VERSION 5.8 ;
BUSBITCHARS "[]" ;
DIVIDERCHAR "/" ;
UNITS
    DATABASE MICRONS 1000 ;
END UNITS

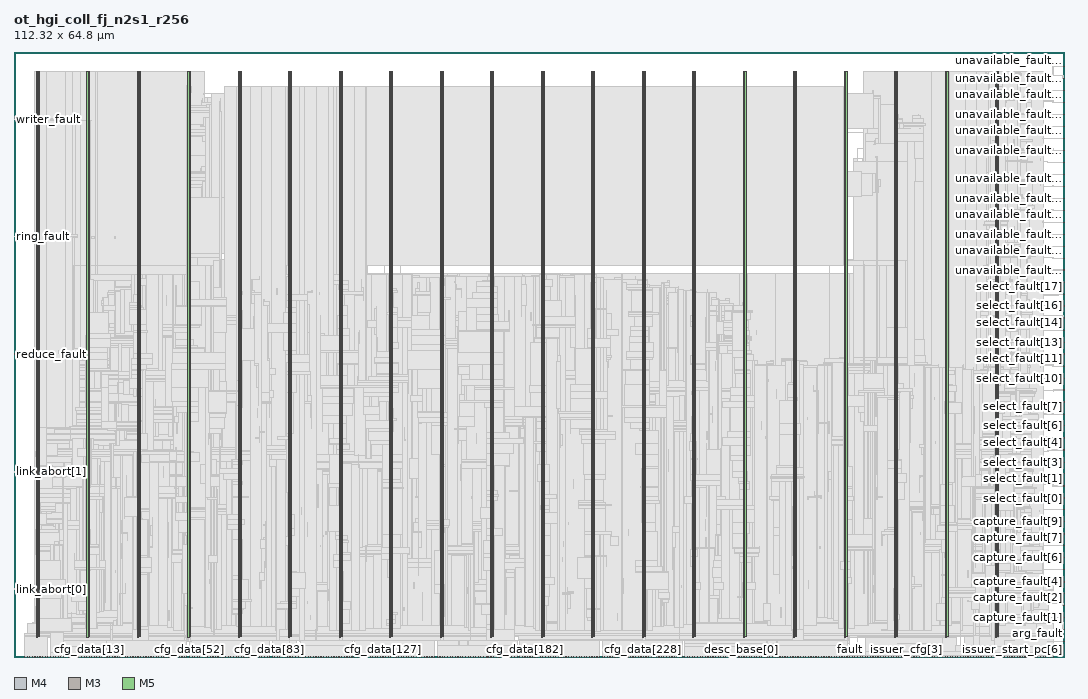
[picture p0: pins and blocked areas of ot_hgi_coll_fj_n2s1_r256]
MACRO ot_hgi_coll_fj_n2s1_r256
  FOREIGN ot_hgi_coll_fj_n2s1_r256 0 0 ;
  CLASS BLOCK ;
  SIZE 112.32 BY 64.8 ;
  PIN arg_fault
    DIRECTION INPUT ;
    USE SIGNAL ;
    PORT
      LAYER M4 ;
        RECT  112.236 1.632 112.32 1.656 ;
    END
  END arg_fault
  PIN capture_fault[0]
    DIRECTION INPUT ;
    USE SIGNAL ;
    PORT
      LAYER M4 ;
        RECT  112.236 2.928 112.32 2.952 ;
    END
  END capture_fault[0]
  PIN capture_fault[1]
    DIRECTION INPUT ;
    USE SIGNAL ;
    PORT
      LAYER M4 ;
        RECT  112.236 4.176 112.32 4.2 ;
    END
  END capture_fault[1]
  PIN capture_fault[2]
    DIRECTION INPUT ;
    USE SIGNAL ;
    PORT
      LAYER M4 ;
        RECT  112.236 5.472 112.32 5.496 ;
    END
  END capture_fault[2]
  PIN capture_fault[3]
    DIRECTION INPUT ;
    USE SIGNAL ;
    PORT
      LAYER M4 ;
        RECT  112.236 6.768 112.32 6.792 ;
    END
  END capture_fault[3]
  PIN capture_fault[4]
    DIRECTION INPUT ;
    USE SIGNAL ;
    PORT
      LAYER M4 ;
        RECT  112.236 8.016 112.32 8.04 ;
    END
  END capture_fault[4]
  PIN capture_fault[5]
    DIRECTION INPUT ;
    USE SIGNAL ;
    PORT
      LAYER M4 ;
        RECT  112.236 9.312 112.32 9.336 ;
    END
  END capture_fault[5]
  PIN capture_fault[6]
    DIRECTION INPUT ;
    USE SIGNAL ;
    PORT
      LAYER M4 ;
        RECT  112.236 10.608 112.32 10.632 ;
    END
  END capture_fault[6]
  PIN capture_fault[7]
    DIRECTION INPUT ;
    USE SIGNAL ;
    PORT
      LAYER M4 ;
        RECT  112.236 11.904 112.32 11.928 ;
    END
  END capture_fault[7]
  PIN capture_fault[8]
    DIRECTION INPUT ;
    USE SIGNAL ;
    PORT
      LAYER M4 ;
        RECT  112.236 13.152 112.32 13.176 ;
    END
  END capture_fault[8]
  PIN capture_fault[9]
    DIRECTION INPUT ;
    USE SIGNAL ;
    PORT
      LAYER M4 ;
        RECT  112.236 14.448 112.32 14.472 ;
    END
  END capture_fault[9]
  PIN cfg_addr[0]
    DIRECTION INPUT ;
    USE SIGNAL ;
    PORT
      LAYER M3 ;
        RECT  1.116 0 1.134 0.038 ;
    END
  END cfg_addr[0]
  PIN cfg_addr[10]
    DIRECTION INPUT ;
    USE SIGNAL ;
    PORT
      LAYER M3 ;
        RECT  3.888 0 3.906 0.038 ;
    END
  END cfg_addr[10]
  PIN cfg_addr[11]
    DIRECTION INPUT ;
    USE SIGNAL ;
    PORT
      LAYER M3 ;
        RECT  4.176 0 4.194 0.038 ;
    END
  END cfg_addr[11]
  PIN cfg_addr[1]
    DIRECTION INPUT ;
    USE SIGNAL ;
    PORT
      LAYER M3 ;
        RECT  1.404 0 1.422 0.038 ;
    END
  END cfg_addr[1]
  PIN cfg_addr[2]
    DIRECTION INPUT ;
    USE SIGNAL ;
    PORT
      LAYER M3 ;
        RECT  1.692 0 1.71 0.038 ;
    END
  END cfg_addr[2]
  PIN cfg_addr[3]
    DIRECTION INPUT ;
    USE SIGNAL ;
    PORT
      LAYER M3 ;
        RECT  1.944 0 1.962 0.038 ;
    END
  END cfg_addr[3]
  PIN cfg_addr[4]
    DIRECTION INPUT ;
    USE SIGNAL ;
    PORT
      LAYER M3 ;
        RECT  2.232 0 2.25 0.038 ;
    END
  END cfg_addr[4]
  PIN cfg_addr[5]
    DIRECTION INPUT ;
    USE SIGNAL ;
    PORT
      LAYER M3 ;
        RECT  2.52 0 2.538 0.038 ;
    END
  END cfg_addr[5]
  PIN cfg_addr[6]
    DIRECTION INPUT ;
    USE SIGNAL ;
    PORT
      LAYER M3 ;
        RECT  2.772 0 2.79 0.038 ;
    END
  END cfg_addr[6]
  PIN cfg_addr[7]
    DIRECTION INPUT ;
    USE SIGNAL ;
    PORT
      LAYER M3 ;
        RECT  3.06 0 3.078 0.038 ;
    END
  END cfg_addr[7]
  PIN cfg_addr[8]
    DIRECTION INPUT ;
    USE SIGNAL ;
    PORT
      LAYER M3 ;
        RECT  3.348 0 3.366 0.038 ;
    END
  END cfg_addr[8]
  PIN cfg_addr[9]
    DIRECTION INPUT ;
    USE SIGNAL ;
    PORT
      LAYER M3 ;
        RECT  3.6 0 3.618 0.038 ;
    END
  END cfg_addr[9]
  PIN cfg_data[0]
    DIRECTION INPUT ;
    USE SIGNAL ;
    PORT
      LAYER M3 ;
        RECT  4.428 0 4.446 0.038 ;
    END
  END cfg_data[0]
  PIN cfg_data[100]
    DIRECTION INPUT ;
    USE SIGNAL ;
    PORT
      LAYER M5 ;
        RECT  32.016 0 32.04 0.084 ;
    END
  END cfg_data[100]
  PIN cfg_data[101]
    DIRECTION INPUT ;
    USE SIGNAL ;
    PORT
      LAYER M5 ;
        RECT  32.304 0 32.328 0.084 ;
    END
  END cfg_data[101]
  PIN cfg_data[102]
    DIRECTION INPUT ;
    USE SIGNAL ;
    PORT
      LAYER M5 ;
        RECT  32.544 0 32.568 0.084 ;
    END
  END cfg_data[102]
  PIN cfg_data[103]
    DIRECTION INPUT ;
    USE SIGNAL ;
    PORT
      LAYER M5 ;
        RECT  32.832 0 32.856 0.084 ;
    END
  END cfg_data[103]
  PIN cfg_data[104]
    DIRECTION INPUT ;
    USE SIGNAL ;
    PORT
      LAYER M5 ;
        RECT  33.12 0 33.144 0.084 ;
    END
  END cfg_data[104]
  PIN cfg_data[105]
    DIRECTION INPUT ;
    USE SIGNAL ;
    PORT
      LAYER M5 ;
        RECT  33.408 0 33.432 0.084 ;
    END
  END cfg_data[105]
  PIN cfg_data[106]
    DIRECTION INPUT ;
    USE SIGNAL ;
    PORT
      LAYER M5 ;
        RECT  33.648 0 33.672 0.084 ;
    END
  END cfg_data[106]
  PIN cfg_data[107]
    DIRECTION INPUT ;
    USE SIGNAL ;
    PORT
      LAYER M5 ;
        RECT  33.936 0 33.96 0.084 ;
    END
  END cfg_data[107]
  PIN cfg_data[108]
    DIRECTION INPUT ;
    USE SIGNAL ;
    PORT
      LAYER M5 ;
        RECT  34.224 0 34.248 0.084 ;
    END
  END cfg_data[108]
  PIN cfg_data[109]
    DIRECTION INPUT ;
    USE SIGNAL ;
    PORT
      LAYER M5 ;
        RECT  34.512 0 34.536 0.084 ;
    END
  END cfg_data[109]
  PIN cfg_data[10]
    DIRECTION INPUT ;
    USE SIGNAL ;
    PORT
      LAYER M3 ;
        RECT  7.2 0 7.218 0.038 ;
    END
  END cfg_data[10]
  PIN cfg_data[110]
    DIRECTION INPUT ;
    USE SIGNAL ;
    PORT
      LAYER M5 ;
        RECT  34.752 0 34.776 0.084 ;
    END
  END cfg_data[110]
  PIN cfg_data[111]
    DIRECTION INPUT ;
    USE SIGNAL ;
    PORT
      LAYER M5 ;
        RECT  35.04 0 35.064 0.084 ;
    END
  END cfg_data[111]
  PIN cfg_data[112]
    DIRECTION INPUT ;
    USE SIGNAL ;
    PORT
      LAYER M5 ;
        RECT  35.328 0 35.352 0.084 ;
    END
  END cfg_data[112]
  PIN cfg_data[113]
    DIRECTION INPUT ;
    USE SIGNAL ;
    PORT
      LAYER M5 ;
        RECT  35.616 0 35.64 0.084 ;
    END
  END cfg_data[113]
  PIN cfg_data[114]
    DIRECTION INPUT ;
    USE SIGNAL ;
    PORT
      LAYER M5 ;
        RECT  35.856 0 35.88 0.084 ;
    END
  END cfg_data[114]
  PIN cfg_data[115]
    DIRECTION INPUT ;
    USE SIGNAL ;
    PORT
      LAYER M5 ;
        RECT  36.144 0 36.168 0.084 ;
    END
  END cfg_data[115]
  PIN cfg_data[116]
    DIRECTION INPUT ;
    USE SIGNAL ;
    PORT
      LAYER M3 ;
        RECT  36.432 0 36.45 0.038 ;
    END
  END cfg_data[116]
  PIN cfg_data[117]
    DIRECTION INPUT ;
    USE SIGNAL ;
    PORT
      LAYER M3 ;
        RECT  36.72 0 36.738 0.038 ;
    END
  END cfg_data[117]
  PIN cfg_data[118]
    DIRECTION INPUT ;
    USE SIGNAL ;
    PORT
      LAYER M3 ;
        RECT  36.972 0 36.99 0.038 ;
    END
  END cfg_data[118]
  PIN cfg_data[119]
    DIRECTION INPUT ;
    USE SIGNAL ;
    PORT
      LAYER M3 ;
        RECT  37.26 0 37.278 0.038 ;
    END
  END cfg_data[119]
  PIN cfg_data[11]
    DIRECTION INPUT ;
    USE SIGNAL ;
    PORT
      LAYER M3 ;
        RECT  7.488 0 7.506 0.038 ;
    END
  END cfg_data[11]
  PIN cfg_data[120]
    DIRECTION INPUT ;
    USE SIGNAL ;
    PORT
      LAYER M3 ;
        RECT  37.548 0 37.566 0.038 ;
    END
  END cfg_data[120]
  PIN cfg_data[121]
    DIRECTION INPUT ;
    USE SIGNAL ;
    PORT
      LAYER M3 ;
        RECT  37.8 0 37.818 0.038 ;
    END
  END cfg_data[121]
  PIN cfg_data[122]
    DIRECTION INPUT ;
    USE SIGNAL ;
    PORT
      LAYER M3 ;
        RECT  38.088 0 38.106 0.038 ;
    END
  END cfg_data[122]
  PIN cfg_data[123]
    DIRECTION INPUT ;
    USE SIGNAL ;
    PORT
      LAYER M3 ;
        RECT  38.376 0 38.394 0.038 ;
    END
  END cfg_data[123]
  PIN cfg_data[124]
    DIRECTION INPUT ;
    USE SIGNAL ;
    PORT
      LAYER M3 ;
        RECT  38.628 0 38.646 0.038 ;
    END
  END cfg_data[124]
  PIN cfg_data[125]
    DIRECTION INPUT ;
    USE SIGNAL ;
    PORT
      LAYER M3 ;
        RECT  38.916 0 38.934 0.038 ;
    END
  END cfg_data[125]
  PIN cfg_data[126]
    DIRECTION INPUT ;
    USE SIGNAL ;
    PORT
      LAYER M3 ;
        RECT  39.204 0 39.222 0.038 ;
    END
  END cfg_data[126]
  PIN cfg_data[127]
    DIRECTION INPUT ;
    USE SIGNAL ;
    PORT
      LAYER M3 ;
        RECT  39.456 0 39.474 0.038 ;
    END
  END cfg_data[127]
  PIN cfg_data[128]
    DIRECTION INPUT ;
    USE SIGNAL ;
    PORT
      LAYER M3 ;
        RECT  39.744 0 39.762 0.038 ;
    END
  END cfg_data[128]
  PIN cfg_data[129]
    DIRECTION INPUT ;
    USE SIGNAL ;
    PORT
      LAYER M3 ;
        RECT  40.032 0 40.05 0.038 ;
    END
  END cfg_data[129]
  PIN cfg_data[12]
    DIRECTION INPUT ;
    USE SIGNAL ;
    PORT
      LAYER M3 ;
        RECT  7.74 0 7.758 0.038 ;
    END
  END cfg_data[12]
  PIN cfg_data[130]
    DIRECTION INPUT ;
    USE SIGNAL ;
    PORT
      LAYER M3 ;
        RECT  40.284 0 40.302 0.038 ;
    END
  END cfg_data[130]
  PIN cfg_data[131]
    DIRECTION INPUT ;
    USE SIGNAL ;
    PORT
      LAYER M3 ;
        RECT  40.572 0 40.59 0.038 ;
    END
  END cfg_data[131]
  PIN cfg_data[132]
    DIRECTION INPUT ;
    USE SIGNAL ;
    PORT
      LAYER M3 ;
        RECT  40.86 0 40.878 0.038 ;
    END
  END cfg_data[132]
  PIN cfg_data[133]
    DIRECTION INPUT ;
    USE SIGNAL ;
    PORT
      LAYER M3 ;
        RECT  41.112 0 41.13 0.038 ;
    END
  END cfg_data[133]
  PIN cfg_data[134]
    DIRECTION INPUT ;
    USE SIGNAL ;
    PORT
      LAYER M3 ;
        RECT  41.4 0 41.418 0.038 ;
    END
  END cfg_data[134]
  PIN cfg_data[135]
    DIRECTION INPUT ;
    USE SIGNAL ;
    PORT
      LAYER M3 ;
        RECT  41.688 0 41.706 0.038 ;
    END
  END cfg_data[135]
  PIN cfg_data[136]
    DIRECTION INPUT ;
    USE SIGNAL ;
    PORT
      LAYER M3 ;
        RECT  41.94 0 41.958 0.038 ;
    END
  END cfg_data[136]
  PIN cfg_data[137]
    DIRECTION INPUT ;
    USE SIGNAL ;
    PORT
      LAYER M3 ;
        RECT  42.228 0 42.246 0.038 ;
    END
  END cfg_data[137]
  PIN cfg_data[138]
    DIRECTION INPUT ;
    USE SIGNAL ;
    PORT
      LAYER M3 ;
        RECT  42.516 0 42.534 0.038 ;
    END
  END cfg_data[138]
  PIN cfg_data[139]
    DIRECTION INPUT ;
    USE SIGNAL ;
    PORT
      LAYER M3 ;
        RECT  42.768 0 42.786 0.038 ;
    END
  END cfg_data[139]
  PIN cfg_data[13]
    DIRECTION INPUT ;
    USE SIGNAL ;
    PORT
      LAYER M3 ;
        RECT  8.028 0 8.046 0.038 ;
    END
  END cfg_data[13]
  PIN cfg_data[140]
    DIRECTION INPUT ;
    USE SIGNAL ;
    PORT
      LAYER M3 ;
        RECT  43.056 0 43.074 0.038 ;
    END
  END cfg_data[140]
  PIN cfg_data[141]
    DIRECTION INPUT ;
    USE SIGNAL ;
    PORT
      LAYER M3 ;
        RECT  43.344 0 43.362 0.038 ;
    END
  END cfg_data[141]
  PIN cfg_data[142]
    DIRECTION INPUT ;
    USE SIGNAL ;
    PORT
      LAYER M3 ;
        RECT  43.596 0 43.614 0.038 ;
    END
  END cfg_data[142]
  PIN cfg_data[143]
    DIRECTION INPUT ;
    USE SIGNAL ;
    PORT
      LAYER M3 ;
        RECT  43.884 0 43.902 0.038 ;
    END
  END cfg_data[143]
  PIN cfg_data[144]
    DIRECTION INPUT ;
    USE SIGNAL ;
    PORT
      LAYER M3 ;
        RECT  44.172 0 44.19 0.038 ;
    END
  END cfg_data[144]
  PIN cfg_data[145]
    DIRECTION INPUT ;
    USE SIGNAL ;
    PORT
      LAYER M3 ;
        RECT  44.424 0 44.442 0.038 ;
    END
  END cfg_data[145]
  PIN cfg_data[146]
    DIRECTION INPUT ;
    USE SIGNAL ;
    PORT
      LAYER M3 ;
        RECT  44.712 0 44.73 0.038 ;
    END
  END cfg_data[146]
  PIN cfg_data[147]
    DIRECTION INPUT ;
    USE SIGNAL ;
    PORT
      LAYER M3 ;
        RECT  44.964 0 44.982 0.038 ;
    END
  END cfg_data[147]
  PIN cfg_data[148]
    DIRECTION INPUT ;
    USE SIGNAL ;
    PORT
      LAYER M5 ;
        RECT  45.264 0 45.288 0.084 ;
    END
  END cfg_data[148]
  PIN cfg_data[149]
    DIRECTION INPUT ;
    USE SIGNAL ;
    PORT
      LAYER M5 ;
        RECT  45.552 0 45.576 0.084 ;
    END
  END cfg_data[149]
  PIN cfg_data[14]
    DIRECTION INPUT ;
    USE SIGNAL ;
    PORT
      LAYER M3 ;
        RECT  8.316 0 8.334 0.038 ;
    END
  END cfg_data[14]
  PIN cfg_data[150]
    DIRECTION INPUT ;
    USE SIGNAL ;
    PORT
      LAYER M5 ;
        RECT  45.792 0 45.816 0.084 ;
    END
  END cfg_data[150]
  PIN cfg_data[151]
    DIRECTION INPUT ;
    USE SIGNAL ;
    PORT
      LAYER M5 ;
        RECT  46.08 0 46.104 0.084 ;
    END
  END cfg_data[151]
  PIN cfg_data[152]
    DIRECTION INPUT ;
    USE SIGNAL ;
    PORT
      LAYER M5 ;
        RECT  46.368 0 46.392 0.084 ;
    END
  END cfg_data[152]
  PIN cfg_data[153]
    DIRECTION INPUT ;
    USE SIGNAL ;
    PORT
      LAYER M5 ;
        RECT  46.656 0 46.68 0.084 ;
    END
  END cfg_data[153]
  PIN cfg_data[154]
    DIRECTION INPUT ;
    USE SIGNAL ;
    PORT
      LAYER M5 ;
        RECT  46.896 0 46.92 0.084 ;
    END
  END cfg_data[154]
  PIN cfg_data[155]
    DIRECTION INPUT ;
    USE SIGNAL ;
    PORT
      LAYER M5 ;
        RECT  47.184 0 47.208 0.084 ;
    END
  END cfg_data[155]
  PIN cfg_data[156]
    DIRECTION INPUT ;
    USE SIGNAL ;
    PORT
      LAYER M5 ;
        RECT  47.472 0 47.496 0.084 ;
    END
  END cfg_data[156]
  PIN cfg_data[157]
    DIRECTION INPUT ;
    USE SIGNAL ;
    PORT
      LAYER M5 ;
        RECT  47.76 0 47.784 0.084 ;
    END
  END cfg_data[157]
  PIN cfg_data[158]
    DIRECTION INPUT ;
    USE SIGNAL ;
    PORT
      LAYER M5 ;
        RECT  48 0 48.024 0.084 ;
    END
  END cfg_data[158]
  PIN cfg_data[159]
    DIRECTION INPUT ;
    USE SIGNAL ;
    PORT
      LAYER M5 ;
        RECT  48.288 0 48.312 0.084 ;
    END
  END cfg_data[159]
  PIN cfg_data[15]
    DIRECTION INPUT ;
    USE SIGNAL ;
    PORT
      LAYER M3 ;
        RECT  8.568 0 8.586 0.038 ;
    END
  END cfg_data[15]
  PIN cfg_data[160]
    DIRECTION INPUT ;
    USE SIGNAL ;
    PORT
      LAYER M5 ;
        RECT  48.576 0 48.6 0.084 ;
    END
  END cfg_data[160]
  PIN cfg_data[161]
    DIRECTION INPUT ;
    USE SIGNAL ;
    PORT
      LAYER M5 ;
        RECT  48.816 0 48.84 0.084 ;
    END
  END cfg_data[161]
  PIN cfg_data[162]
    DIRECTION INPUT ;
    USE SIGNAL ;
    PORT
      LAYER M5 ;
        RECT  49.104 0 49.128 0.084 ;
    END
  END cfg_data[162]
  PIN cfg_data[163]
    DIRECTION INPUT ;
    USE SIGNAL ;
    PORT
      LAYER M5 ;
        RECT  49.392 0 49.416 0.084 ;
    END
  END cfg_data[163]
  PIN cfg_data[164]
    DIRECTION INPUT ;
    USE SIGNAL ;
    PORT
      LAYER M5 ;
        RECT  49.68 0 49.704 0.084 ;
    END
  END cfg_data[164]
  PIN cfg_data[165]
    DIRECTION INPUT ;
    USE SIGNAL ;
    PORT
      LAYER M5 ;
        RECT  49.92 0 49.944 0.084 ;
    END
  END cfg_data[165]
  PIN cfg_data[166]
    DIRECTION INPUT ;
    USE SIGNAL ;
    PORT
      LAYER M5 ;
        RECT  50.208 0 50.232 0.084 ;
    END
  END cfg_data[166]
  PIN cfg_data[167]
    DIRECTION INPUT ;
    USE SIGNAL ;
    PORT
      LAYER M5 ;
        RECT  50.496 0 50.52 0.084 ;
    END
  END cfg_data[167]
  PIN cfg_data[168]
    DIRECTION INPUT ;
    USE SIGNAL ;
    PORT
      LAYER M5 ;
        RECT  50.784 0 50.808 0.084 ;
    END
  END cfg_data[168]
  PIN cfg_data[169]
    DIRECTION INPUT ;
    USE SIGNAL ;
    PORT
      LAYER M5 ;
        RECT  51.024 0 51.048 0.084 ;
    END
  END cfg_data[169]
  PIN cfg_data[16]
    DIRECTION INPUT ;
    USE SIGNAL ;
    PORT
      LAYER M3 ;
        RECT  8.856 0 8.874 0.038 ;
    END
  END cfg_data[16]
  PIN cfg_data[170]
    DIRECTION INPUT ;
    USE SIGNAL ;
    PORT
      LAYER M5 ;
        RECT  51.312 0 51.336 0.084 ;
    END
  END cfg_data[170]
  PIN cfg_data[171]
    DIRECTION INPUT ;
    USE SIGNAL ;
    PORT
      LAYER M5 ;
        RECT  51.6 0 51.624 0.084 ;
    END
  END cfg_data[171]
  PIN cfg_data[172]
    DIRECTION INPUT ;
    USE SIGNAL ;
    PORT
      LAYER M5 ;
        RECT  51.888 0 51.912 0.084 ;
    END
  END cfg_data[172]
  PIN cfg_data[173]
    DIRECTION INPUT ;
    USE SIGNAL ;
    PORT
      LAYER M5 ;
        RECT  52.128 0 52.152 0.084 ;
    END
  END cfg_data[173]
  PIN cfg_data[174]
    DIRECTION INPUT ;
    USE SIGNAL ;
    PORT
      LAYER M5 ;
        RECT  52.416 0 52.44 0.084 ;
    END
  END cfg_data[174]
  PIN cfg_data[175]
    DIRECTION INPUT ;
    USE SIGNAL ;
    PORT
      LAYER M5 ;
        RECT  52.704 0 52.728 0.084 ;
    END
  END cfg_data[175]
  PIN cfg_data[176]
    DIRECTION INPUT ;
    USE SIGNAL ;
    PORT
      LAYER M5 ;
        RECT  52.992 0 53.016 0.084 ;
    END
  END cfg_data[176]
  PIN cfg_data[177]
    DIRECTION INPUT ;
    USE SIGNAL ;
    PORT
      LAYER M5 ;
        RECT  53.232 0 53.256 0.084 ;
    END
  END cfg_data[177]
  PIN cfg_data[178]
    DIRECTION INPUT ;
    USE SIGNAL ;
    PORT
      LAYER M5 ;
        RECT  53.52 0 53.544 0.084 ;
    END
  END cfg_data[178]
  PIN cfg_data[179]
    DIRECTION INPUT ;
    USE SIGNAL ;
    PORT
      LAYER M5 ;
        RECT  53.808 0 53.832 0.084 ;
    END
  END cfg_data[179]
  PIN cfg_data[17]
    DIRECTION INPUT ;
    USE SIGNAL ;
    PORT
      LAYER M3 ;
        RECT  9.144 0 9.162 0.038 ;
    END
  END cfg_data[17]
  PIN cfg_data[180]
    DIRECTION INPUT ;
    USE SIGNAL ;
    PORT
      LAYER M3 ;
        RECT  54.072 0 54.09 0.038 ;
    END
  END cfg_data[180]
  PIN cfg_data[181]
    DIRECTION INPUT ;
    USE SIGNAL ;
    PORT
      LAYER M3 ;
        RECT  54.36 0 54.378 0.038 ;
    END
  END cfg_data[181]
  PIN cfg_data[182]
    DIRECTION INPUT ;
    USE SIGNAL ;
    PORT
      LAYER M3 ;
        RECT  54.648 0 54.666 0.038 ;
    END
  END cfg_data[182]
  PIN cfg_data[183]
    DIRECTION INPUT ;
    USE SIGNAL ;
    PORT
      LAYER M3 ;
        RECT  54.9 0 54.918 0.038 ;
    END
  END cfg_data[183]
  PIN cfg_data[184]
    DIRECTION INPUT ;
    USE SIGNAL ;
    PORT
      LAYER M3 ;
        RECT  55.188 0 55.206 0.038 ;
    END
  END cfg_data[184]
  PIN cfg_data[185]
    DIRECTION INPUT ;
    USE SIGNAL ;
    PORT
      LAYER M3 ;
        RECT  55.476 0 55.494 0.038 ;
    END
  END cfg_data[185]
  PIN cfg_data[186]
    DIRECTION INPUT ;
    USE SIGNAL ;
    PORT
      LAYER M3 ;
        RECT  55.728 0 55.746 0.038 ;
    END
  END cfg_data[186]
  PIN cfg_data[187]
    DIRECTION INPUT ;
    USE SIGNAL ;
    PORT
      LAYER M3 ;
        RECT  56.016 0 56.034 0.038 ;
    END
  END cfg_data[187]
  PIN cfg_data[188]
    DIRECTION INPUT ;
    USE SIGNAL ;
    PORT
      LAYER M3 ;
        RECT  56.304 0 56.322 0.038 ;
    END
  END cfg_data[188]
  PIN cfg_data[189]
    DIRECTION INPUT ;
    USE SIGNAL ;
    PORT
      LAYER M3 ;
        RECT  56.556 0 56.574 0.038 ;
    END
  END cfg_data[189]
  PIN cfg_data[18]
    DIRECTION INPUT ;
    USE SIGNAL ;
    PORT
      LAYER M3 ;
        RECT  9.396 0 9.414 0.038 ;
    END
  END cfg_data[18]
  PIN cfg_data[190]
    DIRECTION INPUT ;
    USE SIGNAL ;
    PORT
      LAYER M3 ;
        RECT  56.844 0 56.862 0.038 ;
    END
  END cfg_data[190]
  PIN cfg_data[191]
    DIRECTION INPUT ;
    USE SIGNAL ;
    PORT
      LAYER M3 ;
        RECT  57.132 0 57.15 0.038 ;
    END
  END cfg_data[191]
  PIN cfg_data[192]
    DIRECTION INPUT ;
    USE SIGNAL ;
    PORT
      LAYER M3 ;
        RECT  57.384 0 57.402 0.038 ;
    END
  END cfg_data[192]
  PIN cfg_data[193]
    DIRECTION INPUT ;
    USE SIGNAL ;
    PORT
      LAYER M3 ;
        RECT  57.672 0 57.69 0.038 ;
    END
  END cfg_data[193]
  PIN cfg_data[194]
    DIRECTION INPUT ;
    USE SIGNAL ;
    PORT
      LAYER M3 ;
        RECT  57.96 0 57.978 0.038 ;
    END
  END cfg_data[194]
  PIN cfg_data[195]
    DIRECTION INPUT ;
    USE SIGNAL ;
    PORT
      LAYER M3 ;
        RECT  58.212 0 58.23 0.038 ;
    END
  END cfg_data[195]
  PIN cfg_data[196]
    DIRECTION INPUT ;
    USE SIGNAL ;
    PORT
      LAYER M3 ;
        RECT  58.5 0 58.518 0.038 ;
    END
  END cfg_data[196]
  PIN cfg_data[197]
    DIRECTION INPUT ;
    USE SIGNAL ;
    PORT
      LAYER M3 ;
        RECT  58.788 0 58.806 0.038 ;
    END
  END cfg_data[197]
  PIN cfg_data[198]
    DIRECTION INPUT ;
    USE SIGNAL ;
    PORT
      LAYER M3 ;
        RECT  59.04 0 59.058 0.038 ;
    END
  END cfg_data[198]
  PIN cfg_data[199]
    DIRECTION INPUT ;
    USE SIGNAL ;
    PORT
      LAYER M3 ;
        RECT  59.328 0 59.346 0.038 ;
    END
  END cfg_data[199]
  PIN cfg_data[19]
    DIRECTION INPUT ;
    USE SIGNAL ;
    PORT
      LAYER M3 ;
        RECT  9.684 0 9.702 0.038 ;
    END
  END cfg_data[19]
  PIN cfg_data[1]
    DIRECTION INPUT ;
    USE SIGNAL ;
    PORT
      LAYER M3 ;
        RECT  4.716 0 4.734 0.038 ;
    END
  END cfg_data[1]
  PIN cfg_data[200]
    DIRECTION INPUT ;
    USE SIGNAL ;
    PORT
      LAYER M3 ;
        RECT  59.616 0 59.634 0.038 ;
    END
  END cfg_data[200]
  PIN cfg_data[201]
    DIRECTION INPUT ;
    USE SIGNAL ;
    PORT
      LAYER M3 ;
        RECT  59.868 0 59.886 0.038 ;
    END
  END cfg_data[201]
  PIN cfg_data[202]
    DIRECTION INPUT ;
    USE SIGNAL ;
    PORT
      LAYER M3 ;
        RECT  60.156 0 60.174 0.038 ;
    END
  END cfg_data[202]
  PIN cfg_data[203]
    DIRECTION INPUT ;
    USE SIGNAL ;
    PORT
      LAYER M3 ;
        RECT  60.444 0 60.462 0.038 ;
    END
  END cfg_data[203]
  PIN cfg_data[204]
    DIRECTION INPUT ;
    USE SIGNAL ;
    PORT
      LAYER M3 ;
        RECT  60.696 0 60.714 0.038 ;
    END
  END cfg_data[204]
  PIN cfg_data[205]
    DIRECTION INPUT ;
    USE SIGNAL ;
    PORT
      LAYER M3 ;
        RECT  60.984 0 61.002 0.038 ;
    END
  END cfg_data[205]
  PIN cfg_data[206]
    DIRECTION INPUT ;
    USE SIGNAL ;
    PORT
      LAYER M3 ;
        RECT  61.236 0 61.254 0.038 ;
    END
  END cfg_data[206]
  PIN cfg_data[207]
    DIRECTION INPUT ;
    USE SIGNAL ;
    PORT
      LAYER M3 ;
        RECT  61.524 0 61.542 0.038 ;
    END
  END cfg_data[207]
  PIN cfg_data[208]
    DIRECTION INPUT ;
    USE SIGNAL ;
    PORT
      LAYER M3 ;
        RECT  61.812 0 61.83 0.038 ;
    END
  END cfg_data[208]
  PIN cfg_data[209]
    DIRECTION INPUT ;
    USE SIGNAL ;
    PORT
      LAYER M3 ;
        RECT  62.064 0 62.082 0.038 ;
    END
  END cfg_data[209]
  PIN cfg_data[20]
    DIRECTION INPUT ;
    USE SIGNAL ;
    PORT
      LAYER M5 ;
        RECT  9.936 0 9.96 0.084 ;
    END
  END cfg_data[20]
  PIN cfg_data[210]
    DIRECTION INPUT ;
    USE SIGNAL ;
    PORT
      LAYER M3 ;
        RECT  62.352 0 62.37 0.038 ;
    END
  END cfg_data[210]
  PIN cfg_data[211]
    DIRECTION INPUT ;
    USE SIGNAL ;
    PORT
      LAYER M3 ;
        RECT  62.64 0 62.658 0.038 ;
    END
  END cfg_data[211]
  PIN cfg_data[212]
    DIRECTION INPUT ;
    USE SIGNAL ;
    PORT
      LAYER M5 ;
        RECT  62.928 0 62.952 0.084 ;
    END
  END cfg_data[212]
  PIN cfg_data[213]
    DIRECTION INPUT ;
    USE SIGNAL ;
    PORT
      LAYER M5 ;
        RECT  63.168 0 63.192 0.084 ;
    END
  END cfg_data[213]
  PIN cfg_data[214]
    DIRECTION INPUT ;
    USE SIGNAL ;
    PORT
      LAYER M5 ;
        RECT  63.456 0 63.48 0.084 ;
    END
  END cfg_data[214]
  PIN cfg_data[215]
    DIRECTION INPUT ;
    USE SIGNAL ;
    PORT
      LAYER M5 ;
        RECT  63.744 0 63.768 0.084 ;
    END
  END cfg_data[215]
  PIN cfg_data[216]
    DIRECTION INPUT ;
    USE SIGNAL ;
    PORT
      LAYER M5 ;
        RECT  64.032 0 64.056 0.084 ;
    END
  END cfg_data[216]
  PIN cfg_data[217]
    DIRECTION INPUT ;
    USE SIGNAL ;
    PORT
      LAYER M5 ;
        RECT  64.272 0 64.296 0.084 ;
    END
  END cfg_data[217]
  PIN cfg_data[218]
    DIRECTION INPUT ;
    USE SIGNAL ;
    PORT
      LAYER M5 ;
        RECT  64.56 0 64.584 0.084 ;
    END
  END cfg_data[218]
  PIN cfg_data[219]
    DIRECTION INPUT ;
    USE SIGNAL ;
    PORT
      LAYER M5 ;
        RECT  64.848 0 64.872 0.084 ;
    END
  END cfg_data[219]
  PIN cfg_data[21]
    DIRECTION INPUT ;
    USE SIGNAL ;
    PORT
      LAYER M5 ;
        RECT  10.224 0 10.248 0.084 ;
    END
  END cfg_data[21]
  PIN cfg_data[220]
    DIRECTION INPUT ;
    USE SIGNAL ;
    PORT
      LAYER M5 ;
        RECT  65.088 0 65.112 0.084 ;
    END
  END cfg_data[220]
  PIN cfg_data[221]
    DIRECTION INPUT ;
    USE SIGNAL ;
    PORT
      LAYER M5 ;
        RECT  65.376 0 65.4 0.084 ;
    END
  END cfg_data[221]
  PIN cfg_data[222]
    DIRECTION INPUT ;
    USE SIGNAL ;
    PORT
      LAYER M5 ;
        RECT  65.664 0 65.688 0.084 ;
    END
  END cfg_data[222]
  PIN cfg_data[223]
    DIRECTION INPUT ;
    USE SIGNAL ;
    PORT
      LAYER M5 ;
        RECT  65.952 0 65.976 0.084 ;
    END
  END cfg_data[223]
  PIN cfg_data[224]
    DIRECTION INPUT ;
    USE SIGNAL ;
    PORT
      LAYER M5 ;
        RECT  66.192 0 66.216 0.084 ;
    END
  END cfg_data[224]
  PIN cfg_data[225]
    DIRECTION INPUT ;
    USE SIGNAL ;
    PORT
      LAYER M5 ;
        RECT  66.48 0 66.504 0.084 ;
    END
  END cfg_data[225]
  PIN cfg_data[226]
    DIRECTION INPUT ;
    USE SIGNAL ;
    PORT
      LAYER M5 ;
        RECT  66.768 0 66.792 0.084 ;
    END
  END cfg_data[226]
  PIN cfg_data[227]
    DIRECTION INPUT ;
    USE SIGNAL ;
    PORT
      LAYER M5 ;
        RECT  67.056 0 67.08 0.084 ;
    END
  END cfg_data[227]
  PIN cfg_data[228]
    DIRECTION INPUT ;
    USE SIGNAL ;
    PORT
      LAYER M5 ;
        RECT  67.296 0 67.32 0.084 ;
    END
  END cfg_data[228]
  PIN cfg_data[229]
    DIRECTION INPUT ;
    USE SIGNAL ;
    PORT
      LAYER M5 ;
        RECT  67.584 0 67.608 0.084 ;
    END
  END cfg_data[229]
  PIN cfg_data[22]
    DIRECTION INPUT ;
    USE SIGNAL ;
    PORT
      LAYER M5 ;
        RECT  10.512 0 10.536 0.084 ;
    END
  END cfg_data[22]
  PIN cfg_data[230]
    DIRECTION INPUT ;
    USE SIGNAL ;
    PORT
      LAYER M5 ;
        RECT  67.872 0 67.896 0.084 ;
    END
  END cfg_data[230]
  PIN cfg_data[231]
    DIRECTION INPUT ;
    USE SIGNAL ;
    PORT
      LAYER M5 ;
        RECT  68.16 0 68.184 0.084 ;
    END
  END cfg_data[231]
  PIN cfg_data[232]
    DIRECTION INPUT ;
    USE SIGNAL ;
    PORT
      LAYER M5 ;
        RECT  68.4 0 68.424 0.084 ;
    END
  END cfg_data[232]
  PIN cfg_data[233]
    DIRECTION INPUT ;
    USE SIGNAL ;
    PORT
      LAYER M5 ;
        RECT  68.688 0 68.712 0.084 ;
    END
  END cfg_data[233]
  PIN cfg_data[234]
    DIRECTION INPUT ;
    USE SIGNAL ;
    PORT
      LAYER M5 ;
        RECT  68.976 0 69 0.084 ;
    END
  END cfg_data[234]
  PIN cfg_data[235]
    DIRECTION INPUT ;
    USE SIGNAL ;
    PORT
      LAYER M5 ;
        RECT  69.264 0 69.288 0.084 ;
    END
  END cfg_data[235]
  PIN cfg_data[236]
    DIRECTION INPUT ;
    USE SIGNAL ;
    PORT
      LAYER M5 ;
        RECT  69.504 0 69.528 0.084 ;
    END
  END cfg_data[236]
  PIN cfg_data[237]
    DIRECTION INPUT ;
    USE SIGNAL ;
    PORT
      LAYER M5 ;
        RECT  69.792 0 69.816 0.084 ;
    END
  END cfg_data[237]
  PIN cfg_data[238]
    DIRECTION INPUT ;
    USE SIGNAL ;
    PORT
      LAYER M5 ;
        RECT  70.08 0 70.104 0.084 ;
    END
  END cfg_data[238]
  PIN cfg_data[239]
    DIRECTION INPUT ;
    USE SIGNAL ;
    PORT
      LAYER M5 ;
        RECT  70.368 0 70.392 0.084 ;
    END
  END cfg_data[239]
  PIN cfg_data[23]
    DIRECTION INPUT ;
    USE SIGNAL ;
    PORT
      LAYER M5 ;
        RECT  10.8 0 10.824 0.084 ;
    END
  END cfg_data[23]
  PIN cfg_data[240]
    DIRECTION INPUT ;
    USE SIGNAL ;
    PORT
      LAYER M5 ;
        RECT  70.608 0 70.632 0.084 ;
    END
  END cfg_data[240]
  PIN cfg_data[241]
    DIRECTION INPUT ;
    USE SIGNAL ;
    PORT
      LAYER M5 ;
        RECT  70.896 0 70.92 0.084 ;
    END
  END cfg_data[241]
  PIN cfg_data[242]
    DIRECTION INPUT ;
    USE SIGNAL ;
    PORT
      LAYER M5 ;
        RECT  71.184 0 71.208 0.084 ;
    END
  END cfg_data[242]
  PIN cfg_data[243]
    DIRECTION INPUT ;
    USE SIGNAL ;
    PORT
      LAYER M5 ;
        RECT  71.472 0 71.496 0.084 ;
    END
  END cfg_data[243]
  PIN cfg_data[244]
    DIRECTION INPUT ;
    USE SIGNAL ;
    PORT
      LAYER M3 ;
        RECT  71.748 0 71.766 0.038 ;
    END
  END cfg_data[244]
  PIN cfg_data[245]
    DIRECTION INPUT ;
    USE SIGNAL ;
    PORT
      LAYER M3 ;
        RECT  72 0 72.018 0.038 ;
    END
  END cfg_data[245]
  PIN cfg_data[246]
    DIRECTION INPUT ;
    USE SIGNAL ;
    PORT
      LAYER M3 ;
        RECT  72.288 0 72.306 0.038 ;
    END
  END cfg_data[246]
  PIN cfg_data[247]
    DIRECTION INPUT ;
    USE SIGNAL ;
    PORT
      LAYER M3 ;
        RECT  72.576 0 72.594 0.038 ;
    END
  END cfg_data[247]
  PIN cfg_data[248]
    DIRECTION INPUT ;
    USE SIGNAL ;
    PORT
      LAYER M3 ;
        RECT  72.828 0 72.846 0.038 ;
    END
  END cfg_data[248]
  PIN cfg_data[249]
    DIRECTION INPUT ;
    USE SIGNAL ;
    PORT
      LAYER M3 ;
        RECT  73.116 0 73.134 0.038 ;
    END
  END cfg_data[249]
  PIN cfg_data[24]
    DIRECTION INPUT ;
    USE SIGNAL ;
    PORT
      LAYER M5 ;
        RECT  11.04 0 11.064 0.084 ;
    END
  END cfg_data[24]
  PIN cfg_data[250]
    DIRECTION INPUT ;
    USE SIGNAL ;
    PORT
      LAYER M3 ;
        RECT  73.404 0 73.422 0.038 ;
    END
  END cfg_data[250]
  PIN cfg_data[251]
    DIRECTION INPUT ;
    USE SIGNAL ;
    PORT
      LAYER M3 ;
        RECT  73.656 0 73.674 0.038 ;
    END
  END cfg_data[251]
  PIN cfg_data[252]
    DIRECTION INPUT ;
    USE SIGNAL ;
    PORT
      LAYER M3 ;
        RECT  73.944 0 73.962 0.038 ;
    END
  END cfg_data[252]
  PIN cfg_data[253]
    DIRECTION INPUT ;
    USE SIGNAL ;
    PORT
      LAYER M3 ;
        RECT  74.232 0 74.25 0.038 ;
    END
  END cfg_data[253]
  PIN cfg_data[254]
    DIRECTION INPUT ;
    USE SIGNAL ;
    PORT
      LAYER M3 ;
        RECT  74.484 0 74.502 0.038 ;
    END
  END cfg_data[254]
  PIN cfg_data[255]
    DIRECTION INPUT ;
    USE SIGNAL ;
    PORT
      LAYER M3 ;
        RECT  74.772 0 74.79 0.038 ;
    END
  END cfg_data[255]
  PIN cfg_data[25]
    DIRECTION INPUT ;
    USE SIGNAL ;
    PORT
      LAYER M5 ;
        RECT  11.328 0 11.352 0.084 ;
    END
  END cfg_data[25]
  PIN cfg_data[26]
    DIRECTION INPUT ;
    USE SIGNAL ;
    PORT
      LAYER M5 ;
        RECT  11.616 0 11.64 0.084 ;
    END
  END cfg_data[26]
  PIN cfg_data[27]
    DIRECTION INPUT ;
    USE SIGNAL ;
    PORT
      LAYER M5 ;
        RECT  11.904 0 11.928 0.084 ;
    END
  END cfg_data[27]
  PIN cfg_data[28]
    DIRECTION INPUT ;
    USE SIGNAL ;
    PORT
      LAYER M5 ;
        RECT  12.144 0 12.168 0.084 ;
    END
  END cfg_data[28]
  PIN cfg_data[29]
    DIRECTION INPUT ;
    USE SIGNAL ;
    PORT
      LAYER M5 ;
        RECT  12.432 0 12.456 0.084 ;
    END
  END cfg_data[29]
  PIN cfg_data[2]
    DIRECTION INPUT ;
    USE SIGNAL ;
    PORT
      LAYER M3 ;
        RECT  5.004 0 5.022 0.038 ;
    END
  END cfg_data[2]
  PIN cfg_data[30]
    DIRECTION INPUT ;
    USE SIGNAL ;
    PORT
      LAYER M5 ;
        RECT  12.72 0 12.744 0.084 ;
    END
  END cfg_data[30]
  PIN cfg_data[31]
    DIRECTION INPUT ;
    USE SIGNAL ;
    PORT
      LAYER M5 ;
        RECT  13.008 0 13.032 0.084 ;
    END
  END cfg_data[31]
  PIN cfg_data[32]
    DIRECTION INPUT ;
    USE SIGNAL ;
    PORT
      LAYER M5 ;
        RECT  13.248 0 13.272 0.084 ;
    END
  END cfg_data[32]
  PIN cfg_data[33]
    DIRECTION INPUT ;
    USE SIGNAL ;
    PORT
      LAYER M5 ;
        RECT  13.536 0 13.56 0.084 ;
    END
  END cfg_data[33]
  PIN cfg_data[34]
    DIRECTION INPUT ;
    USE SIGNAL ;
    PORT
      LAYER M5 ;
        RECT  13.824 0 13.848 0.084 ;
    END
  END cfg_data[34]
  PIN cfg_data[35]
    DIRECTION INPUT ;
    USE SIGNAL ;
    PORT
      LAYER M5 ;
        RECT  14.112 0 14.136 0.084 ;
    END
  END cfg_data[35]
  PIN cfg_data[36]
    DIRECTION INPUT ;
    USE SIGNAL ;
    PORT
      LAYER M5 ;
        RECT  14.352 0 14.376 0.084 ;
    END
  END cfg_data[36]
  PIN cfg_data[37]
    DIRECTION INPUT ;
    USE SIGNAL ;
    PORT
      LAYER M5 ;
        RECT  14.64 0 14.664 0.084 ;
    END
  END cfg_data[37]
  PIN cfg_data[38]
    DIRECTION INPUT ;
    USE SIGNAL ;
    PORT
      LAYER M5 ;
        RECT  14.928 0 14.952 0.084 ;
    END
  END cfg_data[38]
  PIN cfg_data[39]
    DIRECTION INPUT ;
    USE SIGNAL ;
    PORT
      LAYER M5 ;
        RECT  15.216 0 15.24 0.084 ;
    END
  END cfg_data[39]
  PIN cfg_data[3]
    DIRECTION INPUT ;
    USE SIGNAL ;
    PORT
      LAYER M3 ;
        RECT  5.256 0 5.274 0.038 ;
    END
  END cfg_data[3]
  PIN cfg_data[40]
    DIRECTION INPUT ;
    USE SIGNAL ;
    PORT
      LAYER M5 ;
        RECT  15.456 0 15.48 0.084 ;
    END
  END cfg_data[40]
  PIN cfg_data[41]
    DIRECTION INPUT ;
    USE SIGNAL ;
    PORT
      LAYER M5 ;
        RECT  15.744 0 15.768 0.084 ;
    END
  END cfg_data[41]
  PIN cfg_data[42]
    DIRECTION INPUT ;
    USE SIGNAL ;
    PORT
      LAYER M5 ;
        RECT  16.032 0 16.056 0.084 ;
    END
  END cfg_data[42]
  PIN cfg_data[43]
    DIRECTION INPUT ;
    USE SIGNAL ;
    PORT
      LAYER M5 ;
        RECT  16.272 0 16.296 0.084 ;
    END
  END cfg_data[43]
  PIN cfg_data[44]
    DIRECTION INPUT ;
    USE SIGNAL ;
    PORT
      LAYER M5 ;
        RECT  16.56 0 16.584 0.084 ;
    END
  END cfg_data[44]
  PIN cfg_data[45]
    DIRECTION INPUT ;
    USE SIGNAL ;
    PORT
      LAYER M5 ;
        RECT  16.848 0 16.872 0.084 ;
    END
  END cfg_data[45]
  PIN cfg_data[46]
    DIRECTION INPUT ;
    USE SIGNAL ;
    PORT
      LAYER M5 ;
        RECT  17.136 0 17.16 0.084 ;
    END
  END cfg_data[46]
  PIN cfg_data[47]
    DIRECTION INPUT ;
    USE SIGNAL ;
    PORT
      LAYER M5 ;
        RECT  17.376 0 17.4 0.084 ;
    END
  END cfg_data[47]
  PIN cfg_data[48]
    DIRECTION INPUT ;
    USE SIGNAL ;
    PORT
      LAYER M5 ;
        RECT  17.664 0 17.688 0.084 ;
    END
  END cfg_data[48]
  PIN cfg_data[49]
    DIRECTION INPUT ;
    USE SIGNAL ;
    PORT
      LAYER M5 ;
        RECT  17.952 0 17.976 0.084 ;
    END
  END cfg_data[49]
  PIN cfg_data[4]
    DIRECTION INPUT ;
    USE SIGNAL ;
    PORT
      LAYER M3 ;
        RECT  5.544 0 5.562 0.038 ;
    END
  END cfg_data[4]
  PIN cfg_data[50]
    DIRECTION INPUT ;
    USE SIGNAL ;
    PORT
      LAYER M5 ;
        RECT  18.24 0 18.264 0.084 ;
    END
  END cfg_data[50]
  PIN cfg_data[51]
    DIRECTION INPUT ;
    USE SIGNAL ;
    PORT
      LAYER M5 ;
        RECT  18.48 0 18.504 0.084 ;
    END
  END cfg_data[51]
  PIN cfg_data[52]
    DIRECTION INPUT ;
    USE SIGNAL ;
    PORT
      LAYER M3 ;
        RECT  18.792 0 18.81 0.038 ;
    END
  END cfg_data[52]
  PIN cfg_data[53]
    DIRECTION INPUT ;
    USE SIGNAL ;
    PORT
      LAYER M3 ;
        RECT  19.044 0 19.062 0.038 ;
    END
  END cfg_data[53]
  PIN cfg_data[54]
    DIRECTION INPUT ;
    USE SIGNAL ;
    PORT
      LAYER M3 ;
        RECT  19.332 0 19.35 0.038 ;
    END
  END cfg_data[54]
  PIN cfg_data[55]
    DIRECTION INPUT ;
    USE SIGNAL ;
    PORT
      LAYER M3 ;
        RECT  19.62 0 19.638 0.038 ;
    END
  END cfg_data[55]
  PIN cfg_data[56]
    DIRECTION INPUT ;
    USE SIGNAL ;
    PORT
      LAYER M3 ;
        RECT  19.872 0 19.89 0.038 ;
    END
  END cfg_data[56]
  PIN cfg_data[57]
    DIRECTION INPUT ;
    USE SIGNAL ;
    PORT
      LAYER M3 ;
        RECT  20.16 0 20.178 0.038 ;
    END
  END cfg_data[57]
  PIN cfg_data[58]
    DIRECTION INPUT ;
    USE SIGNAL ;
    PORT
      LAYER M3 ;
        RECT  20.448 0 20.466 0.038 ;
    END
  END cfg_data[58]
  PIN cfg_data[59]
    DIRECTION INPUT ;
    USE SIGNAL ;
    PORT
      LAYER M3 ;
        RECT  20.7 0 20.718 0.038 ;
    END
  END cfg_data[59]
  PIN cfg_data[5]
    DIRECTION INPUT ;
    USE SIGNAL ;
    PORT
      LAYER M3 ;
        RECT  5.832 0 5.85 0.038 ;
    END
  END cfg_data[5]
  PIN cfg_data[60]
    DIRECTION INPUT ;
    USE SIGNAL ;
    PORT
      LAYER M3 ;
        RECT  20.988 0 21.006 0.038 ;
    END
  END cfg_data[60]
  PIN cfg_data[61]
    DIRECTION INPUT ;
    USE SIGNAL ;
    PORT
      LAYER M3 ;
        RECT  21.276 0 21.294 0.038 ;
    END
  END cfg_data[61]
  PIN cfg_data[62]
    DIRECTION INPUT ;
    USE SIGNAL ;
    PORT
      LAYER M3 ;
        RECT  21.528 0 21.546 0.038 ;
    END
  END cfg_data[62]
  PIN cfg_data[63]
    DIRECTION INPUT ;
    USE SIGNAL ;
    PORT
      LAYER M3 ;
        RECT  21.816 0 21.834 0.038 ;
    END
  END cfg_data[63]
  PIN cfg_data[64]
    DIRECTION INPUT ;
    USE SIGNAL ;
    PORT
      LAYER M3 ;
        RECT  22.104 0 22.122 0.038 ;
    END
  END cfg_data[64]
  PIN cfg_data[65]
    DIRECTION INPUT ;
    USE SIGNAL ;
    PORT
      LAYER M3 ;
        RECT  22.356 0 22.374 0.038 ;
    END
  END cfg_data[65]
  PIN cfg_data[66]
    DIRECTION INPUT ;
    USE SIGNAL ;
    PORT
      LAYER M3 ;
        RECT  22.644 0 22.662 0.038 ;
    END
  END cfg_data[66]
  PIN cfg_data[67]
    DIRECTION INPUT ;
    USE SIGNAL ;
    PORT
      LAYER M3 ;
        RECT  22.932 0 22.95 0.038 ;
    END
  END cfg_data[67]
  PIN cfg_data[68]
    DIRECTION INPUT ;
    USE SIGNAL ;
    PORT
      LAYER M3 ;
        RECT  23.184 0 23.202 0.038 ;
    END
  END cfg_data[68]
  PIN cfg_data[69]
    DIRECTION INPUT ;
    USE SIGNAL ;
    PORT
      LAYER M3 ;
        RECT  23.472 0 23.49 0.038 ;
    END
  END cfg_data[69]
  PIN cfg_data[6]
    DIRECTION INPUT ;
    USE SIGNAL ;
    PORT
      LAYER M3 ;
        RECT  6.084 0 6.102 0.038 ;
    END
  END cfg_data[6]
  PIN cfg_data[70]
    DIRECTION INPUT ;
    USE SIGNAL ;
    PORT
      LAYER M3 ;
        RECT  23.76 0 23.778 0.038 ;
    END
  END cfg_data[70]
  PIN cfg_data[71]
    DIRECTION INPUT ;
    USE SIGNAL ;
    PORT
      LAYER M3 ;
        RECT  24.012 0 24.03 0.038 ;
    END
  END cfg_data[71]
  PIN cfg_data[72]
    DIRECTION INPUT ;
    USE SIGNAL ;
    PORT
      LAYER M3 ;
        RECT  24.3 0 24.318 0.038 ;
    END
  END cfg_data[72]
  PIN cfg_data[73]
    DIRECTION INPUT ;
    USE SIGNAL ;
    PORT
      LAYER M3 ;
        RECT  24.588 0 24.606 0.038 ;
    END
  END cfg_data[73]
  PIN cfg_data[74]
    DIRECTION INPUT ;
    USE SIGNAL ;
    PORT
      LAYER M3 ;
        RECT  24.84 0 24.858 0.038 ;
    END
  END cfg_data[74]
  PIN cfg_data[75]
    DIRECTION INPUT ;
    USE SIGNAL ;
    PORT
      LAYER M3 ;
        RECT  25.128 0 25.146 0.038 ;
    END
  END cfg_data[75]
  PIN cfg_data[76]
    DIRECTION INPUT ;
    USE SIGNAL ;
    PORT
      LAYER M3 ;
        RECT  25.416 0 25.434 0.038 ;
    END
  END cfg_data[76]
  PIN cfg_data[77]
    DIRECTION INPUT ;
    USE SIGNAL ;
    PORT
      LAYER M3 ;
        RECT  25.668 0 25.686 0.038 ;
    END
  END cfg_data[77]
  PIN cfg_data[78]
    DIRECTION INPUT ;
    USE SIGNAL ;
    PORT
      LAYER M3 ;
        RECT  25.956 0 25.974 0.038 ;
    END
  END cfg_data[78]
  PIN cfg_data[79]
    DIRECTION INPUT ;
    USE SIGNAL ;
    PORT
      LAYER M3 ;
        RECT  26.244 0 26.262 0.038 ;
    END
  END cfg_data[79]
  PIN cfg_data[7]
    DIRECTION INPUT ;
    USE SIGNAL ;
    PORT
      LAYER M3 ;
        RECT  6.372 0 6.39 0.038 ;
    END
  END cfg_data[7]
  PIN cfg_data[80]
    DIRECTION INPUT ;
    USE SIGNAL ;
    PORT
      LAYER M3 ;
        RECT  26.496 0 26.514 0.038 ;
    END
  END cfg_data[80]
  PIN cfg_data[81]
    DIRECTION INPUT ;
    USE SIGNAL ;
    PORT
      LAYER M3 ;
        RECT  26.784 0 26.802 0.038 ;
    END
  END cfg_data[81]
  PIN cfg_data[82]
    DIRECTION INPUT ;
    USE SIGNAL ;
    PORT
      LAYER M3 ;
        RECT  27.072 0 27.09 0.038 ;
    END
  END cfg_data[82]
  PIN cfg_data[83]
    DIRECTION INPUT ;
    USE SIGNAL ;
    PORT
      LAYER M3 ;
        RECT  27.324 0 27.342 0.038 ;
    END
  END cfg_data[83]
  PIN cfg_data[84]
    DIRECTION INPUT ;
    USE SIGNAL ;
    PORT
      LAYER M5 ;
        RECT  27.6 0 27.624 0.084 ;
    END
  END cfg_data[84]
  PIN cfg_data[85]
    DIRECTION INPUT ;
    USE SIGNAL ;
    PORT
      LAYER M5 ;
        RECT  27.888 0 27.912 0.084 ;
    END
  END cfg_data[85]
  PIN cfg_data[86]
    DIRECTION INPUT ;
    USE SIGNAL ;
    PORT
      LAYER M5 ;
        RECT  28.176 0 28.2 0.084 ;
    END
  END cfg_data[86]
  PIN cfg_data[87]
    DIRECTION INPUT ;
    USE SIGNAL ;
    PORT
      LAYER M5 ;
        RECT  28.416 0 28.44 0.084 ;
    END
  END cfg_data[87]
  PIN cfg_data[88]
    DIRECTION INPUT ;
    USE SIGNAL ;
    PORT
      LAYER M5 ;
        RECT  28.704 0 28.728 0.084 ;
    END
  END cfg_data[88]
  PIN cfg_data[89]
    DIRECTION INPUT ;
    USE SIGNAL ;
    PORT
      LAYER M5 ;
        RECT  28.992 0 29.016 0.084 ;
    END
  END cfg_data[89]
  PIN cfg_data[8]
    DIRECTION INPUT ;
    USE SIGNAL ;
    PORT
      LAYER M3 ;
        RECT  6.66 0 6.678 0.038 ;
    END
  END cfg_data[8]
  PIN cfg_data[90]
    DIRECTION INPUT ;
    USE SIGNAL ;
    PORT
      LAYER M5 ;
        RECT  29.28 0 29.304 0.084 ;
    END
  END cfg_data[90]
  PIN cfg_data[91]
    DIRECTION INPUT ;
    USE SIGNAL ;
    PORT
      LAYER M5 ;
        RECT  29.52 0 29.544 0.084 ;
    END
  END cfg_data[91]
  PIN cfg_data[92]
    DIRECTION INPUT ;
    USE SIGNAL ;
    PORT
      LAYER M5 ;
        RECT  29.808 0 29.832 0.084 ;
    END
  END cfg_data[92]
  PIN cfg_data[93]
    DIRECTION INPUT ;
    USE SIGNAL ;
    PORT
      LAYER M5 ;
        RECT  30.096 0 30.12 0.084 ;
    END
  END cfg_data[93]
  PIN cfg_data[94]
    DIRECTION INPUT ;
    USE SIGNAL ;
    PORT
      LAYER M5 ;
        RECT  30.384 0 30.408 0.084 ;
    END
  END cfg_data[94]
  PIN cfg_data[95]
    DIRECTION INPUT ;
    USE SIGNAL ;
    PORT
      LAYER M5 ;
        RECT  30.624 0 30.648 0.084 ;
    END
  END cfg_data[95]
  PIN cfg_data[96]
    DIRECTION INPUT ;
    USE SIGNAL ;
    PORT
      LAYER M5 ;
        RECT  30.912 0 30.936 0.084 ;
    END
  END cfg_data[96]
  PIN cfg_data[97]
    DIRECTION INPUT ;
    USE SIGNAL ;
    PORT
      LAYER M5 ;
        RECT  31.2 0 31.224 0.084 ;
    END
  END cfg_data[97]
  PIN cfg_data[98]
    DIRECTION INPUT ;
    USE SIGNAL ;
    PORT
      LAYER M5 ;
        RECT  31.488 0 31.512 0.084 ;
    END
  END cfg_data[98]
  PIN cfg_data[99]
    DIRECTION INPUT ;
    USE SIGNAL ;
    PORT
      LAYER M5 ;
        RECT  31.728 0 31.752 0.084 ;
    END
  END cfg_data[99]
  PIN cfg_data[9]
    DIRECTION INPUT ;
    USE SIGNAL ;
    PORT
      LAYER M3 ;
        RECT  6.912 0 6.93 0.038 ;
    END
  END cfg_data[9]
  PIN cfg_target[0]
    DIRECTION INPUT ;
    USE SIGNAL ;
    PORT
      LAYER M3 ;
        RECT  75.06 0 75.078 0.038 ;
    END
  END cfg_target[0]
  PIN cfg_target[1]
    DIRECTION INPUT ;
    USE SIGNAL ;
    PORT
      LAYER M3 ;
        RECT  75.312 0 75.33 0.038 ;
    END
  END cfg_target[1]
  PIN cfg_target[2]
    DIRECTION INPUT ;
    USE SIGNAL ;
    PORT
      LAYER M3 ;
        RECT  75.6 0 75.618 0.038 ;
    END
  END cfg_target[2]
  PIN cfg_target[3]
    DIRECTION INPUT ;
    USE SIGNAL ;
    PORT
      LAYER M3 ;
        RECT  75.888 0 75.906 0.038 ;
    END
  END cfg_target[3]
  PIN cfg_target[4]
    DIRECTION INPUT ;
    USE SIGNAL ;
    PORT
      LAYER M3 ;
        RECT  76.14 0 76.158 0.038 ;
    END
  END cfg_target[4]
  PIN cfg_target[5]
    DIRECTION INPUT ;
    USE SIGNAL ;
    PORT
      LAYER M3 ;
        RECT  76.428 0 76.446 0.038 ;
    END
  END cfg_target[5]
  PIN cfg_target[6]
    DIRECTION INPUT ;
    USE SIGNAL ;
    PORT
      LAYER M3 ;
        RECT  76.716 0 76.734 0.038 ;
    END
  END cfg_target[6]
  PIN cfg_target[7]
    DIRECTION INPUT ;
    USE SIGNAL ;
    PORT
      LAYER M3 ;
        RECT  76.968 0 76.986 0.038 ;
    END
  END cfg_target[7]
  PIN cfg_v
    DIRECTION INPUT ;
    USE SIGNAL ;
    PORT
      LAYER M3 ;
        RECT  77.256 0 77.274 0.038 ;
    END
  END cfg_v
  PIN clk
    DIRECTION INPUT ;
    USE SIGNAL ;
    PORT
      LAYER M3 ;
        RECT  50.58 0 50.598 0.038 ;
    END
  END clk
  PIN configured
    DIRECTION OUTPUT ;
    USE SIGNAL ;
    PORT
      LAYER M3 ;
        RECT  77.544 0 77.562 0.038 ;
    END
  END configured
  PIN desc_base[0]
    DIRECTION INPUT ;
    USE SIGNAL ;
    PORT
      LAYER M3 ;
        RECT  77.796 0 77.814 0.038 ;
    END
  END desc_base[0]
  PIN desc_base[10]
    DIRECTION INPUT ;
    USE SIGNAL ;
    PORT
      LAYER M5 ;
        RECT  80.544 0 80.568 0.084 ;
    END
  END desc_base[10]
  PIN desc_base[11]
    DIRECTION INPUT ;
    USE SIGNAL ;
    PORT
      LAYER M5 ;
        RECT  80.832 0 80.856 0.084 ;
    END
  END desc_base[11]
  PIN desc_base[1]
    DIRECTION INPUT ;
    USE SIGNAL ;
    PORT
      LAYER M3 ;
        RECT  78.084 0 78.102 0.038 ;
    END
  END desc_base[1]
  PIN desc_base[2]
    DIRECTION INPUT ;
    USE SIGNAL ;
    PORT
      LAYER M3 ;
        RECT  78.336 0 78.354 0.038 ;
    END
  END desc_base[2]
  PIN desc_base[3]
    DIRECTION INPUT ;
    USE SIGNAL ;
    PORT
      LAYER M3 ;
        RECT  78.624 0 78.642 0.038 ;
    END
  END desc_base[3]
  PIN desc_base[4]
    DIRECTION INPUT ;
    USE SIGNAL ;
    PORT
      LAYER M3 ;
        RECT  78.912 0 78.93 0.038 ;
    END
  END desc_base[4]
  PIN desc_base[5]
    DIRECTION INPUT ;
    USE SIGNAL ;
    PORT
      LAYER M3 ;
        RECT  79.164 0 79.182 0.038 ;
    END
  END desc_base[5]
  PIN desc_base[6]
    DIRECTION INPUT ;
    USE SIGNAL ;
    PORT
      LAYER M3 ;
        RECT  79.452 0 79.47 0.038 ;
    END
  END desc_base[6]
  PIN desc_base[7]
    DIRECTION INPUT ;
    USE SIGNAL ;
    PORT
      LAYER M3 ;
        RECT  79.74 0 79.758 0.038 ;
    END
  END desc_base[7]
  PIN desc_base[8]
    DIRECTION INPUT ;
    USE SIGNAL ;
    PORT
      LAYER M3 ;
        RECT  79.992 0 80.01 0.038 ;
    END
  END desc_base[8]
  PIN desc_base[9]
    DIRECTION INPUT ;
    USE SIGNAL ;
    PORT
      LAYER M3 ;
        RECT  80.28 0 80.298 0.038 ;
    END
  END desc_base[9]
  PIN desc_limit[0]
    DIRECTION INPUT ;
    USE SIGNAL ;
    PORT
      LAYER M5 ;
        RECT  81.12 0 81.144 0.084 ;
    END
  END desc_limit[0]
  PIN desc_limit[10]
    DIRECTION INPUT ;
    USE SIGNAL ;
    PORT
      LAYER M5 ;
        RECT  83.856 0 83.88 0.084 ;
    END
  END desc_limit[10]
  PIN desc_limit[11]
    DIRECTION INPUT ;
    USE SIGNAL ;
    PORT
      LAYER M5 ;
        RECT  84.144 0 84.168 0.084 ;
    END
  END desc_limit[11]
  PIN desc_limit[12]
    DIRECTION INPUT ;
    USE SIGNAL ;
    PORT
      LAYER M5 ;
        RECT  84.432 0 84.456 0.084 ;
    END
  END desc_limit[12]
  PIN desc_limit[1]
    DIRECTION INPUT ;
    USE SIGNAL ;
    PORT
      LAYER M5 ;
        RECT  81.408 0 81.432 0.084 ;
    END
  END desc_limit[1]
  PIN desc_limit[2]
    DIRECTION INPUT ;
    USE SIGNAL ;
    PORT
      LAYER M5 ;
        RECT  81.648 0 81.672 0.084 ;
    END
  END desc_limit[2]
  PIN desc_limit[3]
    DIRECTION INPUT ;
    USE SIGNAL ;
    PORT
      LAYER M5 ;
        RECT  81.936 0 81.96 0.084 ;
    END
  END desc_limit[3]
  PIN desc_limit[4]
    DIRECTION INPUT ;
    USE SIGNAL ;
    PORT
      LAYER M5 ;
        RECT  82.224 0 82.248 0.084 ;
    END
  END desc_limit[4]
  PIN desc_limit[5]
    DIRECTION INPUT ;
    USE SIGNAL ;
    PORT
      LAYER M5 ;
        RECT  82.464 0 82.488 0.084 ;
    END
  END desc_limit[5]
  PIN desc_limit[6]
    DIRECTION INPUT ;
    USE SIGNAL ;
    PORT
      LAYER M5 ;
        RECT  82.752 0 82.776 0.084 ;
    END
  END desc_limit[6]
  PIN desc_limit[7]
    DIRECTION INPUT ;
    USE SIGNAL ;
    PORT
      LAYER M5 ;
        RECT  83.04 0 83.064 0.084 ;
    END
  END desc_limit[7]
  PIN desc_limit[8]
    DIRECTION INPUT ;
    USE SIGNAL ;
    PORT
      LAYER M5 ;
        RECT  83.328 0 83.352 0.084 ;
    END
  END desc_limit[8]
  PIN desc_limit[9]
    DIRECTION INPUT ;
    USE SIGNAL ;
    PORT
      LAYER M5 ;
        RECT  83.568 0 83.592 0.084 ;
    END
  END desc_limit[9]
  PIN desc_loops[0]
    DIRECTION INPUT ;
    USE SIGNAL ;
    PORT
      LAYER M5 ;
        RECT  84.672 0 84.696 0.084 ;
    END
  END desc_loops[0]
  PIN desc_loops[10]
    DIRECTION INPUT ;
    USE SIGNAL ;
    PORT
      LAYER M5 ;
        RECT  87.456 0 87.48 0.084 ;
    END
  END desc_loops[10]
  PIN desc_loops[11]
    DIRECTION INPUT ;
    USE SIGNAL ;
    PORT
      LAYER M5 ;
        RECT  87.744 0 87.768 0.084 ;
    END
  END desc_loops[11]
  PIN desc_loops[12]
    DIRECTION INPUT ;
    USE SIGNAL ;
    PORT
      LAYER M5 ;
        RECT  87.984 0 88.008 0.084 ;
    END
  END desc_loops[12]
  PIN desc_loops[13]
    DIRECTION INPUT ;
    USE SIGNAL ;
    PORT
      LAYER M5 ;
        RECT  88.272 0 88.296 0.084 ;
    END
  END desc_loops[13]
  PIN desc_loops[14]
    DIRECTION INPUT ;
    USE SIGNAL ;
    PORT
      LAYER M5 ;
        RECT  88.56 0 88.584 0.084 ;
    END
  END desc_loops[14]
  PIN desc_loops[15]
    DIRECTION INPUT ;
    USE SIGNAL ;
    PORT
      LAYER M5 ;
        RECT  88.848 0 88.872 0.084 ;
    END
  END desc_loops[15]
  PIN desc_loops[1]
    DIRECTION INPUT ;
    USE SIGNAL ;
    PORT
      LAYER M5 ;
        RECT  84.96 0 84.984 0.084 ;
    END
  END desc_loops[1]
  PIN desc_loops[2]
    DIRECTION INPUT ;
    USE SIGNAL ;
    PORT
      LAYER M5 ;
        RECT  85.248 0 85.272 0.084 ;
    END
  END desc_loops[2]
  PIN desc_loops[3]
    DIRECTION INPUT ;
    USE SIGNAL ;
    PORT
      LAYER M5 ;
        RECT  85.536 0 85.56 0.084 ;
    END
  END desc_loops[3]
  PIN desc_loops[4]
    DIRECTION INPUT ;
    USE SIGNAL ;
    PORT
      LAYER M5 ;
        RECT  85.776 0 85.8 0.084 ;
    END
  END desc_loops[4]
  PIN desc_loops[5]
    DIRECTION INPUT ;
    USE SIGNAL ;
    PORT
      LAYER M5 ;
        RECT  86.064 0 86.088 0.084 ;
    END
  END desc_loops[5]
  PIN desc_loops[6]
    DIRECTION INPUT ;
    USE SIGNAL ;
    PORT
      LAYER M5 ;
        RECT  86.352 0 86.376 0.084 ;
    END
  END desc_loops[6]
  PIN desc_loops[7]
    DIRECTION INPUT ;
    USE SIGNAL ;
    PORT
      LAYER M5 ;
        RECT  86.64 0 86.664 0.084 ;
    END
  END desc_loops[7]
  PIN desc_loops[8]
    DIRECTION INPUT ;
    USE SIGNAL ;
    PORT
      LAYER M5 ;
        RECT  86.88 0 86.904 0.084 ;
    END
  END desc_loops[8]
  PIN desc_loops[9]
    DIRECTION INPUT ;
    USE SIGNAL ;
    PORT
      LAYER M5 ;
        RECT  87.168 0 87.192 0.084 ;
    END
  END desc_loops[9]
  PIN desc_v
    DIRECTION INPUT ;
    USE SIGNAL ;
    PORT
      LAYER M5 ;
        RECT  89.088 0 89.112 0.084 ;
    END
  END desc_v
  PIN fault
    DIRECTION OUTPUT ;
    USE SIGNAL ;
    PORT
      LAYER M3 ;
        RECT  89.388 0 89.406 0.038 ;
    END
  END fault
  PIN fault_cause[0]
    DIRECTION OUTPUT ;
    USE SIGNAL ;
    PORT
      LAYER M3 ;
        RECT  89.676 0 89.694 0.038 ;
    END
  END fault_cause[0]
  PIN fault_cause[10]
    DIRECTION OUTPUT ;
    USE SIGNAL ;
    PORT
      LAYER M3 ;
        RECT  92.412 0 92.43 0.038 ;
    END
  END fault_cause[10]
  PIN fault_cause[11]
    DIRECTION OUTPUT ;
    USE SIGNAL ;
    PORT
      LAYER M3 ;
        RECT  92.7 0 92.718 0.038 ;
    END
  END fault_cause[11]
  PIN fault_cause[12]
    DIRECTION OUTPUT ;
    USE SIGNAL ;
    PORT
      LAYER M3 ;
        RECT  92.988 0 93.006 0.038 ;
    END
  END fault_cause[12]
  PIN fault_cause[13]
    DIRECTION OUTPUT ;
    USE SIGNAL ;
    PORT
      LAYER M3 ;
        RECT  93.24 0 93.258 0.038 ;
    END
  END fault_cause[13]
  PIN fault_cause[14]
    DIRECTION OUTPUT ;
    USE SIGNAL ;
    PORT
      LAYER M3 ;
        RECT  93.528 0 93.546 0.038 ;
    END
  END fault_cause[14]
  PIN fault_cause[15]
    DIRECTION OUTPUT ;
    USE SIGNAL ;
    PORT
      LAYER M3 ;
        RECT  93.816 0 93.834 0.038 ;
    END
  END fault_cause[15]
  PIN fault_cause[1]
    DIRECTION OUTPUT ;
    USE SIGNAL ;
    PORT
      LAYER M3 ;
        RECT  89.928 0 89.946 0.038 ;
    END
  END fault_cause[1]
  PIN fault_cause[2]
    DIRECTION OUTPUT ;
    USE SIGNAL ;
    PORT
      LAYER M3 ;
        RECT  90.216 0 90.234 0.038 ;
    END
  END fault_cause[2]
  PIN fault_cause[3]
    DIRECTION OUTPUT ;
    USE SIGNAL ;
    PORT
      LAYER M3 ;
        RECT  90.504 0 90.522 0.038 ;
    END
  END fault_cause[3]
  PIN fault_cause[4]
    DIRECTION OUTPUT ;
    USE SIGNAL ;
    PORT
      LAYER M3 ;
        RECT  90.756 0 90.774 0.038 ;
    END
  END fault_cause[4]
  PIN fault_cause[5]
    DIRECTION OUTPUT ;
    USE SIGNAL ;
    PORT
      LAYER M3 ;
        RECT  91.044 0 91.062 0.038 ;
    END
  END fault_cause[5]
  PIN fault_cause[6]
    DIRECTION OUTPUT ;
    USE SIGNAL ;
    PORT
      LAYER M3 ;
        RECT  91.332 0 91.35 0.038 ;
    END
  END fault_cause[6]
  PIN fault_cause[7]
    DIRECTION OUTPUT ;
    USE SIGNAL ;
    PORT
      LAYER M3 ;
        RECT  91.584 0 91.602 0.038 ;
    END
  END fault_cause[7]
  PIN fault_cause[8]
    DIRECTION OUTPUT ;
    USE SIGNAL ;
    PORT
      LAYER M3 ;
        RECT  91.872 0 91.89 0.038 ;
    END
  END fault_cause[8]
  PIN fault_cause[9]
    DIRECTION OUTPUT ;
    USE SIGNAL ;
    PORT
      LAYER M3 ;
        RECT  92.16 0 92.178 0.038 ;
    END
  END fault_cause[9]
  PIN init_busy
    DIRECTION OUTPUT ;
    USE SIGNAL ;
    PORT
      LAYER M3 ;
        RECT  94.068 0 94.086 0.038 ;
    END
  END init_busy
  PIN issuer_busy
    DIRECTION INPUT ;
    USE SIGNAL ;
    PORT
      LAYER M3 ;
        RECT  94.356 0 94.374 0.038 ;
    END
  END issuer_busy
  PIN issuer_cfg[0]
    DIRECTION OUTPUT ;
    USE SIGNAL ;
    PORT
      LAYER M3 ;
        RECT  94.608 0 94.626 0.038 ;
    END
  END issuer_cfg[0]
  PIN issuer_cfg[10]
    DIRECTION OUTPUT ;
    USE SIGNAL ;
    PORT
      LAYER M3 ;
        RECT  97.38 0 97.398 0.038 ;
    END
  END issuer_cfg[10]
  PIN issuer_cfg[11]
    DIRECTION OUTPUT ;
    USE SIGNAL ;
    PORT
      LAYER M3 ;
        RECT  97.668 0 97.686 0.038 ;
    END
  END issuer_cfg[11]
  PIN issuer_cfg[12]
    DIRECTION OUTPUT ;
    USE SIGNAL ;
    PORT
      LAYER M3 ;
        RECT  97.92 0 97.938 0.038 ;
    END
  END issuer_cfg[12]
  PIN issuer_cfg[13]
    DIRECTION OUTPUT ;
    USE SIGNAL ;
    PORT
      LAYER M5 ;
        RECT  98.208 0 98.232 0.084 ;
    END
  END issuer_cfg[13]
  PIN issuer_cfg[14]
    DIRECTION OUTPUT ;
    USE SIGNAL ;
    PORT
      LAYER M5 ;
        RECT  98.496 0 98.52 0.084 ;
    END
  END issuer_cfg[14]
  PIN issuer_cfg[15]
    DIRECTION OUTPUT ;
    USE SIGNAL ;
    PORT
      LAYER M5 ;
        RECT  98.736 0 98.76 0.084 ;
    END
  END issuer_cfg[15]
  PIN issuer_cfg[16]
    DIRECTION OUTPUT ;
    USE SIGNAL ;
    PORT
      LAYER M5 ;
        RECT  99.024 0 99.048 0.084 ;
    END
  END issuer_cfg[16]
  PIN issuer_cfg[17]
    DIRECTION OUTPUT ;
    USE SIGNAL ;
    PORT
      LAYER M5 ;
        RECT  99.312 0 99.336 0.084 ;
    END
  END issuer_cfg[17]
  PIN issuer_cfg[18]
    DIRECTION OUTPUT ;
    USE SIGNAL ;
    PORT
      LAYER M5 ;
        RECT  99.6 0 99.624 0.084 ;
    END
  END issuer_cfg[18]
  PIN issuer_cfg[19]
    DIRECTION OUTPUT ;
    USE SIGNAL ;
    PORT
      LAYER M5 ;
        RECT  99.84 0 99.864 0.084 ;
    END
  END issuer_cfg[19]
  PIN issuer_cfg[1]
    DIRECTION OUTPUT ;
    USE SIGNAL ;
    PORT
      LAYER M3 ;
        RECT  94.896 0 94.914 0.038 ;
    END
  END issuer_cfg[1]
  PIN issuer_cfg[20]
    DIRECTION OUTPUT ;
    USE SIGNAL ;
    PORT
      LAYER M5 ;
        RECT  100.128 0 100.152 0.084 ;
    END
  END issuer_cfg[20]
  PIN issuer_cfg[21]
    DIRECTION OUTPUT ;
    USE SIGNAL ;
    PORT
      LAYER M5 ;
        RECT  100.416 0 100.44 0.084 ;
    END
  END issuer_cfg[21]
  PIN issuer_cfg[22]
    DIRECTION OUTPUT ;
    USE SIGNAL ;
    PORT
      LAYER M5 ;
        RECT  100.704 0 100.728 0.084 ;
    END
  END issuer_cfg[22]
  PIN issuer_cfg[23]
    DIRECTION OUTPUT ;
    USE SIGNAL ;
    PORT
      LAYER M5 ;
        RECT  100.944 0 100.968 0.084 ;
    END
  END issuer_cfg[23]
  PIN issuer_cfg[24]
    DIRECTION OUTPUT ;
    USE SIGNAL ;
    PORT
      LAYER M5 ;
        RECT  101.232 0 101.256 0.084 ;
    END
  END issuer_cfg[24]
  PIN issuer_cfg[25]
    DIRECTION OUTPUT ;
    USE SIGNAL ;
    PORT
      LAYER M5 ;
        RECT  101.52 0 101.544 0.084 ;
    END
  END issuer_cfg[25]
  PIN issuer_cfg[26]
    DIRECTION OUTPUT ;
    USE SIGNAL ;
    PORT
      LAYER M5 ;
        RECT  101.808 0 101.832 0.084 ;
    END
  END issuer_cfg[26]
  PIN issuer_cfg[27]
    DIRECTION OUTPUT ;
    USE SIGNAL ;
    PORT
      LAYER M5 ;
        RECT  102.048 0 102.072 0.084 ;
    END
  END issuer_cfg[27]
  PIN issuer_cfg[28]
    DIRECTION OUTPUT ;
    USE SIGNAL ;
    PORT
      LAYER M5 ;
        RECT  102.336 0 102.36 0.084 ;
    END
  END issuer_cfg[28]
  PIN issuer_cfg[29]
    DIRECTION OUTPUT ;
    USE SIGNAL ;
    PORT
      LAYER M5 ;
        RECT  102.624 0 102.648 0.084 ;
    END
  END issuer_cfg[29]
  PIN issuer_cfg[2]
    DIRECTION OUTPUT ;
    USE SIGNAL ;
    PORT
      LAYER M3 ;
        RECT  95.184 0 95.202 0.038 ;
    END
  END issuer_cfg[2]
  PIN issuer_cfg[30]
    DIRECTION OUTPUT ;
    USE SIGNAL ;
    PORT
      LAYER M5 ;
        RECT  102.912 0 102.936 0.084 ;
    END
  END issuer_cfg[30]
  PIN issuer_cfg[31]
    DIRECTION OUTPUT ;
    USE SIGNAL ;
    PORT
      LAYER M5 ;
        RECT  103.152 0 103.176 0.084 ;
    END
  END issuer_cfg[31]
  PIN issuer_cfg[32]
    DIRECTION OUTPUT ;
    USE SIGNAL ;
    PORT
      LAYER M5 ;
        RECT  103.44 0 103.464 0.084 ;
    END
  END issuer_cfg[32]
  PIN issuer_cfg[33]
    DIRECTION OUTPUT ;
    USE SIGNAL ;
    PORT
      LAYER M5 ;
        RECT  103.728 0 103.752 0.084 ;
    END
  END issuer_cfg[33]
  PIN issuer_cfg[34]
    DIRECTION OUTPUT ;
    USE SIGNAL ;
    PORT
      LAYER M5 ;
        RECT  104.016 0 104.04 0.084 ;
    END
  END issuer_cfg[34]
  PIN issuer_cfg[35]
    DIRECTION OUTPUT ;
    USE SIGNAL ;
    PORT
      LAYER M5 ;
        RECT  104.256 0 104.28 0.084 ;
    END
  END issuer_cfg[35]
  PIN issuer_cfg[36]
    DIRECTION OUTPUT ;
    USE SIGNAL ;
    PORT
      LAYER M5 ;
        RECT  104.544 0 104.568 0.084 ;
    END
  END issuer_cfg[36]
  PIN issuer_cfg[3]
    DIRECTION OUTPUT ;
    USE SIGNAL ;
    PORT
      LAYER M3 ;
        RECT  95.436 0 95.454 0.038 ;
    END
  END issuer_cfg[3]
  PIN issuer_cfg[4]
    DIRECTION OUTPUT ;
    USE SIGNAL ;
    PORT
      LAYER M3 ;
        RECT  95.724 0 95.742 0.038 ;
    END
  END issuer_cfg[4]
  PIN issuer_cfg[5]
    DIRECTION OUTPUT ;
    USE SIGNAL ;
    PORT
      LAYER M3 ;
        RECT  96.012 0 96.03 0.038 ;
    END
  END issuer_cfg[5]
  PIN issuer_cfg[6]
    DIRECTION OUTPUT ;
    USE SIGNAL ;
    PORT
      LAYER M3 ;
        RECT  96.264 0 96.282 0.038 ;
    END
  END issuer_cfg[6]
  PIN issuer_cfg[7]
    DIRECTION OUTPUT ;
    USE SIGNAL ;
    PORT
      LAYER M3 ;
        RECT  96.552 0 96.57 0.038 ;
    END
  END issuer_cfg[7]
  PIN issuer_cfg[8]
    DIRECTION OUTPUT ;
    USE SIGNAL ;
    PORT
      LAYER M3 ;
        RECT  96.84 0 96.858 0.038 ;
    END
  END issuer_cfg[8]
  PIN issuer_cfg[9]
    DIRECTION OUTPUT ;
    USE SIGNAL ;
    PORT
      LAYER M3 ;
        RECT  97.092 0 97.11 0.038 ;
    END
  END issuer_cfg[9]
  PIN issuer_fault
    DIRECTION INPUT ;
    USE SIGNAL ;
    PORT
      LAYER M5 ;
        RECT  104.832 0 104.856 0.084 ;
    END
  END issuer_fault
  PIN issuer_start
    DIRECTION OUTPUT ;
    USE SIGNAL ;
    PORT
      LAYER M5 ;
        RECT  105.12 0 105.144 0.084 ;
    END
  END issuer_start
  PIN issuer_start_pc[0]
    DIRECTION OUTPUT ;
    USE SIGNAL ;
    PORT
      LAYER M5 ;
        RECT  105.36 0 105.384 0.084 ;
    END
  END issuer_start_pc[0]
  PIN issuer_start_pc[1]
    DIRECTION OUTPUT ;
    USE SIGNAL ;
    PORT
      LAYER M5 ;
        RECT  105.648 0 105.672 0.084 ;
    END
  END issuer_start_pc[1]
  PIN issuer_start_pc[2]
    DIRECTION OUTPUT ;
    USE SIGNAL ;
    PORT
      LAYER M5 ;
        RECT  105.936 0 105.96 0.084 ;
    END
  END issuer_start_pc[2]
  PIN issuer_start_pc[3]
    DIRECTION OUTPUT ;
    USE SIGNAL ;
    PORT
      LAYER M5 ;
        RECT  106.224 0 106.248 0.084 ;
    END
  END issuer_start_pc[3]
  PIN issuer_start_pc[4]
    DIRECTION OUTPUT ;
    USE SIGNAL ;
    PORT
      LAYER M5 ;
        RECT  106.464 0 106.488 0.084 ;
    END
  END issuer_start_pc[4]
  PIN issuer_start_pc[5]
    DIRECTION OUTPUT ;
    USE SIGNAL ;
    PORT
      LAYER M5 ;
        RECT  106.752 0 106.776 0.084 ;
    END
  END issuer_start_pc[5]
  PIN issuer_start_pc[6]
    DIRECTION OUTPUT ;
    USE SIGNAL ;
    PORT
      LAYER M3 ;
        RECT  107.028 0 107.046 0.038 ;
    END
  END issuer_start_pc[6]
  PIN issuer_start_pc[7]
    DIRECTION OUTPUT ;
    USE SIGNAL ;
    PORT
      LAYER M3 ;
        RECT  107.316 0 107.334 0.038 ;
    END
  END issuer_start_pc[7]
  PIN issuer_uop_pc[0]
    DIRECTION INPUT ;
    USE SIGNAL ;
    PORT
      LAYER M3 ;
        RECT  107.604 0 107.622 0.038 ;
    END
  END issuer_uop_pc[0]
  PIN issuer_uop_pc[1]
    DIRECTION INPUT ;
    USE SIGNAL ;
    PORT
      LAYER M3 ;
        RECT  107.856 0 107.874 0.038 ;
    END
  END issuer_uop_pc[1]
  PIN issuer_uop_pc[2]
    DIRECTION INPUT ;
    USE SIGNAL ;
    PORT
      LAYER M3 ;
        RECT  108.144 0 108.162 0.038 ;
    END
  END issuer_uop_pc[2]
  PIN issuer_uop_pc[3]
    DIRECTION INPUT ;
    USE SIGNAL ;
    PORT
      LAYER M3 ;
        RECT  108.432 0 108.45 0.038 ;
    END
  END issuer_uop_pc[3]
  PIN issuer_uop_pc[4]
    DIRECTION INPUT ;
    USE SIGNAL ;
    PORT
      LAYER M3 ;
        RECT  108.684 0 108.702 0.038 ;
    END
  END issuer_uop_pc[4]
  PIN issuer_uop_pc[5]
    DIRECTION INPUT ;
    USE SIGNAL ;
    PORT
      LAYER M3 ;
        RECT  108.972 0 108.99 0.038 ;
    END
  END issuer_uop_pc[5]
  PIN issuer_uop_pc[6]
    DIRECTION INPUT ;
    USE SIGNAL ;
    PORT
      LAYER M3 ;
        RECT  109.26 0 109.278 0.038 ;
    END
  END issuer_uop_pc[6]
  PIN issuer_uop_pc[7]
    DIRECTION INPUT ;
    USE SIGNAL ;
    PORT
      LAYER M3 ;
        RECT  109.512 0 109.53 0.038 ;
    END
  END issuer_uop_pc[7]
  PIN issuer_uop_v
    DIRECTION INPUT ;
    USE SIGNAL ;
    PORT
      LAYER M3 ;
        RECT  109.8 0 109.818 0.038 ;
    END
  END issuer_uop_v
  PIN launch_v
    DIRECTION INPUT ;
    USE SIGNAL ;
    PORT
      LAYER M3 ;
        RECT  110.088 0 110.106 0.038 ;
    END
  END launch_v
  PIN link_abort[0]
    DIRECTION INPUT ;
    USE SIGNAL ;
    PORT
      LAYER M4 ;
        RECT  0 7.248 0.084 7.272 ;
    END
  END link_abort[0]
  PIN link_abort[1]
    DIRECTION INPUT ;
    USE SIGNAL ;
    PORT
      LAYER M4 ;
        RECT  0 19.824 0.084 19.848 ;
    END
  END link_abort[1]
  PIN program_active
    DIRECTION INPUT ;
    USE SIGNAL ;
    PORT
      LAYER M3 ;
        RECT  110.34 0 110.358 0.038 ;
    END
  END program_active
  PIN program_fault
    DIRECTION OUTPUT ;
    USE SIGNAL ;
    PORT
      LAYER M3 ;
        RECT  110.628 0 110.646 0.038 ;
    END
  END program_fault
  PIN protocol_fault
    DIRECTION INPUT ;
    USE SIGNAL ;
    PORT
      LAYER M4 ;
        RECT  112.236 15.744 112.32 15.768 ;
    END
  END protocol_fault
  PIN qid[0]
    DIRECTION INPUT ;
    USE SIGNAL ;
    PORT
      LAYER M3 ;
        RECT  110.88 0 110.898 0.038 ;
    END
  END qid[0]
  PIN qid[1]
    DIRECTION INPUT ;
    USE SIGNAL ;
    PORT
      LAYER M3 ;
        RECT  111.168 0 111.186 0.038 ;
    END
  END qid[1]
  PIN reduce_fault
    DIRECTION INPUT ;
    USE SIGNAL ;
    PORT
      LAYER M4 ;
        RECT  0 32.4 0.084 32.424 ;
    END
  END reduce_fault
  PIN ring_fault
    DIRECTION INPUT ;
    USE SIGNAL ;
    PORT
      LAYER M4 ;
        RECT  0 44.928 0.084 44.952 ;
    END
  END ring_fault
  PIN rst_n
    DIRECTION INPUT ;
    USE SIGNAL ;
    PORT
      LAYER M3 ;
        RECT  51.804 0 51.822 0.038 ;
    END
  END rst_n
  PIN select_fault[0]
    DIRECTION INPUT ;
    USE SIGNAL ;
    PORT
      LAYER M4 ;
        RECT  112.236 16.992 112.32 17.016 ;
    END
  END select_fault[0]
  PIN select_fault[10]
    DIRECTION INPUT ;
    USE SIGNAL ;
    PORT
      LAYER M4 ;
        RECT  112.236 29.808 112.32 29.832 ;
    END
  END select_fault[10]
  PIN select_fault[11]
    DIRECTION INPUT ;
    USE SIGNAL ;
    PORT
      LAYER M4 ;
        RECT  112.236 31.104 112.32 31.128 ;
    END
  END select_fault[11]
  PIN select_fault[12]
    DIRECTION INPUT ;
    USE SIGNAL ;
    PORT
      LAYER M4 ;
        RECT  112.236 32.4 112.32 32.424 ;
    END
  END select_fault[12]
  PIN select_fault[13]
    DIRECTION INPUT ;
    USE SIGNAL ;
    PORT
      LAYER M4 ;
        RECT  112.236 33.648 112.32 33.672 ;
    END
  END select_fault[13]
  PIN select_fault[14]
    DIRECTION INPUT ;
    USE SIGNAL ;
    PORT
      LAYER M4 ;
        RECT  112.236 34.944 112.32 34.968 ;
    END
  END select_fault[14]
  PIN select_fault[15]
    DIRECTION INPUT ;
    USE SIGNAL ;
    PORT
      LAYER M4 ;
        RECT  112.236 36.24 112.32 36.264 ;
    END
  END select_fault[15]
  PIN select_fault[16]
    DIRECTION INPUT ;
    USE SIGNAL ;
    PORT
      LAYER M4 ;
        RECT  112.236 37.536 112.32 37.56 ;
    END
  END select_fault[16]
  PIN select_fault[17]
    DIRECTION INPUT ;
    USE SIGNAL ;
    PORT
      LAYER M4 ;
        RECT  112.236 38.784 112.32 38.808 ;
    END
  END select_fault[17]
  PIN select_fault[1]
    DIRECTION INPUT ;
    USE SIGNAL ;
    PORT
      LAYER M4 ;
        RECT  112.236 18.288 112.32 18.312 ;
    END
  END select_fault[1]
  PIN select_fault[2]
    DIRECTION INPUT ;
    USE SIGNAL ;
    PORT
      LAYER M4 ;
        RECT  112.236 19.584 112.32 19.608 ;
    END
  END select_fault[2]
  PIN select_fault[3]
    DIRECTION INPUT ;
    USE SIGNAL ;
    PORT
      LAYER M4 ;
        RECT  112.236 20.832 112.32 20.856 ;
    END
  END select_fault[3]
  PIN select_fault[4]
    DIRECTION INPUT ;
    USE SIGNAL ;
    PORT
      LAYER M4 ;
        RECT  112.236 22.128 112.32 22.152 ;
    END
  END select_fault[4]
  PIN select_fault[5]
    DIRECTION INPUT ;
    USE SIGNAL ;
    PORT
      LAYER M4 ;
        RECT  112.236 23.424 112.32 23.448 ;
    END
  END select_fault[5]
  PIN select_fault[6]
    DIRECTION INPUT ;
    USE SIGNAL ;
    PORT
      LAYER M4 ;
        RECT  112.236 24.72 112.32 24.744 ;
    END
  END select_fault[6]
  PIN select_fault[7]
    DIRECTION INPUT ;
    USE SIGNAL ;
    PORT
      LAYER M4 ;
        RECT  112.236 25.968 112.32 25.992 ;
    END
  END select_fault[7]
  PIN select_fault[8]
    DIRECTION INPUT ;
    USE SIGNAL ;
    PORT
      LAYER M4 ;
        RECT  112.236 27.264 112.32 27.288 ;
    END
  END select_fault[8]
  PIN select_fault[9]
    DIRECTION INPUT ;
    USE SIGNAL ;
    PORT
      LAYER M4 ;
        RECT  112.236 28.56 112.32 28.584 ;
    END
  END select_fault[9]
  PIN tkm_fault
    DIRECTION INPUT ;
    USE SIGNAL ;
    PORT
      LAYER M4 ;
        RECT  112.236 40.08 112.32 40.104 ;
    END
  END tkm_fault
  PIN unavailable_fault[0]
    DIRECTION INPUT ;
    USE SIGNAL ;
    PORT
      LAYER M4 ;
        RECT  112.236 41.376 112.32 41.4 ;
    END
  END unavailable_fault[0]
  PIN unavailable_fault[10]
    DIRECTION INPUT ;
    USE SIGNAL ;
    PORT
      LAYER M4 ;
        RECT  112.236 54.192 112.32 54.216 ;
    END
  END unavailable_fault[10]
  PIN unavailable_fault[11]
    DIRECTION INPUT ;
    USE SIGNAL ;
    PORT
      LAYER M4 ;
        RECT  112.236 55.44 112.32 55.464 ;
    END
  END unavailable_fault[11]
  PIN unavailable_fault[12]
    DIRECTION INPUT ;
    USE SIGNAL ;
    PORT
      LAYER M4 ;
        RECT  112.236 56.736 112.32 56.76 ;
    END
  END unavailable_fault[12]
  PIN unavailable_fault[13]
    DIRECTION INPUT ;
    USE SIGNAL ;
    PORT
      LAYER M4 ;
        RECT  112.236 58.032 112.32 58.056 ;
    END
  END unavailable_fault[13]
  PIN unavailable_fault[14]
    DIRECTION INPUT ;
    USE SIGNAL ;
    PORT
      LAYER M4 ;
        RECT  112.236 59.28 112.32 59.304 ;
    END
  END unavailable_fault[14]
  PIN unavailable_fault[15]
    DIRECTION INPUT ;
    USE SIGNAL ;
    PORT
      LAYER M4 ;
        RECT  112.236 60.576 112.32 60.6 ;
    END
  END unavailable_fault[15]
  PIN unavailable_fault[16]
    DIRECTION INPUT ;
    USE SIGNAL ;
    PORT
      LAYER M4 ;
        RECT  112.236 61.872 112.32 61.896 ;
    END
  END unavailable_fault[16]
  PIN unavailable_fault[17]
    DIRECTION INPUT ;
    USE SIGNAL ;
    PORT
      LAYER M4 ;
        RECT  112.236 63.168 112.32 63.192 ;
    END
  END unavailable_fault[17]
  PIN unavailable_fault[1]
    DIRECTION INPUT ;
    USE SIGNAL ;
    PORT
      LAYER M4 ;
        RECT  112.236 42.624 112.32 42.648 ;
    END
  END unavailable_fault[1]
  PIN unavailable_fault[2]
    DIRECTION INPUT ;
    USE SIGNAL ;
    PORT
      LAYER M4 ;
        RECT  112.236 43.92 112.32 43.944 ;
    END
  END unavailable_fault[2]
  PIN unavailable_fault[3]
    DIRECTION INPUT ;
    USE SIGNAL ;
    PORT
      LAYER M4 ;
        RECT  112.236 45.216 112.32 45.24 ;
    END
  END unavailable_fault[3]
  PIN unavailable_fault[4]
    DIRECTION INPUT ;
    USE SIGNAL ;
    PORT
      LAYER M4 ;
        RECT  112.236 46.464 112.32 46.488 ;
    END
  END unavailable_fault[4]
  PIN unavailable_fault[5]
    DIRECTION INPUT ;
    USE SIGNAL ;
    PORT
      LAYER M4 ;
        RECT  112.236 47.76 112.32 47.784 ;
    END
  END unavailable_fault[5]
  PIN unavailable_fault[6]
    DIRECTION INPUT ;
    USE SIGNAL ;
    PORT
      LAYER M4 ;
        RECT  112.236 49.056 112.32 49.08 ;
    END
  END unavailable_fault[6]
  PIN unavailable_fault[7]
    DIRECTION INPUT ;
    USE SIGNAL ;
    PORT
      LAYER M4 ;
        RECT  112.236 50.352 112.32 50.376 ;
    END
  END unavailable_fault[7]
  PIN unavailable_fault[8]
    DIRECTION INPUT ;
    USE SIGNAL ;
    PORT
      LAYER M4 ;
        RECT  112.236 51.6 112.32 51.624 ;
    END
  END unavailable_fault[8]
  PIN unavailable_fault[9]
    DIRECTION INPUT ;
    USE SIGNAL ;
    PORT
      LAYER M4 ;
        RECT  112.236 52.896 112.32 52.92 ;
    END
  END unavailable_fault[9]
  PIN writer_fault
    DIRECTION INPUT ;
    USE SIGNAL ;
    PORT
      LAYER M4 ;
        RECT  0 57.504 0.084 57.528 ;
    END
  END writer_fault
  PIN VDD
    DIRECTION INOUT ;
    USE POWER ;
    PORT
      LAYER M5 ;
        RECT  105.192 2.151 105.312 62.649 ;
        RECT  99.792 2.151 99.912 62.649 ;
        RECT  94.392 2.151 94.512 62.649 ;
        RECT  88.992 2.151 89.112 62.649 ;
        RECT  83.592 2.151 83.712 62.649 ;
        RECT  78.192 2.151 78.312 62.649 ;
        RECT  72.792 2.151 72.912 62.649 ;
        RECT  67.392 2.151 67.512 62.649 ;
        RECT  61.992 2.151 62.112 62.649 ;
        RECT  56.592 2.151 56.712 62.649 ;
        RECT  51.192 2.151 51.312 62.649 ;
        RECT  45.792 2.151 45.912 62.649 ;
        RECT  40.392 2.151 40.512 62.649 ;
        RECT  34.992 2.151 35.112 62.649 ;
        RECT  29.592 2.151 29.712 62.649 ;
        RECT  24.192 2.151 24.312 62.649 ;
        RECT  18.792 2.151 18.912 62.649 ;
        RECT  13.392 2.151 13.512 62.649 ;
        RECT  7.992 2.151 8.112 62.649 ;
        RECT  2.592 2.151 2.712 62.649 ;
    END
  END VDD
  PIN VSS
    DIRECTION INOUT ;
    USE GROUND ;
    PORT
      LAYER M5 ;
        RECT  105 2.137 105.12 62.663 ;
        RECT  99.6 2.137 99.72 62.663 ;
        RECT  94.2 2.137 94.32 62.663 ;
        RECT  88.8 2.137 88.92 62.649 ;
        RECT  83.4 2.137 83.52 62.649 ;
        RECT  78 2.137 78.12 62.649 ;
        RECT  72.6 2.137 72.72 62.649 ;
        RECT  67.2 2.137 67.32 62.649 ;
        RECT  61.8 2.137 61.92 62.649 ;
        RECT  56.4 2.137 56.52 62.649 ;
        RECT  51 2.137 51.12 62.649 ;
        RECT  45.6 2.137 45.72 62.649 ;
        RECT  40.2 2.137 40.32 62.649 ;
        RECT  34.8 2.137 34.92 62.649 ;
        RECT  29.4 2.137 29.52 62.649 ;
        RECT  24 2.137 24.12 62.649 ;
        RECT  18.6 2.137 18.72 62.663 ;
        RECT  13.2 2.137 13.32 62.663 ;
        RECT  7.8 2.137 7.92 62.663 ;
        RECT  2.4 2.137 2.52 62.663 ;
    END
  END VSS
  OBS
    LAYER RVTN ;
     RECT  2.16 2.16 110.16 2.295 ;
     RECT  2.16 2.565 110.16 2.835 ;
     RECT  2.16 3.105 110.16 3.375 ;
     RECT  2.16 3.645 110.16 3.915 ;
     RECT  2.16 4.185 110.16 4.455 ;
     RECT  2.16 4.725 110.16 4.995 ;
     RECT  2.16 5.265 110.16 5.535 ;
     RECT  2.16 5.805 110.16 6.075 ;
     RECT  2.16 6.345 110.16 6.615 ;
     RECT  2.16 6.885 110.16 7.155 ;
     RECT  2.16 7.425 110.16 7.695 ;
     RECT  2.16 7.965 110.16 8.235 ;
     RECT  2.16 8.505 110.16 8.775 ;
     RECT  2.16 9.045 110.16 9.315 ;
     RECT  2.16 9.585 110.16 9.855 ;
     RECT  2.16 10.125 110.16 10.395 ;
     RECT  2.16 10.665 110.16 10.935 ;
     RECT  2.16 11.205 110.16 11.475 ;
     RECT  2.16 11.745 110.16 12.015 ;
     RECT  2.16 12.285 110.16 12.555 ;
     RECT  2.16 12.825 110.16 13.095 ;
     RECT  2.16 13.365 110.16 13.635 ;
     RECT  2.16 13.905 110.16 14.175 ;
     RECT  2.16 14.445 110.16 14.715 ;
     RECT  2.16 14.985 110.16 15.255 ;
     RECT  2.16 15.525 110.16 15.795 ;
     RECT  2.16 16.065 110.16 16.335 ;
     RECT  2.16 16.605 110.16 16.875 ;
     RECT  2.16 17.145 110.16 17.415 ;
     RECT  2.16 17.685 110.16 17.955 ;
     RECT  2.16 18.225 110.16 18.495 ;
     RECT  2.16 18.765 110.16 19.035 ;
     RECT  2.16 19.305 110.16 19.575 ;
     RECT  2.16 19.845 110.16 20.115 ;
     RECT  2.16 20.385 110.16 20.655 ;
     RECT  2.16 20.925 110.16 21.195 ;
     RECT  2.16 21.465 110.16 21.735 ;
     RECT  2.16 22.005 110.16 22.275 ;
     RECT  2.16 22.545 110.16 22.815 ;
     RECT  2.16 23.085 110.16 23.355 ;
     RECT  2.16 23.625 110.16 23.895 ;
     RECT  2.16 24.165 110.16 24.435 ;
     RECT  2.16 24.705 110.16 24.975 ;
     RECT  2.16 25.245 110.16 25.515 ;
     RECT  2.16 25.785 110.16 26.055 ;
     RECT  2.16 26.325 110.16 26.595 ;
     RECT  2.16 26.865 110.16 27.135 ;
     RECT  2.16 27.405 110.16 27.675 ;
     RECT  2.16 27.945 110.16 28.215 ;
     RECT  2.16 28.485 110.16 28.755 ;
     RECT  2.16 29.025 110.16 29.295 ;
     RECT  2.16 29.565 110.16 29.835 ;
     RECT  2.16 30.105 110.16 30.375 ;
     RECT  2.16 30.645 110.16 30.915 ;
     RECT  2.16 31.185 110.16 31.455 ;
     RECT  2.16 31.725 110.16 31.995 ;
     RECT  2.16 32.265 110.16 32.535 ;
     RECT  2.16 32.805 110.16 33.075 ;
     RECT  2.16 33.345 110.16 33.615 ;
     RECT  2.16 33.885 110.16 34.155 ;
     RECT  2.16 34.425 110.16 34.695 ;
     RECT  2.16 34.965 110.16 35.235 ;
     RECT  2.16 35.505 110.16 35.775 ;
     RECT  2.16 36.045 110.16 36.315 ;
     RECT  2.16 36.585 110.16 36.855 ;
     RECT  2.16 37.125 110.16 37.395 ;
     RECT  2.16 37.665 110.16 37.935 ;
     RECT  2.16 38.205 110.16 38.475 ;
     RECT  2.16 38.745 110.16 39.015 ;
     RECT  2.16 39.285 110.16 39.555 ;
     RECT  2.16 39.825 110.16 40.095 ;
     RECT  2.16 40.365 110.16 40.635 ;
     RECT  2.16 40.905 110.16 41.04 ;
     RECT  2.16 41.04 20.412 41.175 ;
     RECT  90.828 41.04 110.16 41.175 ;
     RECT  2.16 41.445 20.412 41.715 ;
     RECT  90.828 41.445 110.16 41.715 ;
     RECT  2.16 41.985 20.412 42.255 ;
     RECT  90.828 41.985 110.16 42.255 ;
     RECT  2.16 42.525 20.412 42.795 ;
     RECT  90.828 42.525 110.16 42.795 ;
     RECT  2.16 43.065 20.412 43.335 ;
     RECT  90.828 43.065 110.16 43.335 ;
     RECT  2.16 43.605 20.412 43.875 ;
     RECT  90.828 43.605 110.16 43.875 ;
     RECT  2.16 44.145 20.412 44.415 ;
     RECT  90.828 44.145 110.16 44.415 ;
     RECT  2.16 44.685 20.412 44.955 ;
     RECT  90.828 44.685 110.16 44.955 ;
     RECT  2.16 45.225 20.412 45.495 ;
     RECT  90.828 45.225 110.16 45.495 ;
     RECT  2.16 45.765 20.412 46.035 ;
     RECT  90.828 45.765 110.16 46.035 ;
     RECT  2.16 46.305 20.412 46.575 ;
     RECT  90.828 46.305 110.16 46.575 ;
     RECT  2.16 46.845 20.412 47.115 ;
     RECT  90.828 46.845 110.16 47.115 ;
     RECT  2.16 47.385 20.412 47.655 ;
     RECT  90.828 47.385 110.16 47.655 ;
     RECT  2.16 47.925 20.412 48.195 ;
     RECT  90.828 47.925 110.16 48.195 ;
     RECT  2.16 48.465 20.412 48.735 ;
     RECT  90.828 48.465 110.16 48.735 ;
     RECT  2.16 49.005 20.412 49.275 ;
     RECT  90.828 49.005 110.16 49.275 ;
     RECT  2.16 49.545 20.412 49.815 ;
     RECT  90.828 49.545 110.16 49.815 ;
     RECT  2.16 50.085 20.412 50.355 ;
     RECT  90.828 50.085 110.16 50.355 ;
     RECT  2.16 50.625 20.412 50.895 ;
     RECT  90.828 50.625 110.16 50.895 ;
     RECT  2.16 51.165 20.412 51.435 ;
     RECT  90.828 51.165 110.16 51.435 ;
     RECT  2.16 51.705 20.412 51.975 ;
     RECT  90.828 51.705 110.16 51.975 ;
     RECT  2.16 52.245 20.412 52.515 ;
     RECT  90.828 52.245 110.16 52.515 ;
     RECT  2.16 52.785 20.412 53.055 ;
     RECT  90.828 52.785 110.16 53.055 ;
     RECT  2.16 53.325 20.412 53.595 ;
     RECT  90.828 53.325 110.16 53.595 ;
     RECT  2.16 53.865 20.412 54.135 ;
     RECT  90.828 53.865 110.16 54.135 ;
     RECT  2.16 54.405 20.412 54.675 ;
     RECT  90.828 54.405 110.16 54.675 ;
     RECT  2.16 54.945 20.412 55.215 ;
     RECT  90.828 54.945 110.16 55.215 ;
     RECT  2.16 55.485 20.412 55.755 ;
     RECT  90.828 55.485 110.16 55.755 ;
     RECT  2.16 56.025 20.412 56.295 ;
     RECT  90.828 56.025 110.16 56.295 ;
     RECT  2.16 56.565 20.412 56.835 ;
     RECT  90.828 56.565 110.16 56.835 ;
     RECT  2.16 57.105 20.412 57.375 ;
     RECT  90.828 57.105 110.16 57.375 ;
     RECT  2.16 57.645 20.412 57.915 ;
     RECT  90.828 57.645 110.16 57.915 ;
     RECT  2.16 58.185 20.412 58.455 ;
     RECT  90.828 58.185 110.16 58.455 ;
     RECT  2.16 58.725 20.412 58.995 ;
     RECT  90.828 58.725 110.16 58.995 ;
     RECT  2.16 59.265 20.412 59.535 ;
     RECT  90.828 59.265 110.16 59.535 ;
     RECT  2.16 59.805 20.412 60.075 ;
     RECT  90.828 59.805 110.16 60.075 ;
     RECT  2.16 60.345 20.412 60.615 ;
     RECT  90.828 60.345 110.16 60.615 ;
     RECT  2.16 60.885 20.412 61.155 ;
     RECT  90.828 60.885 110.16 61.155 ;
     RECT  2.16 61.425 20.412 61.695 ;
     RECT  90.828 61.425 110.16 61.695 ;
     RECT  2.16 61.965 20.412 62.235 ;
     RECT  90.828 61.965 110.16 62.235 ;
     RECT  2.16 62.505 20.412 62.64 ;
     RECT  90.828 62.505 110.16 62.64 ;
    LAYER RVTP ;
     RECT  2.16 2.295 110.16 2.565 ;
     RECT  2.16 2.835 110.16 3.105 ;
     RECT  2.16 3.375 110.16 3.645 ;
     RECT  2.16 3.915 110.16 4.185 ;
     RECT  2.16 4.455 110.16 4.725 ;
     RECT  2.16 4.995 110.16 5.265 ;
     RECT  2.16 5.535 110.16 5.805 ;
     RECT  2.16 6.075 110.16 6.345 ;
     RECT  2.16 6.615 110.16 6.885 ;
     RECT  2.16 7.155 110.16 7.425 ;
     RECT  2.16 7.695 110.16 7.965 ;
     RECT  2.16 8.235 110.16 8.505 ;
     RECT  2.16 8.775 110.16 9.045 ;
     RECT  2.16 9.315 110.16 9.585 ;
     RECT  2.16 9.855 110.16 10.125 ;
     RECT  2.16 10.395 110.16 10.665 ;
     RECT  2.16 10.935 110.16 11.205 ;
     RECT  2.16 11.475 110.16 11.745 ;
     RECT  2.16 12.015 110.16 12.285 ;
     RECT  2.16 12.555 110.16 12.825 ;
     RECT  2.16 13.095 110.16 13.365 ;
     RECT  2.16 13.635 110.16 13.905 ;
     RECT  2.16 14.175 110.16 14.445 ;
     RECT  2.16 14.715 110.16 14.985 ;
     RECT  2.16 15.255 110.16 15.525 ;
     RECT  2.16 15.795 110.16 16.065 ;
     RECT  2.16 16.335 110.16 16.605 ;
     RECT  2.16 16.875 110.16 17.145 ;
     RECT  2.16 17.415 110.16 17.685 ;
     RECT  2.16 17.955 110.16 18.225 ;
     RECT  2.16 18.495 110.16 18.765 ;
     RECT  2.16 19.035 110.16 19.305 ;
     RECT  2.16 19.575 110.16 19.845 ;
     RECT  2.16 20.115 110.16 20.385 ;
     RECT  2.16 20.655 110.16 20.925 ;
     RECT  2.16 21.195 110.16 21.465 ;
     RECT  2.16 21.735 110.16 22.005 ;
     RECT  2.16 22.275 110.16 22.545 ;
     RECT  2.16 22.815 110.16 23.085 ;
     RECT  2.16 23.355 110.16 23.625 ;
     RECT  2.16 23.895 110.16 24.165 ;
     RECT  2.16 24.435 110.16 24.705 ;
     RECT  2.16 24.975 110.16 25.245 ;
     RECT  2.16 25.515 110.16 25.785 ;
     RECT  2.16 26.055 110.16 26.325 ;
     RECT  2.16 26.595 110.16 26.865 ;
     RECT  2.16 27.135 110.16 27.405 ;
     RECT  2.16 27.675 110.16 27.945 ;
     RECT  2.16 28.215 110.16 28.485 ;
     RECT  2.16 28.755 110.16 29.025 ;
     RECT  2.16 29.295 110.16 29.565 ;
     RECT  2.16 29.835 110.16 30.105 ;
     RECT  2.16 30.375 110.16 30.645 ;
     RECT  2.16 30.915 110.16 31.185 ;
     RECT  2.16 31.455 110.16 31.725 ;
     RECT  2.16 31.995 110.16 32.265 ;
     RECT  2.16 32.535 110.16 32.805 ;
     RECT  2.16 33.075 110.16 33.345 ;
     RECT  2.16 33.615 110.16 33.885 ;
     RECT  2.16 34.155 110.16 34.425 ;
     RECT  2.16 34.695 110.16 34.965 ;
     RECT  2.16 35.235 110.16 35.505 ;
     RECT  2.16 35.775 110.16 36.045 ;
     RECT  2.16 36.315 110.16 36.585 ;
     RECT  2.16 36.855 110.16 37.125 ;
     RECT  2.16 37.395 110.16 37.665 ;
     RECT  2.16 37.935 110.16 38.205 ;
     RECT  2.16 38.475 110.16 38.745 ;
     RECT  2.16 39.015 110.16 39.285 ;
     RECT  2.16 39.555 110.16 39.825 ;
     RECT  2.16 40.095 110.16 40.365 ;
     RECT  2.16 40.635 110.16 40.905 ;
     RECT  2.16 41.175 20.412 41.445 ;
     RECT  90.828 41.175 110.16 41.445 ;
     RECT  2.16 41.715 20.412 41.985 ;
     RECT  90.828 41.715 110.16 41.985 ;
     RECT  2.16 42.255 20.412 42.525 ;
     RECT  90.828 42.255 110.16 42.525 ;
     RECT  2.16 42.795 20.412 43.065 ;
     RECT  90.828 42.795 110.16 43.065 ;
     RECT  2.16 43.335 20.412 43.605 ;
     RECT  90.828 43.335 110.16 43.605 ;
     RECT  2.16 43.875 20.412 44.145 ;
     RECT  90.828 43.875 110.16 44.145 ;
     RECT  2.16 44.415 20.412 44.685 ;
     RECT  90.828 44.415 110.16 44.685 ;
     RECT  2.16 44.955 20.412 45.225 ;
     RECT  90.828 44.955 110.16 45.225 ;
     RECT  2.16 45.495 20.412 45.765 ;
     RECT  90.828 45.495 110.16 45.765 ;
     RECT  2.16 46.035 20.412 46.305 ;
     RECT  90.828 46.035 110.16 46.305 ;
     RECT  2.16 46.575 20.412 46.845 ;
     RECT  90.828 46.575 110.16 46.845 ;
     RECT  2.16 47.115 20.412 47.385 ;
     RECT  90.828 47.115 110.16 47.385 ;
     RECT  2.16 47.655 20.412 47.925 ;
     RECT  90.828 47.655 110.16 47.925 ;
     RECT  2.16 48.195 20.412 48.465 ;
     RECT  90.828 48.195 110.16 48.465 ;
     RECT  2.16 48.735 20.412 49.005 ;
     RECT  90.828 48.735 110.16 49.005 ;
     RECT  2.16 49.275 20.412 49.545 ;
     RECT  90.828 49.275 110.16 49.545 ;
     RECT  2.16 49.815 20.412 50.085 ;
     RECT  90.828 49.815 110.16 50.085 ;
     RECT  2.16 50.355 20.412 50.625 ;
     RECT  90.828 50.355 110.16 50.625 ;
     RECT  2.16 50.895 20.412 51.165 ;
     RECT  90.828 50.895 110.16 51.165 ;
     RECT  2.16 51.435 20.412 51.705 ;
     RECT  90.828 51.435 110.16 51.705 ;
     RECT  2.16 51.975 20.412 52.245 ;
     RECT  90.828 51.975 110.16 52.245 ;
     RECT  2.16 52.515 20.412 52.785 ;
     RECT  90.828 52.515 110.16 52.785 ;
     RECT  2.16 53.055 20.412 53.325 ;
     RECT  90.828 53.055 110.16 53.325 ;
     RECT  2.16 53.595 20.412 53.865 ;
     RECT  90.828 53.595 110.16 53.865 ;
     RECT  2.16 54.135 20.412 54.405 ;
     RECT  90.828 54.135 110.16 54.405 ;
     RECT  2.16 54.675 20.412 54.945 ;
     RECT  90.828 54.675 110.16 54.945 ;
     RECT  2.16 55.215 20.412 55.485 ;
     RECT  90.828 55.215 110.16 55.485 ;
     RECT  2.16 55.755 20.412 56.025 ;
     RECT  90.828 55.755 110.16 56.025 ;
     RECT  2.16 56.295 20.412 56.565 ;
     RECT  90.828 56.295 110.16 56.565 ;
     RECT  2.16 56.835 20.412 57.105 ;
     RECT  90.828 56.835 110.16 57.105 ;
     RECT  2.16 57.375 20.412 57.645 ;
     RECT  90.828 57.375 110.16 57.645 ;
     RECT  2.16 57.915 20.412 58.185 ;
     RECT  90.828 57.915 110.16 58.185 ;
     RECT  2.16 58.455 20.412 58.725 ;
     RECT  90.828 58.455 110.16 58.725 ;
     RECT  2.16 58.995 20.412 59.265 ;
     RECT  90.828 58.995 110.16 59.265 ;
     RECT  2.16 59.535 20.412 59.805 ;
     RECT  90.828 59.535 110.16 59.805 ;
     RECT  2.16 60.075 20.412 60.345 ;
     RECT  90.828 60.075 110.16 60.345 ;
     RECT  2.16 60.615 20.412 60.885 ;
     RECT  90.828 60.615 110.16 60.885 ;
     RECT  2.16 61.155 20.412 61.425 ;
     RECT  90.828 61.155 110.16 61.425 ;
     RECT  2.16 61.695 20.412 61.965 ;
     RECT  90.828 61.695 110.16 61.965 ;
     RECT  2.16 62.235 20.412 62.505 ;
     RECT  90.828 62.235 110.16 62.505 ;
    LAYER M1 ;
     RECT  2.16 2.151 110.16 41.049 ;
     RECT  22.464 43.2 88.776 61.032 ;
     RECT  2.16 41.049 20.412 62.649 ;
     RECT  90.828 41.049 110.16 62.649 ;
    LAYER M2 ;
     RECT  1.111 2.502 1.687 2.52 ;
     RECT  1.399 3.582 1.687 3.6 ;
     RECT  1.687 2.502 1.939 3.6 ;
     RECT  1.939 2.502 2.16 3.708 ;
     RECT  0.103 7.362 2.16 7.38 ;
     RECT  0.103 19.782 2.16 19.8 ;
     RECT  0.103 32.472 2.16 32.49 ;
     RECT  0.535 44.928 2.16 44.946 ;
     RECT  2.515 0.036 2.759 0.054 ;
     RECT  2.16 2.151 3.523 62.649 ;
     RECT  3.523 2.106 5.539 62.649 ;
     RECT  5.539 1.728 6.215 62.649 ;
     RECT  6.215 1.998 7.079 62.649 ;
     RECT  7.079 2.07 7.151 62.649 ;
     RECT  7.151 2.106 8.671 62.649 ;
     RECT  8.671 1.728 8.879 62.649 ;
     RECT  9.139 1.152 9.347 1.17 ;
     RECT  8.879 2.034 20.412 62.649 ;
     RECT  20.412 58.698 20.651 59.832 ;
     RECT  20.412 42.732 20.831 42.75 ;
     RECT  20.651 59.274 21.119 59.832 ;
     RECT  20.412 49.212 21.155 57.834 ;
     RECT  20.412 46.746 21.227 46.764 ;
     RECT  20.412 44.766 21.371 44.91 ;
     RECT  20.412 41.886 21.415 41.904 ;
     RECT  21.371 44.892 21.443 44.91 ;
     RECT  21.155 49.212 21.623 56.124 ;
     RECT  21.155 57.276 21.623 57.834 ;
     RECT  21.119 59.814 21.695 59.832 ;
     RECT  20.412 2.034 21.811 41.049 ;
     RECT  21.415 41.886 21.811 42.48 ;
     RECT  22.063 46.548 22.099 46.566 ;
     RECT  21.811 2.034 22.464 42.48 ;
     RECT  22.099 46.548 22.464 46.719 ;
     RECT  21.623 49.212 22.464 51.732 ;
     RECT  21.623 52.686 22.464 53.244 ;
     RECT  21.623 54.414 22.464 54.432 ;
     RECT  21.623 56.034 22.464 56.124 ;
     RECT  22.464 2.034 24.007 61.032 ;
     RECT  24.007 1.728 24.251 61.032 ;
     RECT  24.251 2.106 24.359 61.032 ;
     RECT  24.359 2.151 26.779 61.032 ;
     RECT  26.779 0.036 26.879 0.054 ;
     RECT  26.779 2.106 33.647 61.032 ;
     RECT  33.647 41.886 39.659 61.032 ;
     RECT  40.171 0.036 40.307 0.054 ;
     RECT  33.647 2.106 41.323 41.049 ;
     RECT  39.659 42.462 41.387 61.032 ;
     RECT  41.323 2.07 42.223 41.049 ;
     RECT  42.223 1.728 42.395 41.049 ;
     RECT  42.395 2.106 47.615 41.049 ;
     RECT  51.727 0.036 51.827 0.054 ;
     RECT  55.651 0.036 55.751 0.054 ;
     RECT  47.615 2.151 57.559 41.049 ;
     RECT  57.559 1.728 57.695 41.049 ;
     RECT  57.695 2.151 58.495 41.049 ;
     RECT  58.495 1.728 58.703 41.049 ;
     RECT  58.703 2.151 59.863 41.049 ;
     RECT  59.863 1.728 60.863 41.049 ;
     RECT  61.735 0.036 61.835 0.054 ;
     RECT  76.963 0.036 77.135 0.054 ;
     RECT  60.863 2.151 77.575 41.049 ;
     RECT  78.079 0.036 78.179 0.054 ;
     RECT  77.575 1.728 78.467 41.049 ;
     RECT  78.467 2.151 81.499 41.049 ;
     RECT  82.363 0.036 83.011 0.054 ;
     RECT  83.011 0.036 84.595 0.09 ;
     RECT  84.595 0.036 85.927 0.126 ;
     RECT  87.187 41.886 87.259 41.904 ;
     RECT  41.387 43.2 87.259 61.032 ;
     RECT  87.259 41.886 88.776 61.032 ;
     RECT  81.499 1.422 89.411 41.049 ;
     RECT  85.927 0.036 89.951 0.162 ;
     RECT  89.951 0.108 90.527 0.162 ;
     RECT  88.776 49.482 90.607 49.5 ;
     RECT  88.776 50.562 90.607 51.732 ;
     RECT  90.175 46.746 90.643 46.764 ;
     RECT  88.776 58.392 90.643 58.644 ;
     RECT  88.776 59.472 90.643 60.174 ;
     RECT  89.411 2.07 90.671 41.049 ;
     RECT  90.671 2.106 90.707 41.049 ;
     RECT  89.815 53.298 90.715 53.316 ;
     RECT  90.527 0.144 90.779 0.162 ;
     RECT  90.707 2.151 90.828 41.049 ;
     RECT  88.776 41.886 90.828 42.48 ;
     RECT  90.643 46.746 90.828 46.836 ;
     RECT  90.607 48.78 90.828 49.5 ;
     RECT  90.607 50.4 90.828 51.804 ;
     RECT  90.715 53.028 90.828 53.316 ;
     RECT  90.247 54.414 90.828 54.432 ;
     RECT  88.776 56.106 90.828 56.124 ;
     RECT  90.607 56.88 90.828 56.898 ;
     RECT  90.643 58.392 90.828 60.174 ;
     RECT  91.867 0.036 92.651 0.054 ;
     RECT  92.695 1.152 92.795 1.17 ;
     RECT  94.063 0.036 95.747 0.054 ;
     RECT  96.835 0.576 97.915 0.594 ;
     RECT  97.915 0.036 98.015 0.594 ;
     RECT  90.828 2.151 98.167 62.649 ;
     RECT  98.015 0.576 98.375 0.594 ;
     RECT  98.167 2.106 100.031 62.649 ;
     RECT  100.031 2.151 101.803 62.649 ;
     RECT  101.803 2.106 102.955 62.649 ;
     RECT  102.955 2.034 104.279 62.649 ;
     RECT  104.279 2.106 104.459 62.649 ;
     RECT  104.459 2.151 107.383 62.649 ;
     RECT  107.383 1.728 107.627 62.649 ;
     RECT  107.023 0.036 107.807 0.054 ;
     RECT  109.507 0.036 109.643 0.054 ;
     RECT  107.627 2.151 110.16 62.649 ;
     RECT  110.16 2.574 110.363 4.212 ;
     RECT  110.363 2.808 110.543 4.212 ;
     RECT  110.16 23.562 110.579 23.58 ;
     RECT  110.16 34.902 110.579 34.92 ;
     RECT  110.16 40.068 110.579 40.086 ;
     RECT  110.16 41.382 110.579 41.4 ;
     RECT  110.16 44.082 110.579 44.1 ;
     RECT  110.16 52.992 110.579 53.01 ;
     RECT  110.16 57.996 110.579 58.014 ;
     RECT  110.16 16.956 110.615 16.974 ;
     RECT  110.16 19.512 110.615 19.53 ;
     RECT  110.16 21.942 110.615 21.96 ;
     RECT  110.16 29.772 110.615 29.79 ;
     RECT  110.16 33.552 110.615 33.57 ;
     RECT  110.16 48.942 110.615 48.96 ;
     RECT  110.16 7.056 110.651 7.92 ;
     RECT  110.543 3.312 110.903 4.212 ;
     RECT  110.903 3.654 111.155 4.212 ;
     RECT  110.16 9.324 111.155 9.342 ;
     RECT  110.16 11.952 111.155 11.97 ;
     RECT  110.16 14.454 111.155 14.472 ;
     RECT  110.16 15.768 111.155 15.786 ;
     RECT  110.16 18.432 111.155 18.45 ;
     RECT  110.16 20.862 111.155 20.88 ;
     RECT  110.16 24.912 111.155 24.93 ;
     RECT  110.16 25.992 111.155 26.01 ;
     RECT  110.16 27.342 111.155 27.36 ;
     RECT  110.16 31.23 111.155 31.248 ;
     RECT  110.16 32.472 111.155 32.49 ;
     RECT  110.16 37.602 111.155 37.62 ;
     RECT  110.16 42.732 111.155 42.75 ;
     RECT  110.16 47.862 111.155 47.88 ;
     RECT  110.16 50.364 111.155 50.382 ;
     RECT  110.16 51.642 111.155 51.66 ;
     RECT  110.16 54.342 111.155 54.36 ;
     RECT  110.16 56.772 111.155 56.79 ;
     RECT  110.16 59.472 111.155 59.49 ;
     RECT  110.16 62.208 111.155 62.298 ;
     RECT  111.155 3.654 111.191 3.708 ;
     RECT  110.651 7.2 111.191 7.92 ;
     RECT  110.16 13.068 111.191 13.086 ;
     RECT  110.16 28.458 111.191 28.476 ;
     RECT  110.16 38.718 111.731 38.736 ;
     RECT  111.191 3.654 112.235 3.672 ;
     RECT  110.16 5.742 112.235 5.76 ;
     RECT  110.16 36.522 112.235 36.54 ;
     RECT  111.155 62.208 112.235 62.226 ;
    LAYER M3 ;
     RECT  51.804 0.012 51.822 0.031 ;
     RECT  89.388 0.012 97.938 0.031 ;
     RECT  82.368 0.031 82.386 0.067 ;
     RECT  1.116 0.012 9.702 0.077 ;
     RECT  71.748 0.012 80.298 0.091 ;
     RECT  82.368 0.067 83.034 0.091 ;
     RECT  107.028 0.012 111.186 0.091 ;
     RECT  89.388 0.031 98.01 0.095 ;
     RECT  50.58 0.012 50.598 0.125 ;
     RECT  28.476 0.091 28.926 0.139 ;
     RECT  104.04 0.091 104.706 0.139 ;
     RECT  105.552 0.091 111.186 0.139 ;
     RECT  90.216 0.095 98.01 0.167 ;
     RECT  99.936 0.091 100.17 0.475 ;
     RECT  103.068 0.091 103.086 0.523 ;
     RECT  104.04 0.139 111.186 0.523 ;
     RECT  85.932 0.139 85.95 0.571 ;
     RECT  91.044 0.167 98.01 0.571 ;
     RECT  98.892 0.091 98.91 0.571 ;
     RECT  99.936 0.475 100.746 0.571 ;
     RECT  28.476 0.139 29.214 1.099 ;
     RECT  5.256 0.077 9.702 1.147 ;
     RECT  15.264 0.571 15.642 1.147 ;
     RECT  28.476 1.099 29.574 1.147 ;
     RECT  46.152 0.571 46.17 1.147 ;
     RECT  47.7 0.571 47.718 1.147 ;
     RECT  71.748 0.091 80.946 1.147 ;
     RECT  102.276 0.091 102.294 1.147 ;
     RECT  103.068 0.523 111.186 1.147 ;
     RECT  88.38 1.147 88.398 1.195 ;
     RECT  71.748 1.147 81.054 1.417 ;
     RECT  89.388 0.095 89.406 1.445 ;
     RECT  5.256 1.147 10.854 1.723 ;
     RECT  12.024 1.147 12.042 1.723 ;
     RECT  13.356 1.147 13.374 1.723 ;
     RECT  14.652 1.147 15.642 1.723 ;
     RECT  16.488 0.571 16.506 1.723 ;
     RECT  17.424 0.571 17.442 1.723 ;
     RECT  18.792 0.012 27.342 1.723 ;
     RECT  28.476 1.147 30.222 1.723 ;
     RECT  31.248 1.675 31.266 1.723 ;
     RECT  32.76 1.675 32.778 1.723 ;
     RECT  34.056 0.571 34.074 1.723 ;
     RECT  36.432 0.012 44.982 1.723 ;
     RECT  46.152 1.147 46.278 1.723 ;
     RECT  47.7 1.147 48.474 1.723 ;
     RECT  51.732 0.031 51.822 1.723 ;
     RECT  52.632 1.147 53.082 1.723 ;
     RECT  54.072 0.012 62.658 1.723 ;
     RECT  63.9 1.147 63.918 1.723 ;
     RECT  64.836 0.571 65.43 1.723 ;
     RECT  67.752 0.571 68.346 1.723 ;
     RECT  70.776 1.147 70.794 1.723 ;
     RECT  71.748 1.417 81.522 1.723 ;
     RECT  82.368 0.091 83.646 1.723 ;
     RECT  84.6 0.103 84.618 1.723 ;
     RECT  85.824 0.571 86.562 1.723 ;
     RECT  88.308 1.195 88.398 1.723 ;
     RECT  14.4 1.723 48.546 1.771 ;
     RECT  49.392 1.723 51.822 1.771 ;
     RECT  53.928 1.723 67.014 1.771 ;
     RECT  67.752 1.723 88.398 1.771 ;
     RECT  53.928 1.771 88.398 1.819 ;
     RECT  89.244 1.723 89.262 1.819 ;
     RECT  90.216 0.167 90.234 2.065 ;
     RECT  91.044 0.571 100.782 2.065 ;
     RECT  5.256 1.723 13.374 2.101 ;
     RECT  4.968 2.101 13.374 2.191 ;
     RECT  14.4 1.771 51.822 2.191 ;
     RECT  52.632 1.723 53.19 2.191 ;
     RECT  90.216 2.065 100.782 2.191 ;
     RECT  101.7 1.147 111.186 2.191 ;
     RECT  1.116 0.077 3.618 2.227 ;
     RECT  1.116 2.227 4.158 2.263 ;
     RECT  4.968 2.191 53.19 2.263 ;
     RECT  53.928 1.819 89.262 2.263 ;
     RECT  90.216 2.191 111.186 2.263 ;
     RECT  1.116 2.263 111.186 2.525 ;
     RECT  1.404 2.525 111.186 3.605 ;
     RECT  112.212 2.923 112.23 3.677 ;
     RECT  1.944 3.605 111.186 3.713 ;
     RECT  2.34 3.713 111.15 4.217 ;
     RECT  2.34 4.217 110.646 5.069 ;
     RECT  2.34 5.069 86.994 5.369 ;
     RECT  112.212 5.467 112.23 5.765 ;
     RECT  2.376 5.369 86.994 6.035 ;
     RECT  87.768 5.069 110.646 6.151 ;
     RECT  87.48 6.151 110.646 6.763 ;
     RECT  2.376 6.035 86.382 6.889 ;
     RECT  87.48 6.763 111.186 6.889 ;
     RECT  2.376 6.889 111.186 7.079 ;
     RECT  0.108 7.243 0.126 7.385 ;
     RECT  2.376 7.079 110.106 7.763 ;
     RECT  111.168 7.079 111.186 8.045 ;
     RECT  2.376 7.763 110.034 8.969 ;
     RECT  2.412 8.969 110.034 9.293 ;
     RECT  111.132 9.307 111.15 9.347 ;
     RECT  2.415 9.293 110.034 10.085 ;
     RECT  109.728 10.085 110.034 10.603 ;
     RECT  109.728 10.603 110.07 10.733 ;
     RECT  2.415 10.085 108.918 10.975 ;
     RECT  2.412 10.975 108.918 11.021 ;
     RECT  2.415 11.021 108.918 11.371 ;
     RECT  109.728 10.733 110.034 11.371 ;
     RECT  2.415 11.371 110.034 11.849 ;
     RECT  111.132 11.899 111.15 11.975 ;
     RECT  2.415 11.849 109.746 11.983 ;
     RECT  111.168 13.063 111.186 13.181 ;
     RECT  2.34 11.983 109.746 13.289 ;
     RECT  2.34 13.289 108.882 13.661 ;
     RECT  2.415 13.661 108.882 14.099 ;
     RECT  15.912 14.099 108.882 14.251 ;
     RECT  109.728 13.289 109.746 14.251 ;
     RECT  111.132 14.44 111.15 14.477 ;
     RECT  15.912 14.251 109.746 14.711 ;
     RECT  2.415 14.099 14.958 14.747 ;
     RECT  2.415 14.747 13.77 14.783 ;
     RECT  109.728 14.711 109.746 14.819 ;
     RECT  15.912 14.711 108.882 14.909 ;
     RECT  14.508 14.747 14.958 14.917 ;
     RECT  15.912 14.909 108.81 14.917 ;
     RECT  14.508 14.917 108.81 14.945 ;
     RECT  98.352 14.945 108.81 15.089 ;
     RECT  2.415 14.783 13.662 15.529 ;
     RECT  14.508 14.945 97.614 15.529 ;
     RECT  109.692 15.529 109.71 15.719 ;
     RECT  111.132 15.739 111.15 15.791 ;
     RECT  2.415 15.529 97.614 15.827 ;
     RECT  15.912 15.827 97.614 15.835 ;
     RECT  98.388 15.089 108.81 15.835 ;
     RECT  15.912 15.835 108.81 15.899 ;
     RECT  31.572 15.899 108.774 15.989 ;
     RECT  2.415 15.827 15.102 16.061 ;
     RECT  31.572 15.989 108.702 16.097 ;
     RECT  2.415 16.061 15.066 16.501 ;
     RECT  15.912 15.899 30.834 16.651 ;
     RECT  31.572 16.097 108.666 16.651 ;
     RECT  110.592 16.951 110.61 17.021 ;
     RECT  109.8 16.951 109.818 17.077 ;
     RECT  2.376 16.501 15.066 17.105 ;
     RECT  109.8 17.077 109.998 17.105 ;
     RECT  2.415 17.105 15.066 17.113 ;
     RECT  15.912 16.651 108.666 17.113 ;
     RECT  109.98 17.105 109.998 17.339 ;
     RECT  2.415 17.113 108.666 17.453 ;
     RECT  21.78 17.453 108.666 17.491 ;
     RECT  21.78 17.491 109.134 18.031 ;
     RECT  21.78 18.031 109.386 18.149 ;
     RECT  2.415 17.453 21.006 18.193 ;
     RECT  21.78 18.149 108.954 18.193 ;
     RECT  111.132 18.283 111.15 18.455 ;
     RECT  2.415 18.193 108.954 19.277 ;
     RECT  16.524 19.277 108.954 19.381 ;
     RECT  110.592 19.507 110.61 19.613 ;
     RECT  16.524 19.381 108.99 19.849 ;
     RECT  0.108 19.777 0.126 19.853 ;
     RECT  16.524 19.849 109.026 19.921 ;
     RECT  16.524 19.921 109.098 20.039 ;
     RECT  2.415 19.277 15.678 20.119 ;
     RECT  16.524 20.039 108.846 20.119 ;
     RECT  2.415 20.119 108.846 20.849 ;
     RECT  14.472 20.849 108.846 20.872 ;
     RECT  111.132 20.827 111.15 20.885 ;
     RECT  2.415 20.849 13.662 21.469 ;
     RECT  2.34 21.469 13.662 21.631 ;
     RECT  14.508 20.872 108.846 21.631 ;
     RECT  2.34 21.631 108.846 21.965 ;
     RECT  2.412 21.965 108.846 22.013 ;
     RECT  110.592 21.937 110.61 22.157 ;
     RECT  2.415 22.013 108.846 22.205 ;
     RECT  16.74 22.205 108.846 22.711 ;
     RECT  2.415 22.205 15.93 23.125 ;
     RECT  16.74 22.711 109.17 23.125 ;
     RECT  2.415 23.125 109.17 23.153 ;
     RECT  2.415 23.153 108.954 23.279 ;
     RECT  110.556 23.419 110.574 23.585 ;
     RECT  2.415 23.279 108.81 23.819 ;
     RECT  3.636 23.819 108.81 23.855 ;
     RECT  4.14 23.855 108.81 23.891 ;
     RECT  4.356 23.891 108.81 24.359 ;
     RECT  5.112 24.359 108.81 24.467 ;
     RECT  5.112 24.467 5.13 24.503 ;
     RECT  4.356 24.359 4.374 24.509 ;
     RECT  5.976 24.467 108.81 24.665 ;
     RECT  6.3 24.665 108.81 24.781 ;
     RECT  6.3 24.781 109.098 24.809 ;
     RECT  111.132 24.715 111.15 24.935 ;
     RECT  6.732 24.809 109.098 25.051 ;
     RECT  6.732 25.051 109.458 25.411 ;
     RECT  6.732 25.411 109.566 25.979 ;
     RECT  6.732 25.979 109.458 26.015 ;
     RECT  111.132 25.963 111.15 26.015 ;
     RECT  6.732 26.015 108.738 26.401 ;
     RECT  6.588 26.401 108.738 26.669 ;
     RECT  7.056 26.669 108.738 27.211 ;
     RECT  7.056 27.211 108.918 27.301 ;
     RECT  109.944 27.211 109.962 27.329 ;
     RECT  7.056 27.301 108.99 27.365 ;
     RECT  111.132 27.259 111.15 27.365 ;
     RECT  102.852 27.365 108.99 27.913 ;
     RECT  102.852 27.913 109.134 28.147 ;
     RECT  102.852 28.147 109.278 28.219 ;
     RECT  102.816 28.219 109.278 28.291 ;
     RECT  7.056 27.365 101.79 28.411 ;
     RECT  102.708 28.291 109.314 28.453 ;
     RECT  7.056 28.411 101.97 28.481 ;
     RECT  111.168 28.453 111.186 28.589 ;
     RECT  102.708 28.453 109.422 28.679 ;
     RECT  102.708 28.679 109.278 28.715 ;
     RECT  102.708 28.715 108.594 28.723 ;
     RECT  7.056 28.481 101.538 28.832 ;
     RECT  102.348 28.723 108.594 29.419 ;
     RECT  7.056 28.832 101.286 29.731 ;
     RECT  7.056 29.731 101.43 29.803 ;
     RECT  102.204 29.419 108.594 29.803 ;
     RECT  110.592 29.767 110.61 29.837 ;
     RECT  109.944 29.911 109.962 30.029 ;
     RECT  7.056 29.803 108.594 30.137 ;
     RECT  104.94 30.137 108.594 30.335 ;
     RECT  7.056 30.137 104.13 30.605 ;
     RECT  99.615 30.605 104.13 30.641 ;
     RECT  103.356 30.641 104.13 30.713 ;
     RECT  99.615 30.641 102.618 30.749 ;
     RECT  104.94 30.335 107.478 30.749 ;
     RECT  101.376 30.749 102.618 30.797 ;
     RECT  99.615 30.749 100.386 30.839 ;
     RECT  101.376 30.797 101.718 30.839 ;
     RECT  101.376 30.839 101.61 30.911 ;
     RECT  103.68 30.713 104.13 30.919 ;
     RECT  104.94 30.749 105.894 30.919 ;
     RECT  99.615 30.839 100.35 30.983 ;
     RECT  102.6 30.797 102.618 30.983 ;
     RECT  106.668 30.749 107.478 30.983 ;
     RECT  108.432 30.335 108.594 30.991 ;
     RECT  7.056 30.605 98.874 31.019 ;
     RECT  99.615 30.983 100.206 31.019 ;
     RECT  103.68 30.919 105.894 31.109 ;
     RECT  109.836 30.919 109.854 31.109 ;
     RECT  101.484 30.911 101.61 31.145 ;
     RECT  7.056 31.019 95.598 31.181 ;
     RECT  96.336 31.019 98.874 31.181 ;
     RECT  108.432 30.991 108.702 31.181 ;
     RECT  85.968 31.181 95.598 31.187 ;
     RECT  104.976 31.109 105.426 31.217 ;
     RECT  86.076 31.187 95.598 31.253 ;
     RECT  101.556 31.145 101.574 31.253 ;
     RECT  111.132 31.099 111.15 31.253 ;
     RECT  7.056 31.181 81.27 31.289 ;
     RECT  96.336 31.181 98.01 31.289 ;
     RECT  98.856 31.181 98.874 31.289 ;
     RECT  80.46 31.289 81.27 31.379 ;
     RECT  86.58 31.253 95.598 31.415 ;
     RECT  86.58 31.415 89.097 31.487 ;
     RECT  96.336 31.289 97.722 31.523 ;
     RECT  80.532 31.379 81.27 31.559 ;
     RECT  80.712 31.559 81.27 31.649 ;
     RECT  82.152 31.181 84.834 31.649 ;
     RECT  7.056 31.289 79.578 31.685 ;
     RECT  80.964 31.649 81.27 31.685 ;
     RECT  82.152 31.649 84.726 31.685 ;
     RECT  7.056 31.685 79.218 31.757 ;
     RECT  80.964 31.685 80.982 31.757 ;
     RECT  82.152 31.685 84.006 31.757 ;
     RECT  82.152 31.757 83.754 31.793 ;
     RECT  82.152 31.793 83.697 31.919 ;
     RECT  86.652 31.487 89.097 31.919 ;
     RECT  82.872 31.919 83.697 31.955 ;
     RECT  88.272 31.919 89.097 31.991 ;
     RECT  89.82 31.415 95.598 32.063 ;
     RECT  106.668 30.983 107.442 32.269 ;
     RECT  108.432 31.181 108.594 32.269 ;
     RECT  96.336 31.523 97.506 32.297 ;
     RECT  103.68 31.109 104.022 32.305 ;
     RECT  7.056 31.757 79.146 32.333 ;
     RECT  106.668 32.269 109.206 32.369 ;
     RECT  7.056 32.333 78.894 32.459 ;
     RECT  107.424 32.369 109.206 32.459 ;
     RECT  5.688 32.431 5.706 32.491 ;
     RECT  0.108 32.395 0.126 32.495 ;
     RECT  7.815 32.459 78.894 32.495 ;
     RECT  111.132 32.395 111.15 32.495 ;
     RECT  107.424 32.459 108.594 32.531 ;
     RECT  5.688 32.491 5.886 32.539 ;
     RECT  7.056 32.459 7.074 32.539 ;
     RECT  5.688 32.539 7.074 32.729 ;
     RECT  4.788 32.431 4.806 32.765 ;
     RECT  76.356 32.495 78.894 32.765 ;
     RECT  6.408 32.729 7.074 32.999 ;
     RECT  105.015 31.217 105.426 33.071 ;
     RECT  7.815 32.495 75.474 33.277 ;
     RECT  76.356 32.765 78.714 33.277 ;
     RECT  7.815 33.277 78.714 33.547 ;
     RECT  108.36 32.531 108.594 33.583 ;
     RECT  106.668 32.369 106.686 33.619 ;
     RECT  107.424 32.531 107.442 33.619 ;
     RECT  108.288 33.583 108.594 33.619 ;
     RECT  110.592 33.547 110.61 33.677 ;
     RECT  106.2 33.619 106.686 33.691 ;
     RECT  107.424 33.619 108.594 33.691 ;
     RECT  106.2 33.691 108.594 33.809 ;
     RECT  7.668 33.547 78.714 33.817 ;
     RECT  108.288 33.809 108.594 33.881 ;
     RECT  105.015 33.071 105.354 33.889 ;
     RECT  106.2 33.809 107.442 33.889 ;
     RECT  96.336 32.297 97.434 33.917 ;
     RECT  105.015 33.889 107.442 33.965 ;
     RECT  7.668 33.817 78.93 34.051 ;
     RECT  7.596 34.051 78.93 34.151 ;
     RECT  7.668 34.151 78.93 34.259 ;
     RECT  7.668 34.259 78.642 34.397 ;
     RECT  106.596 33.965 107.442 34.771 ;
     RECT  7.815 34.397 78.642 34.889 ;
     RECT  7.815 34.889 78.57 34.925 ;
     RECT  105.015 33.965 105.354 34.933 ;
     RECT  106.092 34.771 107.442 34.933 ;
     RECT  79.38 34.501 79.398 34.961 ;
     RECT  110.556 34.897 110.574 34.973 ;
     RECT  105.015 34.933 107.442 35.041 ;
     RECT  108.36 33.881 108.594 35.041 ;
     RECT  109.404 35.041 109.422 35.159 ;
     RECT  7.815 34.925 78.534 35.195 ;
     RECT  93.312 32.063 95.598 35.267 ;
     RECT  105.015 35.041 108.594 35.537 ;
     RECT  7.815 35.195 9.486 35.744 ;
     RECT  7.815 35.744 8.55 35.885 ;
     RECT  10.26 35.195 78.534 35.969 ;
     RECT  76.752 35.969 78.534 36.085 ;
     RECT  9.396 35.744 9.486 36.283 ;
     RECT  10.26 35.969 76.014 36.283 ;
     RECT  105.015 35.537 106.686 36.391 ;
     RECT  103.428 32.305 104.022 36.517 ;
     RECT  104.76 36.391 106.686 36.517 ;
     RECT  9.396 36.283 76.014 36.545 ;
     RECT  103.428 36.517 106.686 36.545 ;
     RECT  112.212 36.235 112.23 36.545 ;
     RECT  107.748 35.537 108.594 36.661 ;
     RECT  104.976 36.545 106.686 36.779 ;
     RECT  107.748 36.661 108.99 36.815 ;
     RECT  76.752 36.085 78.75 36.895 ;
     RECT  9.432 36.545 76.014 36.931 ;
     RECT  76.752 36.895 78.966 36.931 ;
     RECT  103.428 36.545 104.202 36.959 ;
     RECT  9.432 36.931 78.966 37.049 ;
     RECT  107.748 36.815 108.954 37.579 ;
     RECT  9.432 37.049 78.297 37.589 ;
     RECT  107.64 37.579 108.954 37.625 ;
     RECT  111.132 37.531 111.15 37.625 ;
     RECT  9.432 37.589 76.95 37.633 ;
     RECT  108.36 37.625 108.954 37.741 ;
     RECT  9.324 37.633 76.95 37.769 ;
     RECT  9.324 37.769 76.626 37.859 ;
     RECT  77.976 37.589 78.297 37.895 ;
     RECT  108.36 37.741 109.206 38.003 ;
     RECT  9.324 37.859 76.518 38.129 ;
     RECT  108.36 38.003 108.594 38.201 ;
     RECT  9.432 38.129 75.366 38.399 ;
     RECT  76.14 38.129 76.518 38.399 ;
     RECT  9.432 38.399 74.898 38.435 ;
     RECT  10.044 38.435 74.898 38.507 ;
     RECT  10.044 38.507 70.218 38.669 ;
     RECT  71.208 38.507 74.898 38.669 ;
     RECT  71.208 38.669 74.79 38.705 ;
     RECT  108.36 38.201 108.45 38.713 ;
     RECT  71.208 38.705 74.754 38.717 ;
     RECT  15.408 38.669 41.886 38.728 ;
     RECT  15.408 38.728 41.67 38.741 ;
     RECT  106.668 36.779 106.686 38.749 ;
     RECT  74.16 38.717 74.754 38.813 ;
     RECT  111.708 38.713 111.726 38.813 ;
     RECT  105.015 36.779 105.714 38.821 ;
     RECT  106.668 38.749 107.01 38.821 ;
     RECT  107.784 38.713 108.45 38.849 ;
     RECT  74.16 38.813 74.574 38.939 ;
     RECT  10.044 38.669 14.634 38.975 ;
     RECT  71.208 38.717 73.206 38.975 ;
     RECT  74.16 38.939 74.502 38.975 ;
     RECT  105.015 38.821 107.01 39.047 ;
     RECT  107.784 38.849 108.378 39.091 ;
     RECT  71.208 38.975 73.026 39.119 ;
     RECT  105.015 39.047 106.938 39.149 ;
     RECT  106.596 39.149 106.938 39.209 ;
     RECT  10.08 38.975 14.634 39.245 ;
     RECT  15.408 38.741 15.858 39.245 ;
     RECT  56.415 38.669 70.218 39.245 ;
     RECT  71.208 39.119 72.954 39.245 ;
     RECT  15.408 39.245 15.606 39.281 ;
     RECT  106.596 39.209 106.614 39.281 ;
     RECT  107.676 39.091 108.378 39.281 ;
     RECT  71.208 39.245 71.622 39.289 ;
     RECT  72.396 39.245 72.954 39.317 ;
     RECT  74.16 38.975 74.178 39.317 ;
     RECT  105.015 39.149 105.714 39.325 ;
     RECT  71.136 39.289 71.622 39.341 ;
     RECT  71.424 39.341 71.442 39.353 ;
     RECT  72.615 39.317 72.954 39.353 ;
     RECT  103.428 36.959 104.022 39.353 ;
     RECT  56.415 39.245 59.058 39.479 ;
     RECT  59.868 39.245 70.218 39.479 ;
     RECT  10.8 39.245 14.634 39.487 ;
     RECT  15.408 39.281 15.498 39.487 ;
     RECT  42.768 38.669 55.674 39.487 ;
     RECT  56.415 39.479 59.022 39.487 ;
     RECT  42.768 39.487 59.022 39.523 ;
     RECT  42.732 39.523 59.022 39.551 ;
     RECT  10.8 39.487 15.498 39.587 ;
     RECT  16.596 38.741 41.67 39.595 ;
     RECT  10.8 39.587 11.322 39.659 ;
     RECT  16.596 39.595 41.958 39.749 ;
     RECT  59.868 39.479 70.146 39.749 ;
     RECT  30.708 39.749 41.958 39.785 ;
     RECT  52.812 39.551 59.022 39.785 ;
     RECT  59.868 39.749 68.49 39.785 ;
     RECT  16.596 39.749 29.934 39.821 ;
     RECT  32.436 39.785 41.958 39.857 ;
     RECT  52.812 39.785 56.697 39.869 ;
     RECT  59.868 39.785 67.986 39.869 ;
     RECT  12.492 39.587 15.498 39.893 ;
     RECT  16.596 39.821 29.862 39.893 ;
     RECT  32.436 39.857 33.966 39.893 ;
     RECT  59.868 39.869 67.497 39.893 ;
     RECT  32.58 39.893 33.966 39.917 ;
     RECT  14.616 39.893 15.498 39.929 ;
     RECT  59.868 39.893 65.646 40.019 ;
     RECT  69.228 39.749 70.146 40.019 ;
     RECT  104.976 39.325 105.714 40.019 ;
     RECT  34.776 39.857 41.958 40.027 ;
     RECT  42.732 39.551 52.074 40.027 ;
     RECT  16.596 39.893 29.826 40.055 ;
     RECT  57.564 39.785 59.022 40.055 ;
     RECT  13.215 39.893 13.806 40.091 ;
     RECT  110.556 40.063 110.574 40.109 ;
     RECT  104.004 39.353 104.022 40.123 ;
     RECT  104.976 40.019 105.462 40.123 ;
     RECT  16.668 40.055 29.826 40.127 ;
     RECT  57.564 40.055 57.582 40.127 ;
     RECT  10.8 39.659 10.818 40.199 ;
     RECT  52.812 39.869 53.226 40.199 ;
     RECT  16.668 40.127 27.054 40.289 ;
     RECT  27.936 40.127 29.826 40.289 ;
     RECT  52.812 40.199 53.01 40.289 ;
     RECT  69.912 40.019 70.146 40.289 ;
     RECT  69.912 40.289 69.93 40.325 ;
     RECT  58.32 40.055 59.022 40.333 ;
     RECT  59.868 40.019 59.958 40.333 ;
     RECT  16.668 40.289 26.874 40.349 ;
     RECT  27.936 40.289 29.79 40.349 ;
     RECT  66.456 39.893 67.497 40.349 ;
     RECT  52.812 40.289 52.938 40.361 ;
     RECT  60.768 40.019 63.378 40.361 ;
     RECT  64.26 40.019 65.646 40.361 ;
     RECT  104.004 40.123 105.462 40.361 ;
     RECT  106.74 40.171 106.758 40.361 ;
     RECT  28.296 40.349 29.79 40.397 ;
     RECT  60.984 40.361 63.378 40.397 ;
     RECT  17.316 40.349 17.694 40.433 ;
     RECT  34.776 40.027 52.074 40.433 ;
     RECT  44.64 40.433 52.074 40.441 ;
     RECT  18.468 40.349 26.874 40.445 ;
     RECT  44.64 40.441 52.434 40.445 ;
     RECT  18.468 40.445 26.01 40.469 ;
     RECT  26.784 40.445 26.874 40.469 ;
     RECT  45.288 40.445 48.186 40.469 ;
     RECT  105.015 40.361 105.462 40.469 ;
     RECT  49.32 40.445 52.434 40.493 ;
     RECT  54.288 39.869 56.697 40.555 ;
     RECT  17.604 40.433 17.694 40.559 ;
     RECT  30.708 39.785 31.482 40.559 ;
     RECT  39.06 40.433 43.398 40.559 ;
     RECT  49.32 40.493 51.93 40.559 ;
     RECT  106.56 40.441 106.578 40.559 ;
     RECT  60.984 40.397 63.018 40.589 ;
     RECT  14.616 39.929 15.462 40.595 ;
     RECT  17.604 40.559 17.622 40.595 ;
     RECT  28.764 40.397 29.79 40.595 ;
     RECT  34.776 40.433 38.322 40.595 ;
     RECT  49.32 40.559 51.858 40.595 ;
     RECT  54.288 40.555 57.222 40.595 ;
     RECT  64.26 40.361 65.106 40.595 ;
     RECT  18.615 40.469 26.01 40.631 ;
     RECT  49.32 40.595 51.297 40.631 ;
     RECT  32.58 39.917 33.642 40.639 ;
     RECT  34.776 40.595 35.73 40.639 ;
     RECT  39.06 40.559 40.497 40.667 ;
     RECT  49.608 40.631 51.297 40.667 ;
     RECT  32.4 40.639 33.642 40.675 ;
     RECT  34.74 40.639 35.73 40.675 ;
     RECT  54.288 40.595 56.697 40.685 ;
     RECT  18.615 40.631 24.297 40.703 ;
     RECT  45.615 40.469 48.186 40.703 ;
     RECT  13.215 40.091 13.698 40.739 ;
     RECT  25.164 40.631 26.01 40.739 ;
     RECT  32.4 40.675 35.73 40.739 ;
     RECT  36.72 40.595 38.25 40.739 ;
     RECT  50.076 40.667 51.297 40.739 ;
     RECT  54.396 40.685 56.697 40.739 ;
     RECT  66.456 40.349 66.474 40.739 ;
     RECT  19.62 40.703 24.297 40.787 ;
     RECT  32.4 40.739 35.097 40.787 ;
     RECT  39.636 40.667 40.497 40.787 ;
     RECT  50.796 40.739 51.297 40.787 ;
     RECT  55.368 40.739 56.697 40.787 ;
     RECT  67.215 40.349 67.497 40.787 ;
     RECT  72.615 39.353 72.897 40.787 ;
     RECT  78.015 37.895 78.297 40.787 ;
     RECT  83.415 31.955 83.697 40.787 ;
     RECT  88.815 31.991 89.097 40.787 ;
     RECT  32.4 40.787 34.974 40.795 ;
     RECT  15.3 40.595 15.462 40.829 ;
     RECT  30.6 40.675 30.618 40.829 ;
     RECT  31.356 40.559 31.482 40.829 ;
     RECT  32.328 40.795 34.974 40.829 ;
     RECT  42.264 40.559 43.398 40.829 ;
     RECT  45.615 40.703 47.466 40.829 ;
     RECT  54.396 40.739 54.63 40.829 ;
     RECT  55.368 40.787 56.505 40.829 ;
     RECT  58.32 40.333 59.958 40.829 ;
     RECT  15.3 40.829 15.318 40.865 ;
     RECT  19.62 40.787 24.105 40.865 ;
     RECT  31.356 40.829 31.374 40.865 ;
     RECT  50.796 40.787 51.105 40.865 ;
     RECT  54.396 40.829 54.414 40.865 ;
     RECT  58.32 40.829 58.446 40.865 ;
     RECT  41.364 40.559 41.454 40.877 ;
     RECT  42.264 40.829 42.642 40.877 ;
     RECT  56.232 40.829 56.505 40.877 ;
     RECT  58.356 40.865 58.446 40.877 ;
     RECT  59.58 40.829 59.958 40.877 ;
     RECT  60.984 40.589 62.334 40.877 ;
     RECT  47.448 40.829 47.466 40.901 ;
     RECT  32.328 40.829 32.742 40.937 ;
     RECT  64.944 40.595 65.106 40.937 ;
     RECT  23.004 40.865 24.105 40.973 ;
     RECT  29.088 40.595 29.79 40.973 ;
     RECT  33.588 40.829 34.905 40.973 ;
     RECT  37.044 40.739 37.818 40.973 ;
     RECT  45.615 40.829 46.422 40.973 ;
     RECT  58.428 40.877 58.446 40.973 ;
     RECT  59.58 40.877 59.598 40.973 ;
     RECT  60.984 40.877 61.002 40.973 ;
     RECT  61.815 40.877 62.334 40.973 ;
     RECT  64.944 40.937 64.962 40.973 ;
     RECT  23.004 40.973 23.238 41.009 ;
     RECT  29.415 40.973 29.79 41.009 ;
     RECT  32.472 40.937 32.742 41.009 ;
     RECT  33.624 40.973 34.905 41.009 ;
     RECT  24.015 40.973 24.105 41.057 ;
     RECT  29.415 41.009 29.505 41.057 ;
     RECT  34.815 41.009 34.905 41.057 ;
     RECT  39.636 40.787 40.305 41.057 ;
     RECT  45.615 40.973 45.705 41.057 ;
     RECT  51.015 40.865 51.105 41.057 ;
     RECT  56.415 40.877 56.505 41.057 ;
     RECT  61.815 40.973 61.905 41.057 ;
     RECT  67.215 40.787 67.305 41.057 ;
     RECT  72.615 40.787 72.705 41.057 ;
     RECT  78.015 40.787 78.105 41.057 ;
     RECT  83.415 40.787 83.505 41.057 ;
     RECT  88.815 40.787 88.905 41.057 ;
     RECT  37.692 40.973 37.818 41.309 ;
     RECT  33.624 41.009 33.642 41.324 ;
     RECT  25.164 40.739 25.974 41.369 ;
     RECT  110.556 41.368 110.574 41.405 ;
     RECT  23.004 41.009 23.022 41.594 ;
     RECT  109.368 41.521 109.386 41.639 ;
     RECT  105.015 40.469 105.426 41.719 ;
     RECT  104.004 40.361 104.022 41.749 ;
     RECT  103.932 41.749 104.022 41.755 ;
     RECT  104.868 41.719 105.426 41.755 ;
     RECT  103.932 41.755 105.426 41.791 ;
     RECT  19.62 40.865 22.23 41.836 ;
     RECT  25.668 41.369 25.974 41.836 ;
     RECT  89.82 32.063 92.574 41.881 ;
     RECT  93.312 35.267 94.497 41.881 ;
     RECT  106.884 41.791 106.902 41.881 ;
     RECT  6.408 32.999 6.426 41.899 ;
     RECT  19.62 41.836 22.842 41.909 ;
     RECT  25.668 41.836 26.046 41.909 ;
     RECT  39.636 41.057 39.654 41.909 ;
     RECT  87.192 31.919 87.282 41.909 ;
     RECT  103.68 41.791 105.426 41.909 ;
     RECT  32.544 41.009 32.562 41.945 ;
     RECT  106.596 41.881 106.902 41.945 ;
     RECT  25.668 41.909 25.83 41.981 ;
     RECT  25.812 41.981 25.83 42.017 ;
     RECT  104.004 41.909 104.094 42.017 ;
     RECT  89.82 41.881 94.497 42.457 ;
     RECT  95.328 35.267 95.598 42.457 ;
     RECT  108.36 39.281 108.378 42.601 ;
     RECT  18.615 40.703 18.897 42.727 ;
     RECT  19.62 41.909 22.23 42.727 ;
     RECT  111.132 42.619 111.15 42.755 ;
     RECT  107.82 42.601 108.774 42.763 ;
     RECT  107.64 42.763 108.774 42.8 ;
     RECT  108.36 42.8 108.774 42.871 ;
     RECT  106.596 41.945 106.614 42.961 ;
     RECT  106.596 42.961 107.01 42.989 ;
     RECT  108.36 42.871 109.314 42.989 ;
     RECT  105.015 41.909 105.426 43.033 ;
     RECT  106.236 42.997 106.254 43.033 ;
     RECT  108.612 42.989 109.314 43.061 ;
     RECT  108.612 43.061 108.63 43.169 ;
     RECT  18.615 42.727 22.23 43.2 ;
     RECT  37.8 41.309 37.818 43.2 ;
     RECT  41.364 40.877 41.382 43.2 ;
     RECT  87.264 41.909 87.282 43.2 ;
     RECT  106.992 42.989 107.01 43.951 ;
     RECT  105.015 43.033 106.254 44.077 ;
     RECT  106.992 43.951 107.694 44.077 ;
     RECT  110.556 43.915 110.574 44.105 ;
     RECT  105.015 44.077 107.694 44.339 ;
     RECT  105.015 44.339 107.55 44.375 ;
     RECT  7.815 35.885 8.097 44.761 ;
     RECT  6.228 41.899 6.426 44.851 ;
     RECT  0.54 44.917 0.558 44.957 ;
     RECT  7.815 44.761 8.658 44.987 ;
     RECT  10.8 44.761 10.818 44.987 ;
     RECT  6.228 44.851 6.822 44.995 ;
     RECT  5.688 44.995 6.822 45.149 ;
     RECT  8.928 44.995 8.946 45.149 ;
     RECT  5.688 45.149 6.534 45.185 ;
     RECT  109.98 45.157 109.998 45.245 ;
     RECT  106.992 44.375 107.334 45.527 ;
     RECT  108.828 45.301 108.846 45.689 ;
     RECT  104.004 42.017 104.022 45.691 ;
     RECT  105.015 44.375 106.254 45.691 ;
     RECT  108.468 45.841 108.63 45.995 ;
     RECT  106.992 45.527 107.01 46.103 ;
     RECT  104.004 45.691 106.254 46.123 ;
     RECT  103.716 46.123 106.254 46.265 ;
     RECT  103.86 46.265 106.254 46.535 ;
     RECT  109.98 46.459 109.998 46.535 ;
     RECT  105.015 46.535 106.254 46.579 ;
     RECT  103.86 46.535 104.022 46.607 ;
     RECT  105.015 46.579 106.434 46.679 ;
     RECT  108.576 45.995 108.63 46.741 ;
     RECT  108.36 46.741 108.63 46.769 ;
     RECT  108.36 46.769 108.378 47.731 ;
     RECT  107.82 47.731 108.702 47.848 ;
     RECT  107.64 47.848 108.702 47.857 ;
     RECT  107.64 47.857 108.954 47.885 ;
     RECT  111.132 47.755 111.15 47.885 ;
     RECT  108.36 47.885 108.954 48.001 ;
     RECT  108.36 48.001 109.206 48.263 ;
     RECT  108.36 48.263 108.954 49.081 ;
     RECT  110.592 48.937 110.61 49.085 ;
     RECT  107.82 49.081 108.954 49.199 ;
     RECT  105.015 46.679 106.254 49.315 ;
     RECT  106.992 49.171 107.01 49.315 ;
     RECT  105.015 49.315 107.01 49.351 ;
     RECT  107.82 49.199 107.838 49.351 ;
     RECT  105.015 49.351 107.838 49.469 ;
     RECT  18.615 43.2 88.776 49.477 ;
     RECT  107.316 49.469 107.73 49.505 ;
     RECT  18.615 49.477 88.902 49.517 ;
     RECT  111.132 50.347 111.15 50.387 ;
     RECT  18.615 49.517 88.776 50.539 ;
     RECT  109.8 50.431 109.818 50.549 ;
     RECT  107.316 49.505 107.334 50.701 ;
     RECT  96.336 33.917 97.254 50.819 ;
     RECT  107.316 50.701 107.766 50.863 ;
     RECT  108.936 49.199 108.954 50.863 ;
     RECT  107.316 50.863 108.954 50.927 ;
     RECT  18.615 50.539 88.866 50.935 ;
     RECT  105.015 49.469 106.254 50.935 ;
     RECT  107.316 50.927 108.306 50.963 ;
     RECT  107.532 50.963 108.306 51.125 ;
     RECT  107.532 51.125 107.55 51.197 ;
     RECT  18.615 50.935 88.902 51.307 ;
     RECT  104.004 46.607 104.022 51.355 ;
     RECT  104.004 51.355 104.094 51.475 ;
     RECT  105.015 50.935 106.326 51.475 ;
     RECT  104.004 51.475 106.326 51.629 ;
     RECT  105.015 51.629 106.326 51.637 ;
     RECT  111.132 51.595 111.15 51.665 ;
     RECT  18.615 51.307 88.938 51.737 ;
     RECT  104.004 51.629 104.274 51.809 ;
     RECT  105.015 51.637 106.722 51.809 ;
     RECT  18.615 51.737 88.866 51.821 ;
     RECT  108.288 51.125 108.306 52.861 ;
     RECT  107.748 52.861 108.954 52.979 ;
     RECT  110.556 52.891 110.574 53.015 ;
     RECT  107.748 52.979 108.45 53.023 ;
     RECT  89.82 42.457 95.598 53.051 ;
     RECT  107.64 53.023 108.45 53.069 ;
     RECT  109.836 53.131 109.854 53.285 ;
     RECT  96.408 50.819 97.254 53.293 ;
     RECT  89.82 53.051 90.27 53.321 ;
     RECT  104.004 51.809 104.022 53.321 ;
     RECT  107.748 53.069 108.45 53.941 ;
     RECT  107.316 53.941 108.45 54.211 ;
     RECT  106.992 54.211 108.45 54.239 ;
     RECT  105.015 51.809 106.254 54.329 ;
     RECT  106.992 54.239 108.306 54.337 ;
     RECT  111.132 54.187 111.15 54.365 ;
     RECT  106.848 54.337 108.306 54.401 ;
     RECT  90.252 53.321 90.27 54.437 ;
     RECT  106.848 54.401 106.974 54.635 ;
     RECT  105.015 54.329 106.038 55.021 ;
     RECT  91.044 53.051 95.598 55.111 ;
     RECT  96.336 53.293 97.254 55.111 ;
     RECT  107.712 54.401 108.306 55.111 ;
     RECT  104.904 55.021 106.038 55.243 ;
     RECT  104.724 55.243 106.038 55.283 ;
     RECT  106.956 54.635 106.974 55.409 ;
     RECT  107.712 55.111 108.954 55.409 ;
     RECT  109.98 55.435 109.998 55.481 ;
     RECT  107.712 55.409 108.306 55.553 ;
     RECT  91.044 55.111 97.254 55.949 ;
     RECT  18.615 51.821 88.776 56.101 ;
     RECT  18.615 56.101 88.902 56.429 ;
     RECT  105.015 55.283 106.038 56.641 ;
     RECT  91.26 55.949 97.254 56.759 ;
     RECT  111.132 56.731 111.15 56.795 ;
     RECT  91.584 56.759 97.254 56.839 ;
     RECT  104.364 56.641 106.038 56.875 ;
     RECT  108.288 55.553 108.306 56.911 ;
     RECT  104.22 56.875 106.038 56.939 ;
     RECT  18.615 56.429 88.866 57.005 ;
     RECT  91.584 56.839 97.542 57.029 ;
     RECT  107.712 56.911 108.306 57.065 ;
     RECT  104.94 56.939 106.038 57.137 ;
     RECT  6.228 45.185 6.534 57.209 ;
     RECT  91.584 57.029 97.326 57.209 ;
     RECT  6.228 57.209 6.246 57.299 ;
     RECT  104.94 57.137 105.822 57.335 ;
     RECT  4.86 57.181 4.878 57.407 ;
     RECT  3.924 57.403 3.942 57.415 ;
     RECT  2.415 23.819 2.697 57.451 ;
     RECT  3.924 57.415 4.662 57.451 ;
     RECT  91.584 57.209 95.094 57.485 ;
     RECT  2.415 57.451 4.662 57.499 ;
     RECT  2.304 57.499 4.662 57.569 ;
     RECT  91.728 57.485 95.094 57.569 ;
     RECT  90.612 56.875 90.63 57.581 ;
     RECT  2.304 57.569 2.697 57.605 ;
     RECT  3.744 57.569 3.762 57.605 ;
     RECT  96.084 57.209 97.326 57.605 ;
     RECT  91.728 57.569 94.662 57.749 ;
     RECT  4.644 57.569 4.662 57.875 ;
     RECT  96.084 57.605 96.93 57.911 ;
     RECT  96.084 57.911 96.75 57.947 ;
     RECT  108.288 57.065 108.306 57.991 ;
     RECT  91.728 57.749 94.626 58.019 ;
     RECT  96.732 57.947 96.75 58.019 ;
     RECT  110.556 57.991 110.574 58.061 ;
     RECT  107.82 57.991 108.342 58.117 ;
     RECT  109.332 57.991 109.35 58.117 ;
     RECT  107.64 58.117 109.35 58.145 ;
     RECT  91.728 58.019 94.497 58.157 ;
     RECT  107.64 58.145 108.882 58.157 ;
     RECT  92.016 58.157 94.497 58.217 ;
     RECT  18.615 57.005 88.776 58.219 ;
     RECT  92.016 58.217 93.114 58.289 ;
     RECT  92.016 58.289 92.862 58.379 ;
     RECT  18.615 58.219 88.902 58.415 ;
     RECT  108.288 58.157 108.882 58.415 ;
     RECT  92.016 58.379 92.79 58.649 ;
     RECT  18.615 58.415 88.866 58.829 ;
     RECT  90.648 58.315 90.666 58.955 ;
     RECT  92.016 58.649 92.322 58.987 ;
     RECT  19.692 58.829 88.866 59.021 ;
     RECT  94.032 58.217 94.497 59.071 ;
     RECT  93.708 59.071 94.497 59.117 ;
     RECT  91.98 58.987 92.322 59.161 ;
     RECT  20.016 59.021 88.866 59.297 ;
     RECT  105.015 57.335 105.822 59.341 ;
     RECT  108.288 58.415 108.846 59.341 ;
     RECT  20.016 59.297 20.214 59.459 ;
     RECT  20.088 59.459 20.214 59.495 ;
     RECT  111.132 59.275 111.15 59.495 ;
     RECT  105.015 59.341 106.218 59.503 ;
     RECT  104.976 59.503 106.218 59.539 ;
     RECT  106.992 59.503 107.01 59.539 ;
     RECT  91.224 59.161 92.322 59.563 ;
     RECT  108 59.341 108.846 59.603 ;
     RECT  104.976 59.539 107.01 59.611 ;
     RECT  108 59.603 108.342 59.611 ;
     RECT  91.224 59.563 92.358 59.659 ;
     RECT  109.26 59.611 109.278 59.701 ;
     RECT  20.196 59.495 20.214 59.729 ;
     RECT  104.976 59.611 108.342 59.729 ;
     RECT  109.26 59.701 109.458 59.729 ;
     RECT  91.224 59.659 92.646 59.755 ;
     RECT  106.884 59.729 107.01 59.765 ;
     RECT  106.992 59.765 107.01 59.801 ;
     RECT  109.44 59.729 109.458 59.801 ;
     RECT  104.976 59.729 106.038 59.843 ;
     RECT  21.096 59.297 88.866 59.981 ;
     RECT  91.224 59.755 92.718 59.981 ;
     RECT  108 59.729 108.342 59.999 ;
     RECT  91.872 59.981 92.718 60.035 ;
     RECT  21.096 59.981 21.69 60.077 ;
     RECT  21.672 60.077 21.69 60.173 ;
     RECT  22.464 59.981 88.866 60.179 ;
     RECT  20.268 60.151 20.286 60.269 ;
     RECT  91.872 60.035 91.926 60.269 ;
     RECT  18.615 58.829 18.897 60.385 ;
     RECT  91.872 60.269 91.89 60.575 ;
     RECT  109.98 60.547 109.998 60.605 ;
     RECT  104.976 59.843 105.714 60.691 ;
     RECT  108.288 59.999 108.342 60.691 ;
     RECT  104.436 60.691 105.714 60.749 ;
     RECT  108.288 60.691 108.558 60.845 ;
     RECT  104.58 60.749 105.714 60.989 ;
     RECT  22.464 60.179 88.776 61.032 ;
     RECT  18.615 60.385 19.026 61.079 ;
     RECT  104.976 60.989 105.714 62.159 ;
     RECT  108.288 60.845 108.306 62.159 ;
     RECT  112.212 61.867 112.23 62.231 ;
     RECT  104.976 62.159 105.297 62.275 ;
     RECT  106.992 62.239 107.802 62.285 ;
     RECT  103.824 62.155 103.842 62.303 ;
     RECT  104.652 62.275 105.297 62.311 ;
     RECT  2.415 57.605 2.697 62.387 ;
     RECT  7.815 44.987 8.097 62.387 ;
     RECT  13.215 40.739 13.497 62.387 ;
     RECT  18.615 61.079 18.897 62.387 ;
     RECT  94.215 59.117 94.497 62.387 ;
     RECT  99.615 31.019 99.897 62.387 ;
     RECT  103.968 62.311 105.297 62.387 ;
     RECT  103.968 62.387 105.105 62.429 ;
     RECT  107.172 62.285 107.802 62.429 ;
     RECT  108.54 62.311 108.99 62.465 ;
     RECT  104.976 62.429 105.105 62.537 ;
     RECT  107.172 62.429 107.658 62.537 ;
     RECT  108.54 62.465 108.558 62.537 ;
     RECT  103.968 62.429 103.986 62.609 ;
     RECT  107.172 62.537 107.19 62.609 ;
     RECT  2.415 62.387 2.505 62.657 ;
     RECT  7.815 62.387 7.905 62.657 ;
     RECT  13.215 62.387 13.305 62.657 ;
     RECT  18.615 62.387 18.705 62.657 ;
     RECT  94.215 62.387 94.305 62.657 ;
     RECT  99.615 62.387 99.705 62.657 ;
     RECT  105.015 62.537 105.105 62.657 ;
     RECT  111.132 62.275 111.15 63.197 ;
    LAYER M4 ;
     RECT  0.06 7.248 0.137 7.272 ;
     RECT  0.06 19.824 0.137 19.848 ;
     RECT  0.06 32.4 0.137 32.424 ;
     RECT  0.06 44.928 0.569 44.952 ;
     RECT  2.329 4.224 2.408 4.248 ;
     RECT  2.401 9.264 2.408 9.288 ;
     RECT  2.293 10.992 2.408 11.016 ;
     RECT  2.293 12 2.408 12.024 ;
     RECT  2.329 13.632 2.408 13.656 ;
     RECT  2.401 21.984 2.408 22.008 ;
     RECT  0.06 57.504 2.408 57.528 ;
     RECT  2.408 2.148 2.512 62.652 ;
     RECT  2.512 2.418 2.704 62.382 ;
     RECT  2.704 13.632 2.819 16.392 ;
     RECT  2.819 13.632 2.915 15.528 ;
     RECT  2.915 14.16 3.443 15.528 ;
     RECT  2.704 21.552 3.443 24.504 ;
     RECT  2.704 6.768 3.913 11.304 ;
     RECT  3.443 15.312 4.061 15.528 ;
     RECT  2.704 18.048 4.069 19.272 ;
     RECT  2.704 20.4 4.069 20.424 ;
     RECT  4.069 18.048 4.115 20.424 ;
     RECT  4.115 19.2 4.156 20.424 ;
     RECT  2.704 2.496 4.213 5.784 ;
     RECT  3.913 6.768 4.213 12.024 ;
     RECT  3.443 14.16 4.273 14.232 ;
     RECT  4.213 2.496 4.309 12.024 ;
     RECT  4.309 2.496 4.345 12.072 ;
     RECT  4.061 15.504 4.453 15.528 ;
     RECT  4.273 13.968 4.489 14.232 ;
     RECT  3.443 21.552 4.643 22.824 ;
     RECT  4.345 2.496 4.741 12.312 ;
     RECT  4.489 13.632 4.777 14.232 ;
     RECT  4.741 2.304 4.837 12.312 ;
     RECT  4.777 13.296 4.837 14.232 ;
     RECT  3.836 0.048 5.075 0.072 ;
     RECT  4.156 19.2 5.105 19.32 ;
     RECT  4.837 2.304 5.18 14.232 ;
     RECT  4.115 18.048 5.201 18.216 ;
     RECT  5.105 19.2 5.201 19.224 ;
     RECT  5.18 2.208 5.209 14.232 ;
     RECT  4.453 15.504 5.209 16.392 ;
     RECT  5.209 2.208 5.267 16.392 ;
     RECT  5.201 18.048 5.285 19.224 ;
     RECT  4.156 20.4 5.317 20.424 ;
     RECT  5.317 20.4 5.425 20.856 ;
     RECT  5.285 19.2 5.501 19.224 ;
     RECT  5.285 18.048 5.605 18.072 ;
     RECT  5.267 2.736 5.699 16.392 ;
     RECT  5.699 4.608 5.753 16.392 ;
     RECT  5.269 0.528 5.861 0.552 ;
     RECT  3.443 24.48 5.965 24.504 ;
     RECT  4.643 22.272 5.989 22.824 ;
     RECT  5.965 24.48 6.069 24.648 ;
     RECT  5.753 14.64 6.073 16.392 ;
     RECT  5.605 17.952 6.073 18.072 ;
     RECT  5.425 20.304 6.145 20.856 ;
     RECT  5.989 22.272 6.217 23.208 ;
     RECT  5.699 2.736 6.22 3.432 ;
     RECT  6.145 20.304 6.253 21.192 ;
     RECT  6.217 22.272 6.253 23.352 ;
     RECT  6.22 2.832 6.257 3.432 ;
     RECT  6.073 14.64 6.649 18.072 ;
     RECT  5.753 4.608 6.685 13.656 ;
     RECT  5.857 32.496 6.901 32.52 ;
     RECT  6.685 4.512 7.009 13.656 ;
     RECT  6.649 14.64 7.009 18.168 ;
     RECT  6.901 32.496 7.189 32.856 ;
     RECT  7.009 4.512 7.297 18.168 ;
     RECT  7.297 4.512 7.405 18.984 ;
     RECT  6.253 20.304 7.405 23.352 ;
     RECT  6.577 26.64 7.621 26.664 ;
     RECT  7.621 34.08 7.657 34.104 ;
     RECT  6.257 3.024 7.669 3.432 ;
     RECT  7.405 4.512 7.669 23.352 ;
     RECT  7.621 28.8 7.693 28.824 ;
     RECT  7.189 31.872 7.693 32.856 ;
     RECT  7.669 3.024 7.808 23.352 ;
     RECT  6.069 24.624 7.808 24.648 ;
     RECT  7.621 26.64 7.808 27.336 ;
     RECT  7.693 28.8 7.808 29.256 ;
     RECT  7.693 30.96 7.808 32.856 ;
     RECT  7.657 34.08 7.808 34.392 ;
     RECT  6.217 41.904 7.808 41.928 ;
     RECT  3.913 57.408 7.808 57.432 ;
     RECT  7.808 2.148 7.912 62.652 ;
     RECT  7.912 2.418 8.104 62.382 ;
     RECT  8.104 18.144 8.201 23.352 ;
     RECT  8.104 44.88 8.243 44.904 ;
     RECT  8.104 57.408 8.243 57.432 ;
     RECT  8.201 18.432 8.273 23.352 ;
     RECT  8.273 22.224 8.489 23.352 ;
     RECT  8.104 32.304 8.525 34.392 ;
     RECT  8.104 28.752 8.633 30.984 ;
     RECT  8.104 3.024 8.849 17.112 ;
     RECT  8.273 18.432 8.885 21.24 ;
     RECT  8.849 3.024 8.957 3.624 ;
     RECT  8.489 22.224 9.065 22.728 ;
     RECT  8.525 32.304 9.097 33.288 ;
     RECT  8.849 4.752 9.101 17.112 ;
     RECT  8.633 28.752 9.209 30.6 ;
     RECT  8.885 18.432 9.281 21.192 ;
     RECT  8.104 24.624 9.313 24.648 ;
     RECT  8.104 26.64 9.313 27.192 ;
     RECT  9.209 28.752 9.313 29.064 ;
     RECT  9.101 4.848 9.377 17.112 ;
     RECT  9.065 22.224 9.529 22.632 ;
     RECT  9.377 4.848 9.533 17.208 ;
     RECT  8.104 35.712 9.589 35.88 ;
     RECT  8.104 36.864 9.589 36.888 ;
     RECT  9.421 38.4 9.589 38.424 ;
     RECT  9.533 4.992 9.637 17.208 ;
     RECT  9.281 18.432 9.637 20.904 ;
     RECT  8.525 34.368 9.709 34.392 ;
     RECT  9.097 31.92 9.733 33.288 ;
     RECT  9.709 34.368 9.733 34.584 ;
     RECT  9.313 24.48 9.781 24.648 ;
     RECT  9.889 1.728 9.973 1.752 ;
     RECT  9.781 24.48 9.973 24.744 ;
     RECT  9.313 26.64 10.019 29.064 ;
     RECT  9.973 24.192 10.028 24.744 ;
     RECT  10.028 24.192 10.033 25.608 ;
     RECT  10.019 26.64 10.033 27.096 ;
     RECT  9.209 30.192 10.069 30.6 ;
     RECT  9.589 35.712 10.069 38.424 ;
     RECT  9.733 31.92 10.163 34.584 ;
     RECT  9.529 22.176 10.213 22.632 ;
     RECT  10.069 30.192 10.213 30.84 ;
     RECT  10.163 31.92 10.213 33.096 ;
     RECT  8.957 3.408 10.285 3.624 ;
     RECT  10.213 30.192 10.307 33.096 ;
     RECT  9.637 4.992 10.321 20.904 ;
     RECT  10.213 22.176 10.321 22.872 ;
     RECT  10.309 2.256 10.396 2.28 ;
     RECT  10.321 4.992 10.433 22.872 ;
     RECT  10.285 3.36 10.493 3.624 ;
     RECT  10.493 2.88 10.577 3.624 ;
     RECT  10.577 3.408 10.609 3.624 ;
     RECT  10.433 19.2 10.649 22.872 ;
     RECT  10.163 34.128 10.753 34.584 ;
     RECT  10.069 35.712 10.753 38.808 ;
     RECT  10.033 24.192 10.789 27.096 ;
     RECT  10.753 34.128 10.789 38.808 ;
     RECT  10.789 34.128 10.829 39.048 ;
     RECT  10.213 1.152 10.865 1.176 ;
     RECT  10.649 22.608 10.885 22.872 ;
     RECT  10.789 24.144 10.885 27.096 ;
     RECT  10.885 22.608 10.973 27.096 ;
     RECT  10.609 3.408 11.005 3.864 ;
     RECT  11.005 3.408 11.077 4.008 ;
     RECT  10.433 4.992 11.077 18.024 ;
     RECT  10.019 28.176 11.113 29.064 ;
     RECT  10.307 30.576 11.221 33.096 ;
     RECT  10.973 22.608 11.333 24.216 ;
     RECT  10.829 34.656 11.365 39.048 ;
     RECT  11.077 3.408 11.401 18.024 ;
     RECT  10.649 19.2 11.401 21.528 ;
     RECT  10.973 25.2 11.513 27.096 ;
     RECT  11.221 30.576 11.549 33.576 ;
     RECT  11.401 3.408 11.621 21.528 ;
     RECT  11.113 28.176 11.725 29.4 ;
     RECT  11.725 28.176 11.761 29.592 ;
     RECT  11.333 23.184 11.873 24.216 ;
     RECT  11.365 34.656 11.873 39.288 ;
     RECT  11.029 1.728 11.893 1.752 ;
     RECT  11.873 23.328 11.981 24.216 ;
     RECT  11.513 25.2 12.233 27 ;
     RECT  11.761 28.08 12.332 29.592 ;
     RECT  11.549 30.576 12.332 33.144 ;
     RECT  11.873 34.8 12.553 39.288 ;
     RECT  8.104 40.32 12.553 40.872 ;
     RECT  11.621 3.696 12.709 21.528 ;
     RECT  12.332 28.08 12.769 33.144 ;
     RECT  12.709 2.88 12.805 21.528 ;
     RECT  12.553 34.8 12.877 40.872 ;
     RECT  12.805 2.88 13.129 21.96 ;
     RECT  12.877 34.752 13.201 40.872 ;
     RECT  11.893 1.152 13.208 1.752 ;
     RECT  13.129 2.832 13.208 21.96 ;
     RECT  11.981 24.144 13.208 24.216 ;
     RECT  12.233 25.2 13.208 26.856 ;
     RECT  12.769 27.888 13.208 33.144 ;
     RECT  13.201 34.176 13.208 40.872 ;
     RECT  8.104 41.904 13.208 41.928 ;
     RECT  13.208 1.152 13.283 62.652 ;
     RECT  13.283 2.148 13.312 62.652 ;
     RECT  13.312 2.418 13.504 62.382 ;
     RECT  13.525 0.096 13.667 0.12 ;
     RECT  13.504 21.936 13.745 40.872 ;
     RECT  13.745 22.08 14.105 40.872 ;
     RECT  14.105 30.72 14.185 40.872 ;
     RECT  13.504 2.832 14.321 14.76 ;
     RECT  14.321 3.12 14.357 14.76 ;
     RECT  13.283 1.152 14.389 1.176 ;
     RECT  14.357 3.264 14.401 14.76 ;
     RECT  14.401 3.408 14.497 14.76 ;
     RECT  13.504 15.84 14.497 20.856 ;
     RECT  14.389 1.152 14.681 1.752 ;
     RECT  14.105 22.08 14.897 29.448 ;
     RECT  14.897 23.568 14.933 29.448 ;
     RECT  14.933 23.568 15.185 25.128 ;
     RECT  14.497 3.408 15.437 20.856 ;
     RECT  15.185 23.568 15.437 25.08 ;
     RECT  14.185 30.864 15.505 40.872 ;
     RECT  15.505 30.672 15.905 40.872 ;
     RECT  14.933 26.784 16.153 29.448 ;
     RECT  15.905 30.672 16.153 34.2 ;
     RECT  14.897 22.08 16.405 22.104 ;
     RECT  15.437 3.408 16.441 16.968 ;
     RECT  15.437 23.76 16.549 25.08 ;
     RECT  15.437 18.24 16.585 20.856 ;
     RECT  16.585 18.24 16.597 21.096 ;
     RECT  16.405 22.08 16.597 22.2 ;
     RECT  16.597 18.24 16.661 22.2 ;
     RECT  16.661 19.536 16.669 22.2 ;
     RECT  16.669 21.936 16.684 22.2 ;
     RECT  16.441 3.12 16.877 16.968 ;
     RECT  16.153 26.784 16.945 34.2 ;
     RECT  16.549 23.568 16.981 25.08 ;
     RECT  16.945 26.064 16.981 34.2 ;
     RECT  15.905 35.52 16.981 40.872 ;
     RECT  16.877 11.232 16.985 16.968 ;
     RECT  16.684 22.08 17.017 22.2 ;
     RECT  16.981 23.568 17.017 40.872 ;
     RECT  16.877 3.12 17.053 10.152 ;
     RECT  16.661 18.24 17.125 18.264 ;
     RECT  16.985 11.52 17.557 16.968 ;
     RECT  17.125 18 17.557 18.264 ;
     RECT  15.253 0.576 17.699 0.6 ;
     RECT  17.053 2.88 17.948 10.152 ;
     RECT  16.669 19.536 17.989 20.856 ;
     RECT  17.017 22.08 17.989 40.872 ;
     RECT  17.557 11.52 18.061 18.264 ;
     RECT  17.948 2.88 18.133 10.392 ;
     RECT  18.061 11.424 18.133 18.264 ;
     RECT  17.989 19.296 18.205 20.856 ;
     RECT  17.989 21.936 18.205 40.872 ;
     RECT  14.681 1.728 18.229 1.752 ;
     RECT  18.133 2.88 18.229 18.264 ;
     RECT  18.205 19.296 18.421 40.872 ;
     RECT  13.504 41.904 18.421 41.928 ;
     RECT  18.229 1.728 18.457 18.264 ;
     RECT  18.421 19.296 18.457 41.928 ;
     RECT  18.457 1.728 18.469 41.928 ;
     RECT  18.469 1.68 18.608 41.928 ;
     RECT  18.421 61.152 18.608 61.176 ;
     RECT  18.608 1.68 18.712 62.652 ;
     RECT  18.712 1.68 18.904 62.382 ;
     RECT  18.904 15.84 18.929 41.928 ;
     RECT  18.904 1.68 19.001 1.704 ;
     RECT  18.904 51.888 19.933 51.912 ;
     RECT  18.904 49.2 20.041 50.184 ;
     RECT  19.933 51.888 20.041 52.296 ;
     RECT  18.904 55.728 20.149 55.752 ;
     RECT  20.041 49.2 20.185 50.28 ;
     RECT  20.149 55.536 20.185 55.752 ;
     RECT  19.897 56.784 20.293 56.808 ;
     RECT  18.904 3.264 20.365 14.76 ;
     RECT  20.365 3.12 20.473 14.76 ;
     RECT  18.929 16.032 20.473 41.928 ;
     RECT  20.185 49.2 20.509 50.856 ;
     RECT  20.041 51.888 20.509 52.488 ;
     RECT  18.904 53.616 20.509 53.64 ;
     RECT  20.185 55.152 20.509 55.752 ;
     RECT  20.293 56.784 20.509 57.672 ;
     RECT  18.904 58.8 20.545 59.016 ;
     RECT  20.509 49.2 20.941 57.672 ;
     RECT  20.545 58.8 20.941 59.112 ;
     RECT  20.473 3.12 20.981 41.928 ;
     RECT  20.981 3.12 21.013 18.264 ;
     RECT  21.013 3.024 21.085 18.264 ;
     RECT  20.941 49.2 21.085 59.112 ;
     RECT  20.257 60.24 21.085 60.264 ;
     RECT  20.981 19.488 21.125 41.928 ;
     RECT  21.085 2.88 21.157 18.264 ;
     RECT  21.125 22.464 21.337 41.928 ;
     RECT  21.157 2.736 21.365 18.264 ;
     RECT  21.365 2.256 21.449 18.264 ;
     RECT  21.449 2.976 21.665 18.264 ;
     RECT  21.125 19.488 21.665 21.144 ;
     RECT  21.665 16.32 21.949 18.264 ;
     RECT  21.665 19.488 21.949 20.904 ;
     RECT  21.337 22.464 22.021 42.456 ;
     RECT  21.665 2.976 22.205 15.24 ;
     RECT  22.021 22.464 22.211 42.504 ;
     RECT  22.211 22.464 22.313 35.544 ;
     RECT  22.211 36.528 22.536 42.504 ;
     RECT  21.085 49.2 22.536 60.264 ;
     RECT  22.205 3.36 22.705 15.24 ;
     RECT  21.949 16.32 22.705 20.904 ;
     RECT  22.705 3.36 23.281 20.904 ;
     RECT  23.281 3.36 23.713 21.144 ;
     RECT  22.313 22.464 23.713 27.192 ;
     RECT  23.713 3.36 23.749 27.192 ;
     RECT  22.313 28.224 23.749 35.544 ;
     RECT  22.536 36.528 23.749 61.032 ;
     RECT  23.749 3.312 23.821 27.192 ;
     RECT  23.749 28.224 23.821 61.032 ;
     RECT  23.821 3.312 24.008 61.032 ;
     RECT  24.008 2.148 24.112 61.032 ;
     RECT  24.112 2.418 24.304 61.032 ;
     RECT  24.304 3.312 25.333 21 ;
     RECT  24.304 22.128 25.333 61.032 ;
     RECT  25.333 3.312 26.525 61.032 ;
     RECT  26.525 3.312 26.957 27.144 ;
     RECT  26.957 22.608 27.029 27.144 ;
     RECT  27.029 22.656 27.493 27.144 ;
     RECT  26.525 28.272 27.493 61.032 ;
     RECT  26.957 3.312 27.569 21.624 ;
     RECT  27.569 3.312 27.925 21.144 ;
     RECT  27.925 2.88 28.033 21.144 ;
     RECT  27.493 1.728 28.069 1.752 ;
     RECT  28.033 2.832 28.069 21.144 ;
     RECT  28.069 1.728 29.027 21.144 ;
     RECT  27.493 22.656 29.041 61.032 ;
     RECT  28.465 0.096 29.185 0.12 ;
     RECT  29.027 2.148 29.221 21.144 ;
     RECT  29.041 22.32 29.221 61.032 ;
     RECT  29.221 2.148 29.512 61.032 ;
     RECT  29.185 0.096 29.545 0.168 ;
     RECT  29.545 0.096 29.555 1.128 ;
     RECT  29.555 0.144 29.843 1.128 ;
     RECT  29.843 1.104 30.085 1.128 ;
     RECT  30.085 1.104 30.419 1.176 ;
     RECT  29.512 2.418 30.581 61.032 ;
     RECT  30.581 1.68 31.025 61.032 ;
     RECT  31.025 1.68 31.523 1.752 ;
     RECT  31.025 2.88 32.317 61.032 ;
     RECT  32.317 2.832 32.357 61.032 ;
     RECT  32.357 2.832 32.429 7.032 ;
     RECT  31.523 1.728 32.749 1.752 ;
     RECT  32.357 8.016 33.041 20.088 ;
     RECT  32.749 1.68 33.155 1.752 ;
     RECT  32.429 3.312 33.505 7.032 ;
     RECT  33.041 8.016 33.505 19.56 ;
     RECT  32.357 21.696 33.685 61.032 ;
     RECT  33.505 3.312 33.793 19.56 ;
     RECT  33.685 21.648 34.153 61.032 ;
     RECT  34.045 0.576 34.259 0.6 ;
     RECT  33.793 2.88 34.513 19.56 ;
     RECT  34.153 21.072 34.513 61.032 ;
     RECT  33.155 1.728 34.808 1.752 ;
     RECT  34.513 2.88 34.808 61.032 ;
     RECT  34.808 1.728 35.104 61.032 ;
     RECT  35.104 1.728 35.891 1.8 ;
     RECT  35.104 2.832 36.137 20.712 ;
     RECT  35.891 1.728 36.353 1.752 ;
     RECT  35.104 21.984 36.385 61.032 ;
     RECT  36.137 2.832 37.001 20.616 ;
     RECT  37.001 11.76 37.289 20.136 ;
     RECT  37.001 2.832 37.613 10.728 ;
     RECT  36.385 21.6 37.645 61.032 ;
     RECT  37.645 21.264 37.721 61.032 ;
     RECT  37.289 11.856 37.829 20.136 ;
     RECT  37.721 21.264 38.195 40.872 ;
     RECT  37.613 3.024 38.473 10.728 ;
     RECT  37.829 12 38.837 20.136 ;
     RECT  38.473 3.024 39.26 11.016 ;
     RECT  38.837 12 39.26 19.848 ;
     RECT  38.195 21.504 39.877 40.872 ;
     RECT  39.877 21.36 40.021 40.872 ;
     RECT  39.26 3.024 40.165 19.848 ;
     RECT  40.165 3.024 40.208 20.088 ;
     RECT  40.021 21.12 40.208 40.872 ;
     RECT  37.721 41.904 40.208 61.032 ;
     RECT  40.208 2.148 40.312 61.032 ;
     RECT  40.312 2.418 40.504 40.872 ;
     RECT  40.504 3.024 41.357 20.136 ;
     RECT  41.357 3.36 41.569 20.136 ;
     RECT  40.504 21.648 41.569 35.256 ;
     RECT  40.504 36.288 41.573 40.872 ;
     RECT  41.569 3.36 42.077 35.256 ;
     RECT  42.077 10.56 42.541 35.256 ;
     RECT  41.573 36.336 42.541 40.872 ;
     RECT  42.541 10.56 42.653 40.872 ;
     RECT  42.653 10.56 44.129 40.632 ;
     RECT  42.077 3.36 44.665 9.528 ;
     RECT  44.129 10.56 44.665 13.608 ;
     RECT  45.253 1.728 45.46 1.752 ;
     RECT  44.665 3.36 45.565 13.608 ;
     RECT  44.129 14.64 45.565 40.632 ;
     RECT  45.46 1.728 45.608 1.8 ;
     RECT  45.565 3.36 45.608 40.632 ;
     RECT  40.312 41.904 45.608 61.032 ;
     RECT  45.608 1.728 45.712 61.032 ;
     RECT  45.712 1.728 45.904 40.782 ;
     RECT  45.904 1.728 46.069 1.752 ;
     RECT  46.069 1.152 46.141 1.752 ;
     RECT  45.904 3.36 46.163 40.728 ;
     RECT  46.141 0.576 46.289 1.752 ;
     RECT  46.163 3.36 46.397 33.048 ;
     RECT  46.289 0.576 46.403 0.6 ;
     RECT  46.397 3.36 46.757 10.92 ;
     RECT  46.289 1.728 46.933 1.752 ;
     RECT  46.933 1.728 47.219 1.8 ;
     RECT  46.163 34.08 47.225 40.728 ;
     RECT  46.397 11.952 47.401 33.048 ;
     RECT  47.225 34.08 47.401 35.352 ;
     RECT  47.219 1.728 47.513 1.752 ;
     RECT  47.689 0.576 47.749 0.6 ;
     RECT  47.401 11.952 47.843 35.352 ;
     RECT  47.843 11.952 47.909 20.136 ;
     RECT  47.749 0.576 48.035 1.176 ;
     RECT  46.757 3.36 48.229 10.872 ;
     RECT  47.843 21.12 48.373 35.352 ;
     RECT  47.225 36.48 48.373 40.728 ;
     RECT  48.229 3.12 48.409 10.872 ;
     RECT  48.035 1.152 48.485 1.176 ;
     RECT  48.409 3.12 48.661 10.92 ;
     RECT  48.661 2.88 48.851 10.92 ;
     RECT  47.909 12.192 49.061 20.136 ;
     RECT  48.517 1.728 49.093 1.752 ;
     RECT  48.851 3.12 49.201 10.92 ;
     RECT  49.061 12.192 49.201 13.416 ;
     RECT  49.201 3.12 49.277 13.416 ;
     RECT  49.093 1.728 49.427 1.8 ;
     RECT  49.277 7.968 49.637 13.416 ;
     RECT  49.637 8.256 50.029 13.416 ;
     RECT  49.061 14.496 50.029 20.136 ;
     RECT  50.029 8.256 50.605 20.136 ;
     RECT  48.373 21.12 50.605 40.728 ;
     RECT  50.54 0.096 50.627 0.12 ;
     RECT  49.427 1.728 51.008 1.752 ;
     RECT  49.277 3.12 51.008 6.984 ;
     RECT  50.605 8.256 51.008 40.728 ;
     RECT  45.712 41.904 51.008 61.032 ;
     RECT  51.008 1.728 51.112 61.032 ;
     RECT  51.112 1.728 51.304 40.782 ;
     RECT  51.304 2.784 51.443 40.728 ;
     RECT  51.304 1.728 51.509 1.752 ;
     RECT  51.793 0.576 51.923 0.6 ;
     RECT  51.443 2.88 52.481 40.728 ;
     RECT  52.481 2.88 52.517 24.696 ;
     RECT  52.517 10.512 52.625 24.696 ;
     RECT  52.625 10.512 52.985 10.968 ;
     RECT  52.405 1.152 53.093 1.176 ;
     RECT  52.517 2.88 53.555 9.384 ;
     RECT  52.481 25.776 53.557 40.728 ;
     RECT  53.555 3.408 53.665 9.384 ;
     RECT  53.161 1.728 53.957 1.752 ;
     RECT  52.625 12 53.989 24.696 ;
     RECT  52.985 10.512 54.025 10.872 ;
     RECT  53.989 11.952 54.025 24.696 ;
     RECT  53.665 3.408 54.601 9.528 ;
     RECT  54.025 10.512 54.601 24.696 ;
     RECT  54.601 3.408 54.637 24.696 ;
     RECT  54.637 3.312 54.673 24.696 ;
     RECT  53.557 25.728 54.673 40.728 ;
     RECT  54.673 3.312 55.573 40.728 ;
     RECT  55.573 3.024 55.789 40.728 ;
     RECT  55.789 2.88 56.221 40.728 ;
     RECT  56.221 2.88 56.408 40.872 ;
     RECT  51.112 41.904 56.408 61.032 ;
     RECT  56.408 2.148 56.512 61.032 ;
     RECT  56.512 2.418 56.704 40.872 ;
     RECT  56.704 2.832 56.945 40.872 ;
     RECT  56.945 2.832 58.129 2.856 ;
     RECT  56.945 3.84 58.129 40.872 ;
     RECT  58.129 2.832 58.385 40.872 ;
     RECT  58.385 2.832 59.033 40.632 ;
     RECT  59.033 30.624 59.929 40.632 ;
     RECT  59.033 2.832 61.045 29.64 ;
     RECT  59.929 30.624 61.045 40.872 ;
     RECT  61.045 2.832 61.808 40.872 ;
     RECT  56.512 41.904 61.808 61.032 ;
     RECT  61.808 2.148 61.912 61.032 ;
     RECT  61.912 2.418 62.104 40.782 ;
     RECT  62.104 2.736 62.339 40.632 ;
     RECT  62.339 2.736 62.741 40.584 ;
     RECT  62.741 2.832 63.029 40.584 ;
     RECT  62.917 1.728 63.733 1.752 ;
     RECT  63.733 1.152 63.853 1.752 ;
     RECT  63.853 1.152 64.307 1.8 ;
     RECT  64.307 1.152 64.825 1.752 ;
     RECT  64.825 0.576 65.009 1.752 ;
     RECT  63.029 2.832 65.029 40.344 ;
     RECT  65.029 2.832 65.116 40.824 ;
     RECT  65.009 0.576 66.515 0.6 ;
     RECT  65.009 1.728 67.208 1.752 ;
     RECT  65.116 2.832 67.208 40.344 ;
     RECT  61.912 41.904 67.208 61.032 ;
     RECT  67.208 1.728 67.312 61.032 ;
     RECT  67.312 1.728 67.504 40.782 ;
     RECT  67.504 2.832 67.637 40.344 ;
     RECT  67.637 2.832 67.753 27.048 ;
     RECT  67.637 28.032 67.811 40.344 ;
     RECT  67.811 28.032 67.961 39.864 ;
     RECT  67.961 29.472 67.997 39.864 ;
     RECT  67.504 1.728 68.195 1.8 ;
     RECT  67.753 2.88 68.285 27.048 ;
     RECT  67.741 0.576 68.435 0.6 ;
     RECT  68.285 3.312 68.641 27.048 ;
     RECT  67.961 28.032 68.641 28.2 ;
     RECT  67.997 29.472 69.037 39.576 ;
     RECT  68.641 3.312 69.145 28.2 ;
     RECT  69.037 29.184 69.145 39.576 ;
     RECT  69.145 3.312 69.217 39.576 ;
     RECT  69.217 3.312 69.437 39.912 ;
     RECT  69.437 3.408 69.539 39.912 ;
     RECT  68.195 1.728 69.544 1.752 ;
     RECT  69.539 3.408 69.581 39.576 ;
     RECT  69.581 29.088 69.797 39.576 ;
     RECT  69.544 1.728 69.827 1.8 ;
     RECT  69.581 3.408 69.833 27.912 ;
     RECT  69.797 29.088 70.049 37.704 ;
     RECT  69.833 3.408 70.553 27.864 ;
     RECT  70.553 3.408 70.585 24.168 ;
     RECT  69.827 1.728 70.597 1.752 ;
     RECT  70.585 3.36 70.693 24.168 ;
     RECT  70.049 29.568 70.765 37.704 ;
     RECT  69.797 38.688 70.765 39.576 ;
     RECT  70.597 1.152 70.805 1.752 ;
     RECT  70.765 29.568 71.123 39.576 ;
     RECT  70.693 3.12 71.153 24.168 ;
     RECT  70.553 25.296 71.161 27.864 ;
     RECT  71.153 3.072 71.237 24.168 ;
     RECT  71.123 29.568 71.593 39.336 ;
     RECT  70.805 1.728 71.597 1.752 ;
     RECT  71.237 3.12 71.597 24.168 ;
     RECT  71.593 29.472 71.633 39.336 ;
     RECT  71.161 25.296 71.737 28.008 ;
     RECT  71.737 25.248 71.809 28.008 ;
     RECT  71.633 29.472 71.809 39.192 ;
     RECT  71.597 3.456 71.953 24.168 ;
     RECT  71.809 25.248 71.953 39.192 ;
     RECT  71.953 3.456 72.608 39.192 ;
     RECT  67.312 41.904 72.608 61.032 ;
     RECT  72.608 2.148 72.712 61.032 ;
     RECT  72.712 2.418 72.904 40.782 ;
     RECT  72.904 3.696 73.325 28.536 ;
     RECT  72.904 29.568 74.077 38.952 ;
     RECT  73.325 3.696 74.293 28.488 ;
     RECT  74.077 29.472 74.293 38.952 ;
     RECT  74.293 3.696 74.369 38.952 ;
     RECT  74.369 37.584 75.155 38.952 ;
     RECT  74.369 3.696 75.269 36.552 ;
     RECT  75.269 4.128 75.349 36.552 ;
     RECT  75.155 37.584 75.349 38.28 ;
     RECT  75.349 4.128 75.413 38.28 ;
     RECT  75.413 33.744 75.441 38.28 ;
     RECT  75.413 4.128 75.701 32.472 ;
     RECT  75.441 33.744 75.701 37.608 ;
     RECT  75.701 33.744 75.875 35.928 ;
     RECT  75.875 35.808 75.889 35.928 ;
     RECT  75.875 33.744 76.025 34.536 ;
     RECT  75.701 36.96 76.025 37.608 ;
     RECT  75.701 4.128 76.529 27.624 ;
     RECT  75.701 28.752 76.837 32.472 ;
     RECT  76.837 28.752 76.849 32.76 ;
     RECT  76.025 33.744 76.849 33.816 ;
     RECT  76.849 28.752 76.853 33.816 ;
     RECT  76.025 37.584 76.931 37.608 ;
     RECT  75.889 35.808 77.569 35.832 ;
     RECT  76.529 4.128 77.605 27.576 ;
     RECT  77.569 35.424 77.749 35.832 ;
     RECT  77.605 3.888 77.785 27.576 ;
     RECT  76.853 28.752 77.785 33.672 ;
     RECT  77.785 3.888 77.821 33.672 ;
     RECT  77.821 3.696 78.008 33.672 ;
     RECT  77.749 34.656 78.008 35.832 ;
     RECT  77.749 36.816 78.008 36.84 ;
     RECT  72.712 41.904 78.008 61.032 ;
     RECT  78.008 2.148 78.112 61.032 ;
     RECT  78.112 2.418 78.304 40.782 ;
     RECT  78.304 3.552 78.401 33.96 ;
     RECT  78.401 33.552 78.437 33.96 ;
     RECT  78.304 36.816 78.437 36.84 ;
     RECT  78.437 33.648 78.653 33.96 ;
     RECT  78.653 33.936 78.905 33.96 ;
     RECT  78.401 3.552 79.049 31.752 ;
     RECT  79.049 3.6 79.193 31.752 ;
     RECT  79.193 3.84 79.229 31.752 ;
     RECT  79.229 3.84 80.449 31.176 ;
     RECT  80.449 3.696 80.629 31.176 ;
     RECT  80.533 1.728 80.633 1.752 ;
     RECT  80.821 1.152 80.845 1.176 ;
     RECT  80.845 0.576 80.917 1.176 ;
     RECT  80.917 0.096 81.065 1.176 ;
     RECT  81.065 0.096 81.155 0.6 ;
     RECT  81.155 0.096 81.443 0.12 ;
     RECT  81.637 1.728 82.105 1.752 ;
     RECT  80.629 3.408 82.573 31.176 ;
     RECT  82.573 3.408 83.221 31.752 ;
     RECT  82.105 1.728 83.408 1.8 ;
     RECT  83.221 2.88 83.408 31.752 ;
     RECT  78.112 41.904 83.408 61.032 ;
     RECT  83.408 1.728 83.512 61.032 ;
     RECT  83.512 1.728 83.704 40.782 ;
     RECT  83.221 0.096 83.891 0.12 ;
     RECT  83.704 2.88 84.017 31.752 ;
     RECT  84.017 2.88 84.413 31.272 ;
     RECT  84.413 2.88 84.493 30.984 ;
     RECT  83.704 1.728 85.021 1.752 ;
     RECT  85.021 1.728 85.283 1.8 ;
     RECT  85.283 1.728 85.765 1.752 ;
     RECT  85.765 1.152 85.813 1.752 ;
     RECT  84.493 3.408 85.889 30.984 ;
     RECT  85.889 4.176 85.957 30.984 ;
     RECT  85.813 0.576 86.141 1.752 ;
     RECT  85.957 4.176 86.713 31.176 ;
     RECT  86.141 0.576 86.915 0.6 ;
     RECT  86.713 4.176 87.001 31.224 ;
     RECT  87.001 4.128 87.397 31.224 ;
     RECT  87.397 4.128 87.473 31.368 ;
     RECT  87.473 23.616 87.505 31.368 ;
     RECT  87.473 4.128 87.613 22.584 ;
     RECT  87.613 3.888 88.189 22.584 ;
     RECT  86.141 1.728 88.261 1.752 ;
     RECT  88.261 1.152 88.409 1.752 ;
     RECT  88.409 1.2 88.595 1.752 ;
     RECT  88.189 3.024 88.693 22.584 ;
     RECT  87.505 23.616 88.693 31.512 ;
     RECT  83.512 41.904 88.704 61.032 ;
     RECT  88.595 1.728 88.765 1.752 ;
     RECT  88.704 49.296 88.776 60.264 ;
     RECT  88.765 1.728 88.808 1.848 ;
     RECT  88.693 3.024 88.808 31.512 ;
     RECT  88.704 41.904 88.808 42.456 ;
     RECT  88.808 1.728 88.912 42.456 ;
     RECT  88.776 56.4 88.913 60.264 ;
     RECT  88.912 1.728 89.104 40.782 ;
     RECT  89.104 1.728 89.273 1.752 ;
     RECT  89.104 3.024 89.273 30.984 ;
     RECT  89.273 3.024 89.921 30.36 ;
     RECT  88.776 49.296 90.641 51.912 ;
     RECT  88.912 41.904 90.899 42.456 ;
     RECT  90.899 41.904 90.947 41.928 ;
     RECT  89.921 3.408 91.249 30.36 ;
     RECT  91.249 3.408 91.361 30.456 ;
     RECT  91.361 3.6 91.429 30.456 ;
     RECT  91.429 3.6 91.645 30.552 ;
     RECT  90.529 31.68 91.645 31.704 ;
     RECT  91.645 3.6 91.829 31.704 ;
     RECT  90.641 49.392 91.829 51.72 ;
     RECT  88.913 56.496 91.901 60.264 ;
     RECT  91.933 54.816 92.077 54.84 ;
     RECT  91.829 3.744 92.081 31.704 ;
     RECT  92.081 3.888 92.117 31.704 ;
     RECT  91.829 49.68 92.117 51.72 ;
     RECT  92.077 54.816 92.153 55.224 ;
     RECT  92.153 54.912 92.185 55.224 ;
     RECT  92.117 49.68 92.261 51.24 ;
     RECT  92.113 53.472 92.339 53.496 ;
     RECT  92.261 49.68 92.441 51.048 ;
     RECT  92.185 54.912 92.509 55.464 ;
     RECT  91.901 56.496 92.509 59.784 ;
     RECT  92.441 50.352 92.657 51.048 ;
     RECT  92.509 54.912 92.729 59.784 ;
     RECT  92.833 2.88 93.445 2.904 ;
     RECT  92.117 3.888 93.445 31.224 ;
     RECT  93.445 2.88 94.208 31.224 ;
     RECT  92.729 54.912 94.208 59.112 ;
     RECT  94.208 2.148 94.312 62.652 ;
     RECT  94.312 2.418 94.504 62.382 ;
     RECT  94.504 56.016 94.529 57.096 ;
     RECT  94.504 2.88 94.637 31.272 ;
     RECT  94.529 56.496 94.673 57.096 ;
     RECT  94.673 56.544 95.105 57.096 ;
     RECT  94.637 2.88 95.789 31.176 ;
     RECT  95.105 56.544 95.861 56.568 ;
     RECT  95.789 2.88 96.041 15.624 ;
     RECT  96.041 2.88 96.113 15.576 ;
     RECT  96.865 56.544 96.977 56.568 ;
     RECT  96.113 2.88 97.297 15.48 ;
     RECT  95.789 16.656 97.297 31.176 ;
     RECT  97.297 2.88 97.379 31.176 ;
     RECT  97.379 2.88 97.409 30.984 ;
     RECT  97.409 12.288 97.517 30.984 ;
     RECT  97.517 12.384 97.553 30.984 ;
     RECT  97.553 12.576 98.021 30.984 ;
     RECT  97.409 2.88 98.093 11.208 ;
     RECT  98.021 16.272 98.165 30.984 ;
     RECT  94.561 1.392 98.243 1.416 ;
     RECT  98.021 12.576 98.581 15.24 ;
     RECT  98.485 0.096 98.725 0.12 ;
     RECT  98.093 3.408 99.025 11.208 ;
     RECT  98.581 12.528 99.025 15.24 ;
     RECT  98.165 16.272 99.025 30.936 ;
     RECT  99.025 3.408 99.349 11.448 ;
     RECT  99.025 12.528 99.349 30.936 ;
     RECT  98.725 0.096 99.353 1.176 ;
     RECT  99.277 2.304 99.608 2.328 ;
     RECT  99.349 3.408 99.608 30.936 ;
     RECT  99.608 2.148 99.712 62.652 ;
     RECT  99.712 2.418 99.904 62.382 ;
     RECT  99.353 0.096 100.181 0.6 ;
     RECT  99.904 3.408 100.253 6.408 ;
     RECT  100.181 0.48 100.693 0.6 ;
     RECT  99.904 7.44 100.721 30.936 ;
     RECT  100.693 0.48 100.979 1.176 ;
     RECT  100.721 7.44 100.979 21.192 ;
     RECT  100.253 3.84 101.221 6.408 ;
     RECT  100.979 14.832 101.369 21.192 ;
     RECT  101.221 2.88 101.441 6.408 ;
     RECT  101.369 19.248 101.477 21.192 ;
     RECT  100.979 1.152 101.509 1.176 ;
     RECT  100.721 22.8 101.513 30.936 ;
     RECT  101.369 14.832 102.301 18.216 ;
     RECT  100.979 7.44 102.409 13.656 ;
     RECT  101.477 19.344 102.409 21.192 ;
     RECT  101.513 22.8 102.409 30.792 ;
     RECT  101.509 1.152 102.413 1.224 ;
     RECT  102.409 7.392 102.449 13.656 ;
     RECT  102.449 9.024 102.517 13.656 ;
     RECT  102.301 14.64 102.517 18.216 ;
     RECT  101.441 3.408 102.589 6.408 ;
     RECT  102.589 2.88 102.613 6.408 ;
     RECT  102.409 19.344 102.629 30.792 ;
     RECT  102.517 9.024 102.665 18.216 ;
     RECT  102.413 1.152 102.737 1.176 ;
     RECT  102.665 12.336 102.737 18.216 ;
     RECT  102.613 2.304 102.845 6.408 ;
     RECT  102.845 3.312 102.877 6.408 ;
     RECT  102.449 7.392 102.877 7.752 ;
     RECT  101.797 0.096 103.141 0.12 ;
     RECT  102.629 19.344 103.277 30.36 ;
     RECT  103.277 19.344 103.313 22.056 ;
     RECT  103.277 23.376 103.313 30.36 ;
     RECT  102.913 18.24 103.453 18.264 ;
     RECT  103.313 19.344 103.453 19.944 ;
     RECT  103.141 0.096 103.475 0.6 ;
     RECT  103.313 21.168 103.529 22.056 ;
     RECT  102.665 9.024 103.633 11.256 ;
     RECT  102.737 12.336 103.633 16.872 ;
     RECT  103.313 23.52 103.637 30.36 ;
     RECT  103.633 9.024 103.82 16.872 ;
     RECT  103.82 8.88 103.907 16.872 ;
     RECT  103.717 1.152 104.245 1.176 ;
     RECT  103.453 18.24 104.245 19.944 ;
     RECT  102.845 2.304 104.317 2.328 ;
     RECT  102.877 3.312 104.317 7.752 ;
     RECT  104.245 18.192 104.353 19.944 ;
     RECT  103.529 21.168 104.353 21.192 ;
     RECT  103.705 46.128 104.389 46.152 ;
     RECT  103.813 62.16 104.389 62.184 ;
     RECT  104.353 18.192 104.497 21.192 ;
     RECT  104.245 1.152 104.501 1.272 ;
     RECT  104.501 1.248 104.537 1.272 ;
     RECT  103.907 9.024 104.569 16.872 ;
     RECT  104.317 2.304 104.605 7.896 ;
     RECT  104.497 18.192 104.785 21.48 ;
     RECT  104.605 1.728 104.867 7.896 ;
     RECT  104.867 2.148 104.869 7.896 ;
     RECT  104.569 9.024 104.893 16.92 ;
     RECT  104.785 18.192 104.893 21.528 ;
     RECT  104.869 2.148 105.008 8.04 ;
     RECT  104.893 9.024 105.008 21.528 ;
     RECT  103.637 23.52 105.008 23.544 ;
     RECT  103.637 24.528 105.008 30.36 ;
     RECT  104.029 36.528 105.008 36.552 ;
     RECT  104.425 40.128 105.008 40.152 ;
     RECT  103.921 41.76 105.008 41.784 ;
     RECT  104.389 45.696 105.008 46.152 ;
     RECT  104.065 51.36 105.008 51.384 ;
     RECT  104.713 55.248 105.008 55.272 ;
     RECT  104.209 56.88 105.008 56.904 ;
     RECT  104.389 59.808 105.008 60.744 ;
     RECT  104.389 62.16 105.008 62.28 ;
     RECT  105.008 2.148 105.112 62.652 ;
     RECT  105.112 2.148 105.304 62.382 ;
     RECT  103.475 0.096 105.317 0.12 ;
     RECT  105.317 0.096 105.401 0.168 ;
     RECT  105.304 3.408 105.437 6.84 ;
     RECT  105.304 40.128 105.491 40.44 ;
     RECT  105.304 10.032 105.539 21.672 ;
     RECT  105.304 23.088 105.731 27.336 ;
     RECT  105.304 28.416 105.905 30.36 ;
     RECT  105.304 8.016 106.049 9.048 ;
     RECT  105.539 10.032 106.049 18.744 ;
     RECT  105.304 33.936 106.067 33.96 ;
     RECT  105.304 35.28 106.067 35.304 ;
     RECT  105.304 36.528 106.067 36.552 ;
     RECT  105.304 44.16 106.067 44.184 ;
     RECT  105.304 45.696 106.067 45.72 ;
     RECT  105.304 50.736 106.067 51.384 ;
     RECT  105.304 54.288 106.067 56.904 ;
     RECT  105.437 3.408 106.085 6.648 ;
     RECT  105.304 49.392 106.108 49.416 ;
     RECT  105.304 59.808 106.113 59.832 ;
     RECT  106.085 3.6 106.229 6.408 ;
     RECT  106.067 54.288 106.307 55.848 ;
     RECT  105.401 0.096 106.405 0.12 ;
     RECT  105.539 21.648 106.405 21.672 ;
     RECT  105.539 19.776 106.445 20.568 ;
     RECT  106.405 21.648 106.445 21.816 ;
     RECT  105.491 40.128 106.508 40.152 ;
     RECT  105.905 29.28 106.513 30.36 ;
     RECT  106.445 20.496 106.517 20.568 ;
     RECT  106.049 14.736 106.549 18.744 ;
     RECT  105.731 25.776 106.549 27.336 ;
     RECT  106.517 20.544 106.589 20.568 ;
     RECT  105.304 39.12 106.595 39.144 ;
     RECT  106.508 40.128 106.595 40.488 ;
     RECT  105.304 41.76 106.595 41.784 ;
     RECT  106.049 8.88 106.621 9.048 ;
     RECT  106.049 10.032 106.621 13.656 ;
     RECT  105.731 23.088 106.625 24.552 ;
     RECT  106.513 29.28 106.643 30.744 ;
     RECT  106.405 0.096 106.697 0.552 ;
     RECT  106.445 21.792 106.801 21.816 ;
     RECT  106.625 23.088 106.801 23.544 ;
     RECT  106.621 8.88 106.877 13.656 ;
     RECT  106.549 14.736 106.877 19.416 ;
     RECT  106.877 17.472 106.949 19.416 ;
     RECT  106.949 17.472 106.979 18.984 ;
     RECT  105.925 1.728 107.021 1.752 ;
     RECT  106.979 17.472 107.021 18.744 ;
     RECT  105.304 62.256 107.021 62.28 ;
     RECT  106.877 9.168 107.053 13.656 ;
     RECT  106.877 14.736 107.053 16.104 ;
     RECT  106.549 25.776 107.125 28.056 ;
     RECT  106.643 29.28 107.125 30.36 ;
     RECT  107.125 25.776 107.201 30.36 ;
     RECT  107.201 25.776 107.219 30.168 ;
     RECT  107.053 9.168 107.237 16.104 ;
     RECT  106.801 21.792 107.237 23.544 ;
     RECT  107.219 30.048 107.273 30.168 ;
     RECT  107.237 13.344 107.309 15.864 ;
     RECT  107.237 9.168 107.453 12.36 ;
     RECT  107.219 25.776 107.561 28.488 ;
     RECT  107.453 10.272 107.651 12.36 ;
     RECT  107.309 13.344 107.669 15.768 ;
     RECT  107.237 21.792 107.669 23.352 ;
     RECT  106.597 32.496 107.669 32.52 ;
     RECT  105.304 37.584 107.669 37.608 ;
     RECT  105.304 42.768 107.669 42.792 ;
     RECT  105.304 47.856 107.669 47.88 ;
     RECT  105.304 53.04 107.669 53.064 ;
     RECT  105.304 58.128 107.669 58.152 ;
     RECT  106.741 0.576 107.741 0.6 ;
     RECT  106.229 4.512 107.741 6.408 ;
     RECT  107.021 17.472 107.741 17.496 ;
     RECT  107.669 22.656 107.741 23.352 ;
     RECT  107.561 25.776 107.741 27.336 ;
     RECT  107.021 18.72 107.777 18.744 ;
     RECT  107.651 10.272 107.836 10.632 ;
     RECT  107.741 22.656 107.849 23.112 ;
     RECT  107.741 4.56 107.993 6.408 ;
     RECT  107.669 13.344 108.101 14.424 ;
     RECT  107.669 15.456 108.101 15.768 ;
     RECT  107.273 30.144 108.101 30.168 ;
     RECT  107.701 3.408 108.173 3.432 ;
     RECT  107.701 24.528 108.173 24.552 ;
     RECT  107.269 7.968 108.229 7.992 ;
     RECT  107.453 9.168 108.229 9.192 ;
     RECT  108.229 7.968 108.275 9.192 ;
     RECT  108.101 14.4 108.389 14.424 ;
     RECT  108.275 7.968 108.425 9 ;
     RECT  107.741 25.92 108.569 27.336 ;
     RECT  107.651 11.904 108.605 12.36 ;
     RECT  108.101 13.344 108.641 13.368 ;
     RECT  108.101 15.456 108.713 15.48 ;
     RECT  107.849 22.656 108.713 22.68 ;
     RECT  107.993 4.992 108.749 6.408 ;
     RECT  107.836 10.608 108.785 10.632 ;
     RECT  108.569 25.92 108.821 25.944 ;
     RECT  108.313 18.528 108.857 18.552 ;
     RECT  108.749 4.992 108.893 5.88 ;
     RECT  108.425 8.976 108.965 9 ;
     RECT  107.561 28.464 108.965 28.488 ;
     RECT  108.569 27.312 109.001 27.336 ;
     RECT  108.605 11.904 109.037 11.928 ;
     RECT  108.893 4.992 109.073 5.832 ;
     RECT  108.805 3.936 109.141 3.96 ;
     RECT  109.141 3.648 109.381 3.96 ;
     RECT  109.381 2.688 109.397 3.96 ;
     RECT  109.397 2.688 109.427 3.672 ;
     RECT  109.073 5.328 109.613 5.832 ;
     RECT  109.427 2.688 109.721 2.712 ;
     RECT  109.613 5.472 109.721 5.832 ;
     RECT  109.721 5.808 110.081 5.832 ;
     RECT  110.509 1.632 112.284 1.656 ;
     RECT  112.201 2.928 112.284 2.952 ;
     RECT  111.121 4.176 112.284 4.2 ;
     RECT  112.201 5.472 112.284 5.496 ;
     RECT  111.157 6.768 112.284 6.792 ;
     RECT  111.157 8.016 112.284 8.04 ;
     RECT  111.121 9.312 112.284 9.336 ;
     RECT  110.041 10.608 112.284 10.632 ;
     RECT  111.121 11.904 112.284 11.928 ;
     RECT  111.157 13.152 112.284 13.176 ;
     RECT  111.121 14.448 112.284 14.472 ;
     RECT  111.121 15.744 112.284 15.768 ;
     RECT  110.581 16.992 112.284 17.016 ;
     RECT  111.121 18.288 112.284 18.312 ;
     RECT  110.581 19.584 112.284 19.608 ;
     RECT  111.121 20.832 112.284 20.856 ;
     RECT  110.581 22.128 112.284 22.152 ;
     RECT  110.545 23.424 112.284 23.448 ;
     RECT  111.121 24.72 112.284 24.744 ;
     RECT  111.121 25.968 112.284 25.992 ;
     RECT  111.121 27.264 112.284 27.288 ;
     RECT  111.157 28.56 112.284 28.584 ;
     RECT  110.581 29.808 112.284 29.832 ;
     RECT  111.121 31.104 112.284 31.128 ;
     RECT  111.121 32.4 112.284 32.424 ;
     RECT  110.581 33.648 112.284 33.672 ;
     RECT  110.545 34.944 112.284 34.968 ;
     RECT  112.201 36.24 112.284 36.264 ;
     RECT  111.121 37.536 112.284 37.56 ;
     RECT  111.697 38.784 112.284 38.808 ;
     RECT  110.545 40.08 112.284 40.104 ;
     RECT  110.545 41.376 112.284 41.4 ;
     RECT  111.121 42.624 112.284 42.648 ;
     RECT  110.545 43.92 112.284 43.944 ;
     RECT  109.969 45.216 112.284 45.24 ;
     RECT  109.969 46.464 112.284 46.488 ;
     RECT  111.121 47.76 112.284 47.784 ;
     RECT  110.581 49.056 112.284 49.08 ;
     RECT  111.121 50.352 112.284 50.376 ;
     RECT  111.121 51.6 112.284 51.624 ;
     RECT  110.545 52.896 112.284 52.92 ;
     RECT  111.121 54.192 112.284 54.216 ;
     RECT  109.969 55.44 112.284 55.464 ;
     RECT  111.121 56.736 112.284 56.76 ;
     RECT  110.545 58.032 112.284 58.056 ;
     RECT  111.121 59.28 112.284 59.304 ;
     RECT  109.969 60.576 112.284 60.6 ;
     RECT  112.201 61.872 112.284 61.896 ;
     RECT  111.121 63.168 112.284 63.192 ;
    LAYER M5 ;
     RECT  98.208 0.016 106.776 0.179 ;
     RECT  3.888 0.037 5.064 0.517 ;
     RECT  98.208 0.179 104.856 0.611 ;
     RECT  105.936 0.179 106.776 0.611 ;
     RECT  27.6 0.016 36.168 1.187 ;
     RECT  45.264 0.016 53.832 1.187 ;
     RECT  80.544 0.016 89.112 1.187 ;
     RECT  98.208 0.611 99.336 1.187 ;
     RECT  100.704 0.611 104.856 1.187 ;
     RECT  101.232 1.187 103.272 1.235 ;
     RECT  104.256 1.187 104.856 1.283 ;
     RECT  98.208 1.187 98.232 1.427 ;
     RECT  9.936 0.016 18.504 1.763 ;
     RECT  27.6 1.187 29.52 1.763 ;
     RECT  30.624 1.187 36.168 1.763 ;
     RECT  45.264 1.187 47.496 1.763 ;
     RECT  48.576 1.187 53.832 1.763 ;
     RECT  62.928 0.016 71.496 1.763 ;
     RECT  80.544 1.187 80.568 1.763 ;
     RECT  81.648 1.187 89.112 1.763 ;
     RECT  104.832 1.283 104.856 1.763 ;
     RECT  105.936 0.611 105.96 1.763 ;
     RECT  34.8 1.763 35.88 1.811 ;
     RECT  45.552 1.763 45.912 1.811 ;
     RECT  47.184 1.763 47.208 1.811 ;
     RECT  48.816 1.763 49.416 1.811 ;
     RECT  64.272 1.763 64.296 1.811 ;
     RECT  67.2 1.763 68.184 1.811 ;
     RECT  69.792 1.763 69.816 1.811 ;
     RECT  82.464 1.763 85.272 1.811 ;
     RECT  18.24 1.763 18.504 2.137 ;
     RECT  99.312 1.187 99.336 2.137 ;
     RECT  2.4 2.137 2.52 2.151 ;
     RECT  7.8 2.137 7.92 2.151 ;
     RECT  18.24 2.137 18.72 2.151 ;
     RECT  24 2.137 24.12 2.151 ;
     RECT  28.416 1.763 29.52 2.151 ;
     RECT  40.2 2.137 40.32 2.151 ;
     RECT  56.4 2.137 56.52 2.151 ;
     RECT  61.8 2.137 61.92 2.151 ;
     RECT  72.6 2.137 72.72 2.151 ;
     RECT  78 2.137 78.12 2.151 ;
     RECT  94.2 2.137 94.32 2.151 ;
     RECT  99.312 2.137 99.72 2.151 ;
     RECT  18.24 2.151 18.912 2.291 ;
     RECT  99.312 2.151 99.912 2.339 ;
     RECT  102.624 1.235 103.272 2.339 ;
     RECT  2.4 2.151 2.712 2.629 ;
     RECT  3.888 0.517 5.304 2.629 ;
     RECT  2.4 2.629 5.304 2.725 ;
     RECT  67.2 1.811 67.512 2.821 ;
     RECT  10.32 1.763 10.536 2.915 ;
     RECT  12.72 1.763 14.376 2.915 ;
     RECT  28.416 2.151 29.712 2.915 ;
     RECT  32.304 1.763 32.328 2.915 ;
     RECT  48.816 1.811 48.84 2.915 ;
     RECT  50.592 1.763 53.544 2.915 ;
     RECT  83.232 1.811 84.456 2.915 ;
     RECT  101.232 1.235 101.256 2.915 ;
     RECT  71.184 1.763 71.208 3.107 ;
     RECT  105 2.137 105.312 3.109 ;
     RECT  13.2 2.915 14.376 3.299 ;
     RECT  10.32 2.915 10.344 3.395 ;
     RECT  7.8 2.151 8.112 3.397 ;
     RECT  40.2 2.151 40.512 3.397 ;
     RECT  99.6 2.339 99.912 3.397 ;
     RECT  50.592 2.915 51.432 3.443 ;
     RECT  21.408 2.245 21.432 3.539 ;
     RECT  34.8 1.811 35.112 3.541 ;
     RECT  39.84 3.397 40.512 3.637 ;
     RECT  109.392 2.677 109.416 3.683 ;
     RECT  94.2 2.151 94.512 3.877 ;
     RECT  61.8 2.151 62.112 3.925 ;
     RECT  80.928 3.397 80.952 3.925 ;
     RECT  99.12 3.397 99.912 3.925 ;
     RECT  94.08 3.877 94.512 3.973 ;
     RECT  39.84 3.637 40.776 4.019 ;
     RECT  70.656 3.397 70.68 4.067 ;
     RECT  2.4 2.725 6.168 4.115 ;
     RECT  61.296 3.925 62.112 4.213 ;
     RECT  45.6 1.811 45.912 4.309 ;
     RECT  31.728 4.021 31.752 4.403 ;
     RECT  103.248 2.339 103.272 4.405 ;
     RECT  13.2 3.299 13.512 4.453 ;
     RECT  45.6 4.309 46.008 4.453 ;
     RECT  94.08 3.973 94.68 4.499 ;
     RECT  24 2.151 24.312 4.501 ;
     RECT  50.592 3.443 51.312 4.501 ;
     RECT  40.2 4.019 40.776 4.597 ;
     RECT  54.672 4.213 54.696 4.643 ;
     RECT  7.68 3.397 8.112 4.645 ;
     RECT  23.328 4.501 24.312 4.645 ;
     RECT  64.56 3.925 64.584 4.691 ;
     RECT  6.144 4.115 6.168 4.739 ;
     RECT  40.2 4.597 41.016 4.739 ;
     RECT  45.504 4.453 46.008 4.931 ;
     RECT  16.56 3.877 16.584 4.979 ;
     RECT  7.44 4.645 8.112 4.981 ;
     RECT  28.032 4.693 28.056 5.077 ;
     RECT  29.4 2.915 29.712 5.077 ;
     RECT  34.8 3.541 35.88 5.077 ;
     RECT  61.2 4.213 62.112 5.077 ;
     RECT  103.152 4.405 103.272 5.077 ;
     RECT  23.328 4.645 24.408 5.125 ;
     RECT  18.6 2.291 18.912 5.173 ;
     RECT  28.032 5.077 29.712 5.173 ;
     RECT  61.2 5.077 62.76 5.219 ;
     RECT  23.328 5.125 24.504 5.221 ;
     RECT  59.232 4.645 59.256 5.221 ;
     RECT  18.6 5.173 19.128 5.315 ;
     RECT  41.712 4.933 41.736 5.315 ;
     RECT  82.032 4.261 82.056 5.315 ;
     RECT  69.504 4.885 69.528 5.461 ;
     RECT  88.8 1.763 89.112 5.461 ;
     RECT  18.6 5.315 18.912 5.557 ;
     RECT  56.4 2.151 56.712 5.557 ;
     RECT  13.056 4.453 13.512 5.603 ;
     RECT  50.016 4.501 51.312 5.653 ;
     RECT  21.072 5.173 21.096 5.699 ;
     RECT  28.032 5.173 30.264 5.747 ;
     RECT  49.296 5.653 51.312 5.747 ;
     RECT  80.208 3.925 80.952 5.747 ;
     RECT  98.64 3.925 99.912 5.747 ;
     RECT  108.816 3.925 108.84 5.747 ;
     RECT  67.2 2.821 67.704 5.795 ;
     RECT  69.36 5.461 69.528 5.845 ;
     RECT  28.464 5.747 30.264 5.891 ;
     RECT  34.8 5.077 36.024 5.891 ;
     RECT  31.392 5.701 31.416 5.939 ;
     RECT  6.864 4.981 8.112 5.941 ;
     RECT  102.432 5.077 103.272 5.941 ;
     RECT  102.048 5.941 103.896 5.987 ;
     RECT  23.328 5.221 24.744 5.989 ;
     RECT  102.048 5.987 102.072 6.083 ;
     RECT  23.328 5.989 25.416 6.131 ;
     RECT  69.36 5.845 70.008 6.133 ;
     RECT  33.6 6.085 33.624 6.181 ;
     RECT  2.4 4.115 4.968 6.229 ;
     RECT  74.4 5.701 74.424 6.229 ;
     RECT  75.408 4.645 75.432 6.229 ;
     RECT  69.36 6.133 70.152 6.277 ;
     RECT  49.296 5.747 49.32 6.323 ;
     RECT  103.248 5.987 103.896 6.323 ;
     RECT  99.168 5.747 99.912 6.371 ;
     RECT  78 2.151 78.312 6.373 ;
     RECT  29.4 5.891 30.264 6.421 ;
     RECT  56.4 5.557 57.192 6.469 ;
     RECT  77.424 6.373 78.312 6.515 ;
     RECT  74.4 6.229 75.432 6.563 ;
     RECT  59.232 5.221 59.496 6.661 ;
     RECT  11.28 5.605 11.304 6.757 ;
     RECT  18.192 5.557 18.912 6.757 ;
     RECT  6.192 5.941 8.112 6.803 ;
     RECT  11.28 6.757 11.928 6.803 ;
     RECT  45.6 4.931 46.008 6.805 ;
     RECT  58.704 6.661 59.496 6.805 ;
     RECT  43.68 3.877 43.704 6.851 ;
     RECT  58.704 6.805 59.832 6.851 ;
     RECT  68.928 6.277 70.152 6.899 ;
     RECT  59.232 6.851 59.832 6.995 ;
     RECT  90.912 6.805 90.936 6.997 ;
     RECT  67.2 5.795 67.512 7.189 ;
     RECT  68.928 6.899 70.008 7.189 ;
     RECT  77.904 6.515 78.312 7.189 ;
     RECT  33.552 6.181 33.624 7.235 ;
     RECT  72.6 2.151 72.912 7.237 ;
     RECT  74.832 6.563 75.432 7.237 ;
     RECT  2.4 6.229 5.112 7.333 ;
     RECT  94.08 4.499 94.512 7.379 ;
     RECT  9.792 5.797 9.816 7.381 ;
     RECT  29.4 6.421 30.552 7.381 ;
     RECT  61.2 5.219 62.112 7.381 ;
     RECT  96 6.037 96.024 7.381 ;
     RECT  48.48 6.805 48.504 7.475 ;
     RECT  59.232 6.995 59.256 7.475 ;
     RECT  96 7.381 96.312 7.525 ;
     RECT  71.424 7.429 71.448 7.667 ;
     RECT  91.968 6.853 91.992 7.667 ;
     RECT  96 7.525 97.032 7.715 ;
     RECT  44.976 6.805 46.008 7.763 ;
     RECT  56.4 6.469 57.288 7.765 ;
     RECT  20.976 7.717 21 7.861 ;
     RECT  103.872 6.323 103.896 7.861 ;
     RECT  104.88 3.109 105.312 7.861 ;
     RECT  11.904 6.803 11.928 7.907 ;
     RECT  20.88 7.861 21 7.907 ;
     RECT  88.8 5.461 89.208 7.909 ;
     RECT  72.6 7.237 73.416 7.955 ;
     RECT  74.832 7.237 75.864 7.955 ;
     RECT  77.904 7.189 79.368 7.955 ;
     RECT  42.768 7.381 42.792 8.003 ;
     RECT  78 7.955 79.368 8.003 ;
     RECT  26.304 7.381 26.328 8.149 ;
     RECT  84.96 7.381 84.984 8.195 ;
     RECT  2.4 7.333 5.496 8.243 ;
     RECT  20.88 7.907 20.904 8.291 ;
     RECT  23.328 6.131 25.128 8.291 ;
     RECT  34.8 5.891 35.208 8.389 ;
     RECT  65.136 6.805 65.16 8.435 ;
     RECT  61.008 7.381 62.112 8.437 ;
     RECT  52.608 4.501 52.632 8.485 ;
     RECT  74.832 7.955 75.672 8.485 ;
     RECT  56.4 7.765 57.768 8.531 ;
     RECT  88.8 7.909 89.592 8.531 ;
     RECT  40.2 4.739 40.512 8.533 ;
     RECT  96 7.715 96.312 8.579 ;
     RECT  23.328 8.291 24.456 8.723 ;
     RECT  99.6 6.371 99.912 8.725 ;
     RECT  13.2 5.603 13.512 8.773 ;
     RECT  34.8 8.389 35.256 8.819 ;
     RECT  99.264 8.725 99.912 8.867 ;
     RECT  81.84 6.805 81.864 8.869 ;
     RECT  33.552 7.235 33.576 8.963 ;
     RECT  26.304 8.149 26.808 9.011 ;
     RECT  13.2 8.773 14.28 9.013 ;
     RECT  21.072 8.869 21.096 9.059 ;
     RECT  29.4 7.381 31.224 9.059 ;
     RECT  52.608 8.485 53.592 9.059 ;
     RECT  67.2 7.189 70.008 9.061 ;
     RECT  29.4 9.059 30.264 9.155 ;
     RECT  34.8 8.819 35.208 9.155 ;
     RECT  66.48 9.061 70.008 9.155 ;
     RECT  108.24 8.485 108.264 9.157 ;
     RECT  10.848 9.013 10.872 9.203 ;
     RECT  107.76 9.157 108.264 9.203 ;
     RECT  102.048 8.485 102.072 9.251 ;
     RECT  7.104 6.803 8.112 9.253 ;
     RECT  50.592 5.747 51.312 9.301 ;
     RECT  52.608 9.059 52.632 9.347 ;
     RECT  7.104 9.253 8.232 9.349 ;
     RECT  9.696 7.381 9.816 9.349 ;
     RECT  88.8 8.531 89.448 9.349 ;
     RECT  7.104 9.349 9.816 9.397 ;
     RECT  83.4 2.915 83.712 9.493 ;
     RECT  6.48 9.397 9.816 9.539 ;
     RECT  13.2 9.013 14.664 9.541 ;
     RECT  26.784 9.011 26.808 9.541 ;
     RECT  74.688 8.485 75.672 9.587 ;
     RECT  34.8 9.155 35.112 9.589 ;
     RECT  83.28 9.493 83.712 9.635 ;
     RECT  72.6 7.955 72.912 9.637 ;
     RECT  66.48 9.155 69.384 9.731 ;
     RECT  103.872 7.861 105.312 9.827 ;
     RECT  78 8.003 78.936 10.069 ;
     RECT  20.832 9.397 20.856 10.117 ;
     RECT  26.784 9.541 26.904 10.163 ;
     RECT  88.368 9.349 89.448 10.163 ;
     RECT  6.48 9.539 8.112 10.307 ;
     RECT  9.12 9.539 9.816 10.307 ;
     RECT  66.48 9.731 68.808 10.307 ;
     RECT  74.832 9.587 75.672 10.307 ;
     RECT  107.76 9.203 107.784 10.307 ;
     RECT  2.4 8.243 4.968 10.355 ;
     RECT  34.224 9.589 35.112 10.357 ;
     RECT  39.936 8.533 40.512 10.405 ;
     RECT  13.104 9.541 14.664 10.595 ;
     RECT  50.256 9.301 51.312 10.597 ;
     RECT  99.6 8.867 99.912 10.597 ;
     RECT  58.656 10.261 58.68 10.643 ;
     RECT  60.24 8.437 62.112 10.643 ;
     RECT  61.008 10.643 62.112 10.741 ;
     RECT  63.408 9.637 63.432 10.741 ;
     RECT  105 9.827 105.312 10.741 ;
     RECT  16.512 10.693 16.536 10.789 ;
     RECT  72.336 9.637 72.912 10.789 ;
     RECT  77.568 10.069 78.936 10.789 ;
     RECT  56.4 8.531 57.384 10.837 ;
     RECT  13.104 10.595 14.28 10.883 ;
     RECT  20.832 10.117 21.816 10.883 ;
     RECT  61.008 10.741 63.432 10.883 ;
     RECT  74.976 10.307 75.672 10.883 ;
     RECT  83.4 9.635 83.712 10.885 ;
     RECT  34.224 10.357 35.976 10.931 ;
     RECT  7.632 10.307 8.112 10.933 ;
     RECT  9.12 10.307 9.144 10.933 ;
     RECT  2.4 10.355 2.712 10.981 ;
     RECT  6.48 10.307 6.504 11.027 ;
     RECT  39.312 10.405 40.512 11.029 ;
     RECT  42.24 10.981 42.264 11.029 ;
     RECT  50.256 10.597 51.432 11.075 ;
     RECT  77.568 10.789 79.608 11.077 ;
     RECT  34.8 10.931 35.976 11.171 ;
     RECT  77.04 11.077 79.608 11.173 ;
     RECT  99.504 10.597 99.912 11.173 ;
     RECT  87.408 11.125 87.432 11.267 ;
     RECT  88.8 10.163 89.448 11.365 ;
     RECT  90.864 6.997 90.936 11.365 ;
     RECT  44.976 7.763 45.912 11.411 ;
     RECT  88.8 11.365 90.936 11.413 ;
     RECT  91.92 8.821 91.944 11.413 ;
     RECT  72.336 10.789 73.08 11.459 ;
     RECT  88.8 11.413 91.944 11.459 ;
     RECT  96 8.579 96.024 11.459 ;
     RECT  103.872 9.827 103.896 11.459 ;
     RECT  105 10.741 105.432 11.459 ;
     RECT  26.88 10.163 26.904 11.605 ;
     RECT  16.464 10.789 16.536 11.651 ;
     RECT  72.48 11.459 73.08 11.653 ;
     RECT  74.976 10.883 75.048 11.653 ;
     RECT  77.04 11.173 79.8 11.653 ;
     RECT  39.312 11.029 42.264 11.699 ;
     RECT  72.48 11.653 75.048 11.699 ;
     RECT  76.896 11.653 79.8 11.699 ;
     RECT  70.464 9.397 70.488 11.701 ;
     RECT  88.8 11.459 91.848 11.701 ;
     RECT  7.632 10.933 9.144 11.747 ;
     RECT  39.312 11.699 41.352 11.747 ;
     RECT  14.496 11.653 14.52 11.749 ;
     RECT  43.248 8.725 43.272 11.749 ;
     RECT  7.632 11.747 9 11.795 ;
     RECT  14.496 11.749 14.808 11.795 ;
     RECT  79.776 11.699 79.8 11.795 ;
     RECT  86.208 11.653 86.232 11.795 ;
     RECT  88.704 11.701 91.848 11.843 ;
     RECT  37.632 10.165 37.656 11.891 ;
     RECT  32.736 11.797 32.76 11.939 ;
     RECT  4.32 10.355 4.872 11.941 ;
     RECT  29.4 9.155 29.712 11.941 ;
     RECT  2.304 10.981 2.712 12.035 ;
     RECT  18 6.757 18.912 12.035 ;
     RECT  106.848 10.405 107.64 12.035 ;
     RECT  4.32 11.941 5.256 12.083 ;
     RECT  7.8 11.795 9 12.083 ;
     RECT  11.424 10.549 11.448 12.179 ;
     RECT  34.8 11.171 35.688 12.277 ;
     RECT  58.752 11.845 58.776 12.323 ;
     RECT  83.28 10.885 83.712 12.325 ;
     RECT  100.896 10.741 100.92 12.325 ;
     RECT  4.848 12.083 5.256 12.467 ;
     RECT  34.8 12.277 35.832 12.467 ;
     RECT  45.6 11.411 45.912 12.469 ;
     RECT  72.48 11.699 72.912 12.469 ;
     RECT  50.256 11.075 51.312 12.515 ;
     RECT  34.8 12.467 35.688 12.517 ;
     RECT  99.168 11.173 99.912 12.517 ;
     RECT  13.104 10.883 13.512 12.611 ;
     RECT  23.328 8.723 24.408 12.611 ;
     RECT  26.352 11.605 26.904 12.611 ;
     RECT  45.504 12.469 45.912 12.611 ;
     RECT  74.016 11.699 74.04 12.755 ;
     RECT  26.736 12.611 26.904 12.803 ;
     RECT  63.84 11.941 64.632 12.851 ;
     RECT  29.088 11.941 29.712 12.899 ;
     RECT  81.264 8.869 81.864 12.997 ;
     RECT  92.832 11.941 92.856 12.997 ;
     RECT  33.072 12.901 33.096 13.043 ;
     RECT  34.416 12.517 35.688 13.043 ;
     RECT  56.4 10.837 57.432 13.043 ;
     RECT  14.784 11.795 14.808 13.045 ;
     RECT  18.6 12.035 18.912 13.045 ;
     RECT  29.28 12.899 29.712 13.045 ;
     RECT  50.592 12.515 51.312 13.045 ;
     RECT  75.024 11.699 75.048 13.045 ;
     RECT  61.008 10.883 62.664 13.093 ;
     RECT  63.84 12.851 63.864 13.093 ;
     RECT  92.832 12.997 93.144 13.093 ;
     RECT  94.2 7.379 94.512 13.093 ;
     RECT  75.024 13.045 75.528 13.139 ;
     RECT  88.8 11.843 91.848 13.139 ;
     RECT  39.408 11.747 41.352 13.141 ;
     RECT  76.896 11.699 78.504 13.189 ;
     RECT  12.096 12.421 12.12 13.237 ;
     RECT  11.424 13.237 12.12 13.283 ;
     RECT  96.96 13.141 96.984 13.283 ;
     RECT  18.384 13.045 18.912 13.285 ;
     RECT  43.248 11.749 43.56 13.333 ;
     RECT  45.6 12.611 45.912 13.333 ;
     RECT  70.464 11.701 70.776 13.333 ;
     RECT  42.768 13.333 43.56 13.379 ;
     RECT  61.008 13.093 63.864 13.379 ;
     RECT  33.36 13.141 33.384 13.381 ;
     RECT  34.416 13.043 35.112 13.381 ;
     RECT  33.36 13.381 35.112 13.427 ;
     RECT  67.2 10.307 68.808 13.427 ;
     RECT  92.832 13.093 94.512 13.427 ;
     RECT  98.592 12.517 99.912 13.475 ;
     RECT  98.736 13.475 99.912 13.477 ;
     RECT  100.896 12.325 100.968 13.477 ;
     RECT  7.8 12.083 8.232 13.619 ;
     RECT  2.4 12.035 2.712 13.621 ;
     RECT  23.328 12.611 24.312 13.621 ;
     RECT  93.12 13.427 94.512 13.621 ;
     RECT  106.848 12.035 106.872 13.621 ;
     RECT  4.896 12.467 5.256 13.667 ;
     RECT  65.76 12.997 65.784 13.667 ;
     RECT  93.12 13.621 94.632 13.667 ;
     RECT  106.848 13.621 106.968 13.667 ;
     RECT  50.592 13.045 52.296 13.715 ;
     RECT  29.28 13.045 29.976 13.763 ;
     RECT  81.216 12.997 81.864 13.811 ;
     RECT  93.456 13.667 94.632 13.859 ;
     RECT  45.6 13.333 46.008 13.861 ;
     RECT  70.464 13.333 71.16 13.907 ;
     RECT  26.88 12.803 26.904 14.053 ;
     RECT  14.592 13.045 14.808 14.099 ;
     RECT  98.736 13.477 100.968 14.099 ;
     RECT  45.6 13.861 46.488 14.101 ;
     RECT  99.12 14.099 100.968 14.147 ;
     RECT  75.168 13.139 75.528 14.149 ;
     RECT  26.736 14.053 26.904 14.195 ;
     RECT  2.4 13.621 2.904 14.197 ;
     RECT  22.8 13.621 24.312 14.197 ;
     RECT  56.4 13.043 57.384 14.245 ;
     RECT  71.136 13.907 71.16 14.291 ;
     RECT  16.464 11.651 16.488 14.339 ;
     RECT  31.344 12.853 31.368 14.339 ;
     RECT  59.28 14.149 59.304 14.339 ;
     RECT  67.2 13.427 68.664 14.341 ;
     RECT  76.896 13.189 78.648 14.341 ;
     RECT  42.768 13.379 43.272 14.387 ;
     RECT  99.12 14.147 100.824 14.387 ;
     RECT  26.88 14.195 26.904 14.531 ;
     RECT  11.424 13.283 11.448 14.579 ;
     RECT  72.432 12.469 72.912 14.579 ;
     RECT  17.616 13.285 18.912 14.629 ;
     RECT  22.8 14.197 24.696 14.675 ;
     RECT  45.6 14.101 46.632 14.675 ;
     RECT  73.92 13.573 73.944 14.723 ;
     RECT  88.8 13.139 89.736 14.725 ;
     RECT  50.592 13.715 51.312 14.773 ;
     RECT  94.2 13.859 94.632 14.819 ;
     RECT  27.936 13.717 27.96 14.867 ;
     RECT  42.96 14.387 43.272 14.867 ;
     RECT  90.864 13.139 91.848 14.867 ;
     RECT  14.784 14.099 14.808 14.963 ;
     RECT  11.808 14.821 11.832 15.013 ;
     RECT  13.2 12.611 13.512 15.013 ;
     RECT  29.4 13.763 29.976 15.203 ;
     RECT  22.8 14.675 24.312 15.251 ;
     RECT  2.4 14.197 3.432 15.347 ;
     RECT  56.4 14.245 58.152 15.443 ;
     RECT  97.2 14.629 97.224 15.443 ;
     RECT  17.328 14.629 18.912 15.491 ;
     RECT  9.168 13.621 9.192 15.493 ;
     RECT  105 11.459 105.312 15.637 ;
     RECT  106.944 13.667 106.968 15.637 ;
     RECT  56.4 15.443 57.24 15.829 ;
     RECT  75.168 14.149 75.576 15.829 ;
     RECT  76.896 14.341 79.176 15.829 ;
     RECT  83.232 12.325 83.712 15.923 ;
     RECT  61.008 13.379 63.24 15.925 ;
     RECT  49.92 14.773 51.312 15.971 ;
     RECT  30.768 15.253 30.792 16.019 ;
     RECT  83.28 15.923 83.712 16.067 ;
     RECT  75.168 15.829 79.176 16.163 ;
     RECT  60.384 15.925 63.24 16.165 ;
     RECT  56.304 15.829 57.24 16.211 ;
     RECT  33.6 13.427 35.112 16.259 ;
     RECT  99.12 14.387 100.584 16.259 ;
     RECT  60.384 16.165 63.864 16.307 ;
     RECT  2.4 15.347 2.808 16.403 ;
     RECT  72.48 14.579 72.912 16.405 ;
     RECT  67.104 14.341 68.664 16.453 ;
     RECT  60.384 16.307 63.24 16.499 ;
     RECT  17.328 15.491 17.352 16.501 ;
     RECT  18.6 15.491 18.912 16.501 ;
     RECT  21.792 10.883 21.816 16.645 ;
     RECT  21.696 16.645 21.816 16.691 ;
     RECT  50.592 15.971 51.312 16.693 ;
     RECT  81.264 13.811 81.864 16.741 ;
     RECT  60.384 16.499 63.096 16.787 ;
     RECT  67.104 16.453 69 16.787 ;
     RECT  88.704 14.725 89.736 16.789 ;
     RECT  7.8 13.619 8.112 16.837 ;
     RECT  9.168 15.493 9.432 16.837 ;
     RECT  81.072 16.741 81.864 16.837 ;
     RECT  75.168 16.163 78.408 16.883 ;
     RECT  21.696 16.691 21.72 16.885 ;
     RECT  94.2 14.819 94.512 16.885 ;
     RECT  56.4 16.211 57.24 16.933 ;
     RECT  20.736 16.885 21.72 17.029 ;
     RECT  84.912 16.837 84.936 17.029 ;
     RECT  86.304 16.981 86.328 17.029 ;
     RECT  11.808 15.013 13.512 17.075 ;
     RECT  20.448 17.029 21.72 17.075 ;
     RECT  23.328 15.251 24.312 17.077 ;
     RECT  43.248 14.867 43.272 17.077 ;
     RECT  92.304 16.837 92.328 17.077 ;
     RECT  7.8 16.837 9.432 17.123 ;
     RECT  48.96 16.981 48.984 17.123 ;
     RECT  64.992 16.117 65.016 17.123 ;
     RECT  67.104 16.787 68.952 17.123 ;
     RECT  80.832 16.837 81.864 17.123 ;
     RECT  84.912 17.029 86.328 17.123 ;
     RECT  88.704 16.789 89.832 17.123 ;
     RECT  50.592 16.693 51.672 17.125 ;
     RECT  12 17.075 13.512 17.171 ;
     RECT  17.328 16.501 18.912 17.171 ;
     RECT  71.712 16.405 72.912 17.171 ;
     RECT  75.168 16.883 76.152 17.171 ;
     RECT  9.168 17.123 9.432 17.219 ;
     RECT  23.328 17.077 25.08 17.219 ;
     RECT  42.912 17.077 43.272 17.219 ;
     RECT  92.304 17.077 92.904 17.219 ;
     RECT  85.584 17.123 86.328 17.267 ;
     RECT  32.496 15.973 32.52 17.365 ;
     RECT  50.592 17.125 51.816 17.411 ;
     RECT  56.4 16.933 58.008 17.411 ;
     RECT  32.496 17.365 32.616 17.507 ;
     RECT  7.8 17.123 8.112 17.605 ;
     RECT  29.4 15.203 29.712 17.605 ;
     RECT  54 11.941 54.024 17.653 ;
     RECT  85.584 17.267 85.608 17.699 ;
     RECT  50.592 17.411 51.672 17.843 ;
     RECT  53.04 17.653 54.024 17.843 ;
     RECT  21.696 17.075 21.72 17.939 ;
     RECT  77.568 16.883 78.408 17.941 ;
     RECT  88.704 17.123 89.736 17.987 ;
     RECT  39.408 13.141 41.592 17.989 ;
     RECT  67.104 17.123 68.904 18.085 ;
     RECT  33.6 16.259 33.72 18.133 ;
     RECT  34.704 16.259 35.112 18.133 ;
     RECT  39.408 17.989 41.688 18.179 ;
     RECT  72.432 17.171 72.912 18.181 ;
     RECT  74.064 15.061 74.088 18.181 ;
     RECT  92.304 17.219 92.328 18.181 ;
     RECT  67.056 18.085 68.904 18.227 ;
     RECT  88.704 17.987 89.688 18.227 ;
     RECT  102.864 9.541 102.888 18.229 ;
     RECT  5.232 13.667 5.256 18.275 ;
     RECT  72.432 18.181 74.088 18.373 ;
     RECT  75.168 17.171 75.576 18.373 ;
     RECT  32.496 17.507 32.52 18.419 ;
     RECT  99.12 16.259 100.344 18.419 ;
     RECT  23.328 17.219 24.312 18.469 ;
     RECT  77.568 17.941 78.696 18.517 ;
     RECT  33.6 18.133 35.112 18.563 ;
     RECT  20.448 17.075 20.472 18.565 ;
     RECT  39.408 18.179 41.592 18.707 ;
     RECT  94.2 16.885 95.208 18.709 ;
     RECT  99.6 18.419 100.344 18.709 ;
     RECT  23.328 18.469 24.408 18.755 ;
     RECT  77.472 18.517 78.696 18.755 ;
     RECT  56.4 17.411 57.24 18.757 ;
     RECT  81.072 17.123 81.864 18.757 ;
     RECT  83.4 16.067 83.712 18.757 ;
     RECT  105 15.637 106.968 18.757 ;
     RECT  72.432 18.373 75.576 18.901 ;
     RECT  39.408 18.707 41.352 18.947 ;
     RECT  23.328 18.755 24.312 18.949 ;
     RECT  59.808 18.037 59.832 18.995 ;
     RECT  104.88 18.757 106.968 18.995 ;
     RECT  61.008 16.787 63.096 18.997 ;
     RECT  87.12 17.653 87.144 18.997 ;
     RECT  96.864 17.605 96.888 19.043 ;
     RECT  81.072 18.757 83.712 19.093 ;
     RECT  43.008 17.219 43.272 19.141 ;
     RECT  80.88 19.093 84.456 19.189 ;
     RECT  10.896 17.989 10.92 19.235 ;
     RECT  26.496 17.893 26.52 19.235 ;
     RECT  77.472 18.755 78.456 19.237 ;
     RECT  80.88 19.189 84.552 19.331 ;
     RECT  96.912 19.189 96.936 19.333 ;
     RECT  96.912 19.333 97.32 19.379 ;
     RECT  12 17.171 12.024 19.427 ;
     RECT  72.384 18.901 75.576 19.523 ;
     RECT  92.208 18.181 92.328 19.523 ;
     RECT  102.864 18.229 103.512 19.523 ;
     RECT  61.008 18.997 63.288 19.525 ;
     RECT  81.072 19.331 84.456 19.571 ;
     RECT  65.088 19.525 65.112 19.667 ;
     RECT  94.2 18.709 95.496 19.667 ;
     RECT  22.368 18.949 24.312 19.669 ;
     RECT  76.896 19.237 78.456 19.811 ;
     RECT  87.12 18.997 87.432 19.811 ;
     RECT  54 17.843 54.024 20.003 ;
     RECT  7.68 17.605 8.112 20.147 ;
     RECT  22.032 19.669 24.312 20.147 ;
     RECT  67.104 18.227 68.904 20.195 ;
     RECT  94.2 19.667 94.968 20.197 ;
     RECT  81.552 19.571 84.456 20.243 ;
     RECT  87.408 19.811 87.432 20.291 ;
     RECT  88.8 18.227 89.688 20.339 ;
     RECT  52.464 18.421 52.488 20.341 ;
     RECT  15.984 19.237 16.008 20.387 ;
     RECT  2.4 16.403 2.712 20.389 ;
     RECT  4.08 18.037 4.104 20.389 ;
     RECT  28.08 17.605 28.104 20.389 ;
     RECT  45.6 14.675 45.912 20.389 ;
     RECT  67.2 20.195 68.904 20.389 ;
     RECT  2.4 20.389 4.104 20.435 ;
     RECT  50.592 17.843 51.312 20.485 ;
     RECT  52.464 20.341 53.016 20.485 ;
     RECT  9.168 17.219 9.192 20.531 ;
     RECT  81.552 20.243 83.712 20.531 ;
     RECT  19.968 18.565 20.472 20.579 ;
     RECT  45.6 20.389 46.152 20.579 ;
     RECT  47.808 18.901 47.832 20.579 ;
     RECT  56.016 18.757 57.24 20.579 ;
     RECT  104.88 18.995 106.056 20.579 ;
     RECT  23.328 20.147 24.312 20.581 ;
     RECT  56.016 20.579 56.952 20.627 ;
     RECT  18.6 17.171 18.912 20.869 ;
     RECT  23.328 20.581 24.408 20.915 ;
     RECT  93.456 20.197 94.968 21.011 ;
     RECT  76.896 19.811 78.408 21.013 ;
     RECT  17.328 17.171 17.352 21.061 ;
     RECT  27.312 20.389 28.104 21.107 ;
     RECT  72.384 19.523 73.032 21.109 ;
     RECT  23.328 20.915 24.312 21.155 ;
     RECT  88.8 20.339 89.208 21.155 ;
     RECT  94.2 21.011 94.968 21.155 ;
     RECT  104.88 20.579 105.528 21.155 ;
     RECT  42.336 19.141 43.272 21.251 ;
     RECT  72.384 21.109 73.08 21.251 ;
     RECT  102.864 19.523 102.888 21.395 ;
     RECT  7.8 20.147 8.112 21.445 ;
     RECT  76.608 21.013 78.408 21.589 ;
     RECT  27.312 21.107 27.336 21.635 ;
     RECT  45.6 20.579 45.912 21.637 ;
     RECT  67.2 20.389 68.952 21.637 ;
     RECT  88.8 21.155 89.112 21.637 ;
     RECT  97.296 19.379 97.32 21.637 ;
     RECT  33.696 18.563 35.112 21.683 ;
     RECT  36.864 20.293 36.888 21.683 ;
     RECT  50.592 20.485 53.016 21.781 ;
     RECT  18.6 20.869 19.896 21.923 ;
     RECT  16.608 21.061 17.352 21.971 ;
     RECT  18.6 21.923 19.176 21.971 ;
     RECT  56.4 20.627 56.952 21.973 ;
     RECT  72.384 21.251 73.032 22.069 ;
     RECT  34.464 21.683 35.112 22.165 ;
     RECT  94.2 21.155 94.512 22.165 ;
     RECT  70.032 19.813 70.056 22.211 ;
     RECT  74.064 19.523 75.576 22.211 ;
     RECT  13.2 17.171 13.512 22.213 ;
     RECT  75.552 22.211 75.576 22.259 ;
     RECT  4.608 21.541 4.632 22.307 ;
     RECT  6.816 21.445 8.112 22.307 ;
     RECT  97.056 21.637 97.32 22.405 ;
     RECT  17.328 21.971 17.352 22.451 ;
     RECT  97.056 22.405 97.416 22.453 ;
     RECT  22.032 20.147 22.056 22.499 ;
     RECT  58.464 22.453 58.488 22.597 ;
     RECT  76.608 21.589 78.744 22.645 ;
     RECT  96.864 22.453 97.416 22.691 ;
     RECT  34.464 22.165 35.88 22.741 ;
     RECT  38.16 21.253 38.184 22.741 ;
     RECT  39.408 18.947 40.512 22.741 ;
     RECT  55.92 21.973 56.952 22.789 ;
     RECT  66.48 21.637 68.952 22.835 ;
     RECT  74.064 22.211 74.088 22.835 ;
     RECT  50.592 21.781 53.448 22.837 ;
     RECT  33.792 22.741 35.88 22.883 ;
     RECT  60.912 19.525 63.288 22.885 ;
     RECT  95.76 21.445 95.784 22.981 ;
     RECT  55.536 22.789 56.952 23.027 ;
     RECT  95.76 22.981 95.88 23.027 ;
     RECT  98.592 22.837 98.616 23.027 ;
     RECT  72.288 22.069 73.032 23.075 ;
     RECT  47.568 22.789 47.592 23.125 ;
     RECT  38.16 22.741 40.512 23.173 ;
     RECT  41.76 23.125 41.88 23.267 ;
     RECT  29.136 17.605 29.712 23.317 ;
     RECT  60.72 22.885 63.288 23.317 ;
     RECT  33.792 22.883 35.592 23.363 ;
     RECT  50.592 22.837 54.504 23.363 ;
     RECT  102.624 22.597 102.648 23.363 ;
     RECT  20.784 22.741 20.808 23.365 ;
     RECT  26.208 22.981 26.232 23.365 ;
     RECT  97.296 22.691 97.416 23.411 ;
     RECT  54.144 23.363 54.504 23.459 ;
     RECT  75.84 22.645 78.744 23.459 ;
     RECT  25.872 23.365 26.232 23.507 ;
     RECT  28.176 23.317 29.712 23.603 ;
     RECT  80.352 23.413 80.376 23.603 ;
     RECT  60.72 23.317 64.296 23.749 ;
     RECT  58.464 22.597 58.68 23.795 ;
     RECT  20.784 23.365 20.952 23.845 ;
     RECT  81.888 20.531 83.712 23.845 ;
     RECT  13.2 22.213 14.328 23.891 ;
     RECT  20.784 23.845 21.096 23.891 ;
     RECT  49.44 22.789 49.464 23.891 ;
     RECT  20.928 23.891 21.096 23.893 ;
     RECT  22.128 23.269 22.152 23.893 ;
     RECT  29.136 23.603 29.712 23.893 ;
     RECT  72.384 23.075 72.912 23.939 ;
     RECT  50.592 23.363 53.016 23.987 ;
     RECT  88.704 21.637 89.112 23.987 ;
     RECT  26.208 23.507 26.232 23.989 ;
     RECT  74.112 23.317 74.136 24.083 ;
     RECT  37.968 23.173 40.512 24.085 ;
     RECT  26.208 23.989 26.808 24.131 ;
     RECT  60.528 23.749 64.296 24.131 ;
     RECT  76.368 23.459 78.744 24.131 ;
     RECT  10.896 23.317 10.92 24.133 ;
     RECT  90.864 14.867 90.936 24.133 ;
     RECT  92.304 19.523 92.328 24.133 ;
     RECT  67.2 22.835 68.904 24.179 ;
     RECT  10.8 24.133 10.92 24.181 ;
     RECT  67.2 24.179 67.992 24.181 ;
     RECT  60.528 24.131 63.528 24.323 ;
     RECT  47.568 23.125 48.456 24.325 ;
     RECT  20.928 23.893 22.152 24.421 ;
     RECT  37.968 24.085 40.632 24.421 ;
     RECT  47.088 24.325 48.456 24.467 ;
     RECT  9.984 24.181 10.92 24.469 ;
     RECT  54.144 23.459 54.168 24.469 ;
     RECT  55.92 23.027 56.952 24.469 ;
     RECT  59.52 23.893 59.544 24.469 ;
     RECT  60.528 24.323 62.112 24.469 ;
     RECT  66.864 24.181 67.992 24.469 ;
     RECT  2.4 20.435 3.432 24.515 ;
     RECT  6 23.173 6.024 24.515 ;
     RECT  104.88 21.155 105.312 24.517 ;
     RECT  41.76 23.267 41.784 24.563 ;
     RECT  104.88 24.517 105.72 24.563 ;
     RECT  26.208 24.131 26.232 24.611 ;
     RECT  54.144 24.469 54.456 24.659 ;
     RECT  47.568 24.467 48.456 24.661 ;
     RECT  90.864 24.133 92.328 24.803 ;
     RECT  44.688 21.637 45.912 24.805 ;
     RECT  81.888 23.845 84.168 24.947 ;
     RECT  86.016 23.893 86.04 24.949 ;
     RECT  87.168 23.941 87.192 24.949 ;
     RECT  33.024 24.085 33.048 24.997 ;
     RECT  34.176 23.363 35.592 24.997 ;
     RECT  43.248 21.251 43.272 24.997 ;
     RECT  17.424 23.893 17.448 25.045 ;
     RECT  43.248 24.997 43.608 25.045 ;
     RECT  44.688 24.805 46.344 25.045 ;
     RECT  65.904 24.469 67.992 25.045 ;
     RECT  86.016 24.949 87.192 25.091 ;
     RECT  17.424 25.045 17.544 25.093 ;
     RECT  55.92 24.469 57 25.139 ;
     RECT  87.168 25.091 87.192 25.139 ;
     RECT  90.864 24.803 90.936 25.141 ;
     RECT  79.968 24.325 79.992 25.187 ;
     RECT  13.2 23.891 13.512 25.189 ;
     RECT  9.36 24.469 10.92 25.235 ;
     RECT  18.6 21.971 18.912 25.237 ;
     RECT  13.2 25.189 13.608 25.285 ;
     RECT  37.584 24.421 40.632 25.285 ;
     RECT  37.584 25.285 40.872 25.331 ;
     RECT  58.464 23.795 58.488 25.429 ;
     RECT  59.52 24.469 62.112 25.429 ;
     RECT  40.032 25.331 40.872 25.523 ;
     RECT  84.864 25.381 84.888 25.571 ;
     RECT  31.776 24.469 31.8 25.573 ;
     RECT  20.928 24.421 22.536 25.621 ;
     RECT  54.432 24.659 54.456 25.621 ;
     RECT  55.92 25.139 56.952 25.621 ;
     RECT  58.464 25.429 62.112 25.621 ;
     RECT  43.248 25.045 46.344 25.669 ;
     RECT  65.328 25.045 67.992 25.669 ;
     RECT  69.024 25.621 69.048 25.669 ;
     RECT  17.184 25.093 17.544 25.715 ;
     RECT  47.568 24.661 49.272 25.715 ;
     RECT  72.48 23.939 72.912 25.715 ;
     RECT  92.016 24.803 92.328 25.715 ;
     RECT  54.432 25.621 56.952 25.717 ;
     RECT  63.504 24.323 63.528 25.717 ;
     RECT  63.504 25.717 64.056 25.859 ;
     RECT  33.024 24.997 35.592 25.861 ;
     RECT  37.584 25.331 39.048 25.909 ;
     RECT  74.736 25.093 74.76 25.957 ;
     RECT  20.928 25.621 22.632 26.005 ;
     RECT  74.544 25.957 74.76 26.099 ;
     RECT  58.368 25.621 62.112 26.101 ;
     RECT  99.6 18.709 100.584 26.101 ;
     RECT  105 24.563 105.72 26.101 ;
     RECT  43.2 25.669 46.344 26.147 ;
     RECT  17.424 25.715 17.544 26.149 ;
     RECT  18.6 25.237 19.752 26.149 ;
     RECT  20.928 26.005 22.776 26.197 ;
     RECT  90.576 25.141 90.936 26.197 ;
     RECT  43.2 26.147 45.912 26.243 ;
     RECT  58.272 26.101 62.112 26.243 ;
     RECT  97.296 23.411 97.32 26.243 ;
     RECT  26.016 25.621 26.04 26.531 ;
     RECT  40.032 25.523 40.632 26.579 ;
     RECT  95.856 23.027 95.88 26.581 ;
     RECT  58.272 26.243 58.488 26.629 ;
     RECT  65.328 25.669 69.816 26.677 ;
     RECT  24 21.155 24.312 26.725 ;
     RECT  50.592 23.987 52.392 26.725 ;
     RECT  76.608 24.131 78.744 26.725 ;
     RECT  37.344 25.909 39.048 26.771 ;
     RECT  53.568 25.717 56.952 26.771 ;
     RECT  74.736 26.099 74.76 26.771 ;
     RECT  17.424 26.149 19.752 26.773 ;
     RECT  102.672 23.893 102.696 26.819 ;
     RECT  105 26.101 105.96 26.819 ;
     RECT  107.76 25.909 107.784 26.819 ;
     RECT  88.8 23.987 89.112 26.821 ;
     RECT  90.384 26.197 90.936 26.821 ;
     RECT  64.944 26.677 69.816 26.867 ;
     RECT  24 26.725 24.408 26.869 ;
     RECT  31.728 25.573 31.8 27.157 ;
     RECT  33.024 25.861 36.216 27.157 ;
     RECT  99.504 26.101 101.352 27.203 ;
     RECT  47.664 25.715 49.272 27.253 ;
     RECT  50.352 26.725 52.392 27.253 ;
     RECT  7.8 22.307 8.112 27.301 ;
     RECT  16.992 26.773 19.752 27.301 ;
     RECT  39.024 26.771 39.048 27.301 ;
     RECT  40.032 26.579 40.512 27.301 ;
     RECT  43.2 26.243 43.704 27.301 ;
     RECT  31.056 27.157 31.8 27.347 ;
     RECT  75.792 26.725 79.224 27.347 ;
     RECT  99.504 27.203 100.584 27.347 ;
     RECT  47.664 27.253 52.392 27.395 ;
     RECT  81.888 24.947 83.712 27.397 ;
     RECT  81.888 27.397 83.832 27.443 ;
     RECT  15.12 26.773 15.144 27.587 ;
     RECT  94.2 22.165 94.776 27.589 ;
     RECT  59.52 26.243 62.112 27.637 ;
     RECT  63.504 25.859 63.528 27.637 ;
     RECT  95.856 26.581 96.072 27.685 ;
     RECT  98.496 27.493 98.52 27.731 ;
     RECT  27.312 25.573 27.336 27.733 ;
     RECT  82.752 27.443 83.832 27.779 ;
     RECT  92.304 25.715 92.328 27.781 ;
     RECT  93.456 27.589 94.776 27.781 ;
     RECT  13.2 25.285 13.704 27.877 ;
     RECT  33.024 27.157 36.312 27.877 ;
     RECT  37.344 26.771 37.992 27.877 ;
     RECT  39.024 27.301 40.512 27.877 ;
     RECT  76.608 27.347 79.224 27.923 ;
     RECT  95.856 27.685 96.168 27.923 ;
     RECT  42.384 27.301 43.704 27.971 ;
     RECT  88.8 26.821 90.936 27.971 ;
     RECT  92.304 27.781 94.776 27.971 ;
     RECT  31.344 27.347 31.8 28.019 ;
     RECT  47.664 27.395 48.216 28.067 ;
     RECT  72.6 25.715 72.912 28.069 ;
     RECT  55.2 26.771 56.952 28.261 ;
     RECT  90.384 27.971 90.936 28.261 ;
     RECT  92.304 27.971 93.144 28.261 ;
     RECT  94.2 27.971 94.776 28.261 ;
     RECT  29.136 23.893 29.928 28.309 ;
     RECT  37.344 27.877 40.512 28.309 ;
     RECT  72.48 28.069 72.912 28.355 ;
     RECT  20.784 26.197 22.776 28.357 ;
     RECT  23.76 26.869 24.408 28.357 ;
     RECT  59.52 27.637 63.528 28.451 ;
     RECT  86.016 25.091 86.04 28.453 ;
     RECT  94.2 28.261 94.872 28.453 ;
     RECT  95.856 27.923 96.072 28.453 ;
     RECT  99.6 27.347 100.584 28.453 ;
     RECT  20.784 28.357 24.408 28.499 ;
     RECT  20.784 28.499 22.776 28.547 ;
     RECT  27.312 27.733 27.72 28.547 ;
     RECT  85.488 28.453 86.04 28.547 ;
     RECT  90.384 28.261 93.144 28.547 ;
     RECT  81.552 27.685 81.576 28.643 ;
     RECT  49.248 27.395 52.392 28.645 ;
     RECT  53.568 26.771 53.592 28.645 ;
     RECT  13.104 27.877 13.704 28.739 ;
     RECT  90.864 28.547 93.144 28.739 ;
     RECT  94.2 28.453 96.072 28.739 ;
     RECT  13.104 28.739 13.512 28.741 ;
     RECT  32.976 27.877 36.312 28.741 ;
     RECT  43.2 27.971 43.704 28.741 ;
     RECT  44.688 26.243 45.912 28.741 ;
     RECT  9.36 25.235 10.104 28.787 ;
     RECT  49.248 28.645 53.592 28.787 ;
     RECT  76.608 27.923 78.744 28.787 ;
     RECT  16.8 27.301 19.752 28.789 ;
     RECT  20.784 28.547 20.808 28.789 ;
     RECT  26.16 26.917 26.184 28.789 ;
     RECT  32.784 28.741 36.312 28.837 ;
     RECT  37.344 28.309 41.112 28.837 ;
     RECT  42.192 28.165 42.216 28.933 ;
     RECT  47.856 28.067 48.216 29.029 ;
     RECT  49.248 28.787 52.392 29.029 ;
     RECT  105 26.819 105.312 29.029 ;
     RECT  32.784 28.837 41.112 29.075 ;
     RECT  55.104 28.261 56.952 29.075 ;
     RECT  85.488 28.547 85.512 29.075 ;
     RECT  99.6 28.453 100.872 29.075 ;
     RECT  59.52 28.451 62.112 29.123 ;
     RECT  65.328 26.867 67.992 29.123 ;
     RECT  82.752 27.779 83.712 29.123 ;
     RECT  99.6 29.075 100.344 29.123 ;
     RECT  53.568 28.787 53.592 29.219 ;
     RECT  94.2 28.739 95.112 29.267 ;
     RECT  107.184 28.357 107.208 29.315 ;
     RECT  82.848 29.123 83.712 29.363 ;
     RECT  36.768 29.075 41.112 29.365 ;
     RECT  42.096 28.933 42.216 29.365 ;
     RECT  21.936 28.547 22.776 29.507 ;
     RECT  23.76 28.499 24.408 29.555 ;
     RECT  36.768 29.365 42.216 29.555 ;
     RECT  47.856 29.029 52.392 29.651 ;
     RECT  80.736 29.509 80.76 29.651 ;
     RECT  12.384 28.741 13.512 29.747 ;
     RECT  88.8 27.971 89.112 29.749 ;
     RECT  36.768 29.555 36.888 30.035 ;
     RECT  37.968 29.555 42.216 30.035 ;
     RECT  32.784 29.075 35.64 30.131 ;
     RECT  12.528 29.747 13.512 30.179 ;
     RECT  38.736 30.035 42.216 30.179 ;
     RECT  9.408 28.787 10.104 30.181 ;
     RECT  11.184 25.717 11.208 30.181 ;
     RECT  27.312 28.547 27.336 30.181 ;
     RECT  47.856 29.651 48.696 30.181 ;
     RECT  99.6 29.123 99.912 30.181 ;
     RECT  88.704 29.749 89.112 30.227 ;
     RECT  29.136 28.309 30.216 30.229 ;
     RECT  31.344 28.019 31.752 30.229 ;
     RECT  97.344 26.293 97.368 30.229 ;
     RECT  96.288 28.933 96.312 30.275 ;
     RECT  77.184 28.787 78.744 30.277 ;
     RECT  38.736 30.179 41.112 30.371 ;
     RECT  90.864 28.739 93 30.371 ;
     RECT  29.136 30.229 31.752 30.563 ;
     RECT  7.632 27.301 8.112 30.565 ;
     RECT  9.408 30.181 11.208 30.565 ;
     RECT  7.632 30.565 11.208 30.611 ;
     RECT  69.024 26.867 69.816 30.611 ;
     RECT  77.088 30.277 78.744 30.611 ;
     RECT  99.6 30.181 100.584 30.611 ;
     RECT  65.376 29.123 67.992 30.613 ;
     RECT  12.576 30.179 13.512 30.661 ;
     RECT  69.504 30.611 69.816 30.707 ;
     RECT  77.088 30.611 78.696 30.707 ;
     RECT  12.576 30.661 13.848 30.709 ;
     RECT  42.096 30.179 42.216 30.709 ;
     RECT  43.2 28.741 45.912 30.709 ;
     RECT  72.6 28.355 72.912 30.709 ;
     RECT  73.92 30.661 73.944 30.709 ;
     RECT  64.992 30.613 67.992 30.755 ;
     RECT  16.8 28.789 20.808 30.757 ;
     RECT  21.936 29.507 22.584 30.757 ;
     RECT  27.312 30.181 28.008 30.851 ;
     RECT  7.632 30.611 10.296 30.899 ;
     RECT  97.344 30.229 97.512 30.995 ;
     RECT  63.504 28.451 63.528 30.997 ;
     RECT  47.568 30.181 48.696 31.093 ;
     RECT  25.92 28.789 26.184 31.141 ;
     RECT  97.344 30.995 97.368 31.187 ;
     RECT  92.304 30.371 93 31.235 ;
     RECT  12.576 30.709 14.136 31.237 ;
     RECT  34.56 30.131 35.64 31.237 ;
     RECT  36.864 30.035 36.888 31.237 ;
     RECT  72.6 30.709 73.944 31.237 ;
     RECT  47.472 31.093 48.696 31.285 ;
     RECT  50.112 29.651 52.392 31.285 ;
     RECT  16.8 30.757 22.584 31.379 ;
     RECT  25.728 31.141 26.184 31.379 ;
     RECT  38.784 30.371 41.112 31.381 ;
     RECT  72.336 31.237 73.944 31.427 ;
     RECT  34.56 31.237 36.888 31.429 ;
     RECT  38.592 31.381 41.112 31.523 ;
     RECT  29.136 30.563 31.656 31.525 ;
     RECT  75.024 30.613 75.048 31.571 ;
     RECT  63.504 30.997 63.624 31.573 ;
     RECT  58.032 26.629 58.488 31.619 ;
     RECT  24 29.555 24.408 31.717 ;
     RECT  25.728 31.379 25.752 31.717 ;
     RECT  27.312 30.851 27.336 31.765 ;
     RECT  65.904 30.755 67.992 31.813 ;
     RECT  7.632 30.899 9.96 31.861 ;
     RECT  63.36 31.573 63.624 31.861 ;
     RECT  65.904 31.813 68.28 31.861 ;
     RECT  12.576 31.237 14.808 31.907 ;
     RECT  27.168 31.765 27.336 31.907 ;
     RECT  38.592 31.523 40.512 32.004 ;
     RECT  77.088 30.707 78.312 32.005 ;
     RECT  63.36 31.861 63.768 32.053 ;
     RECT  65.52 31.861 68.28 32.053 ;
     RECT  58.128 31.619 58.488 32.243 ;
     RECT  63.36 32.053 63.864 32.243 ;
     RECT  72.336 31.427 72.912 32.243 ;
     RECT  29.088 31.525 31.656 32.387 ;
     RECT  12.816 31.907 14.808 32.435 ;
     RECT  7.2 31.861 9.96 32.531 ;
     RECT  16.944 31.379 22.584 32.531 ;
     RECT  106.608 29.893 106.632 32.531 ;
     RECT  47.472 31.285 52.392 32.579 ;
     RECT  32.784 30.131 33.384 32.581 ;
     RECT  34.464 31.429 36.888 32.581 ;
     RECT  38.784 32.004 40.512 32.723 ;
     RECT  65.52 32.053 68.376 32.723 ;
     RECT  32.784 32.581 36.888 32.771 ;
     RECT  42.096 30.709 45.912 32.771 ;
     RECT  76.848 32.005 78.312 32.771 ;
     RECT  29.088 32.387 30.216 32.773 ;
     RECT  73.92 31.427 73.944 32.821 ;
     RECT  75.168 31.861 75.192 32.821 ;
     RECT  16.944 32.531 20.328 33.011 ;
     RECT  60.048 29.123 62.112 33.011 ;
     RECT  40.2 32.723 40.512 33.013 ;
     RECT  69.792 30.707 69.816 33.013 ;
     RECT  70.944 32.533 70.968 33.013 ;
     RECT  7.632 32.531 9.96 33.061 ;
     RECT  60.048 33.011 60.072 33.061 ;
     RECT  61.344 33.011 62.112 33.061 ;
     RECT  63.36 32.243 63.768 33.061 ;
     RECT  17.328 33.011 20.328 33.107 ;
     RECT  73.92 32.821 75.192 33.107 ;
     RECT  69.792 33.013 70.968 33.155 ;
     RECT  17.328 33.107 19.656 33.299 ;
     RECT  42.48 32.771 45.912 33.445 ;
     RECT  36.864 32.771 36.888 33.541 ;
     RECT  55.2 29.075 56.952 33.635 ;
     RECT  40.2 33.013 41.112 33.683 ;
     RECT  65.808 32.723 68.376 33.683 ;
     RECT  73.92 33.107 75.144 33.683 ;
     RECT  38.784 32.723 38.904 33.781 ;
     RECT  105 29.029 105.48 33.925 ;
     RECT  17.328 33.299 19.176 33.971 ;
     RECT  55.728 33.635 56.952 34.021 ;
     RECT  58.128 32.243 58.392 34.021 ;
     RECT  7.632 33.061 10.296 34.115 ;
     RECT  61.344 33.061 63.768 34.115 ;
     RECT  38.736 33.781 38.904 34.211 ;
     RECT  55.728 34.021 58.392 34.211 ;
     RECT  65.808 33.683 67.848 34.259 ;
     RECT  32.784 32.771 35.88 34.355 ;
     RECT  42.48 33.445 46.152 34.403 ;
     RECT  63.36 34.115 63.768 34.405 ;
     RECT  38.736 34.211 38.808 34.453 ;
     RECT  75.12 33.683 75.144 34.501 ;
     RECT  7.8 34.115 10.296 34.595 ;
     RECT  32.784 34.355 33.24 34.595 ;
     RECT  17.328 33.971 18.912 34.693 ;
     RECT  21.312 32.531 22.584 34.693 ;
     RECT  31.392 32.387 31.656 34.693 ;
     RECT  36.864 33.541 36.936 34.739 ;
     RECT  12.816 32.435 14.136 34.741 ;
     RECT  27.168 31.907 27.192 34.741 ;
     RECT  28.8 32.773 30.216 34.741 ;
     RECT  47.568 32.579 52.392 34.837 ;
     RECT  36.912 34.739 36.936 34.883 ;
     RECT  12.816 34.741 14.232 34.931 ;
     RECT  47.568 34.837 52.968 34.931 ;
     RECT  65.904 34.259 67.848 34.933 ;
     RECT  42.48 34.403 45.912 35.027 ;
     RECT  49.44 34.931 52.968 35.029 ;
     RECT  63.36 34.405 64.632 35.075 ;
     RECT  24 31.717 25.752 35.123 ;
     RECT  34.656 34.355 35.88 35.123 ;
     RECT  61.344 34.115 62.232 35.123 ;
     RECT  17.088 34.693 18.912 35.269 ;
     RECT  38.544 34.453 38.808 35.269 ;
     RECT  40.2 33.683 41.016 35.269 ;
     RECT  55.872 34.211 58.392 35.269 ;
     RECT  59.52 33.061 60.072 35.269 ;
     RECT  65.904 34.933 67.896 35.315 ;
     RECT  66.384 35.315 67.896 35.317 ;
     RECT  72.6 32.243 72.912 35.317 ;
     RECT  55.872 35.269 60.072 35.461 ;
     RECT  17.088 35.269 19.848 35.509 ;
     RECT  17.088 35.509 20.088 35.603 ;
     RECT  55.488 35.461 60.072 35.603 ;
     RECT  12.816 34.931 14.136 35.605 ;
     RECT  27.168 34.741 30.216 35.699 ;
     RECT  72.384 35.317 72.912 35.845 ;
     RECT  49.44 35.029 53.016 35.939 ;
     RECT  75.12 34.501 75.864 35.939 ;
     RECT  37.824 35.269 38.808 35.987 ;
     RECT  73.92 33.683 73.944 36.323 ;
     RECT  25.632 35.123 25.752 36.371 ;
     RECT  56.4 35.603 60.072 36.371 ;
     RECT  66.384 35.317 68.328 36.469 ;
     RECT  34.656 35.123 35.688 36.515 ;
     RECT  42.48 35.027 44.424 36.515 ;
     RECT  32.784 34.595 32.808 36.563 ;
     RECT  72.336 35.845 72.912 36.563 ;
     RECT  49.44 35.939 51.864 36.611 ;
     RECT  40.08 35.269 41.016 36.613 ;
     RECT  65.76 36.469 68.328 36.661 ;
     RECT  63.36 35.075 63.96 36.755 ;
     RECT  28.8 35.699 30.216 36.803 ;
     RECT  39.84 36.613 41.016 36.803 ;
     RECT  55.296 35.989 55.32 36.803 ;
     RECT  65.76 36.661 68.952 36.803 ;
     RECT  52.944 35.939 53.016 36.851 ;
     RECT  76.896 32.771 78.312 36.851 ;
     RECT  43.2 36.515 44.424 36.853 ;
     RECT  7.8 34.595 10.152 36.899 ;
     RECT  47.568 34.931 48.456 36.947 ;
     RECT  65.76 36.803 68.328 36.947 ;
     RECT  75.12 35.939 75.144 36.949 ;
     RECT  9.6 36.899 10.152 37.045 ;
     RECT  24 35.123 24.408 37.091 ;
     RECT  52.944 36.851 52.968 37.091 ;
     RECT  12.336 35.605 14.136 37.187 ;
     RECT  61.68 35.123 62.232 37.189 ;
     RECT  63.36 36.755 63.384 37.189 ;
     RECT  38.544 35.987 38.808 37.283 ;
     RECT  61.68 37.189 63.384 37.331 ;
     RECT  12.336 37.187 13.848 37.379 ;
     RECT  29.088 36.803 30.216 37.379 ;
     RECT  40.2 36.803 41.016 37.379 ;
     RECT  48.432 36.947 48.456 37.429 ;
     RECT  49.44 36.611 51.768 37.429 ;
     RECT  38.784 37.283 38.808 37.475 ;
     RECT  17.328 35.603 20.088 37.525 ;
     RECT  21.312 34.693 22.68 37.525 ;
     RECT  17.328 37.525 22.68 37.573 ;
     RECT  27.168 35.699 27.336 37.573 ;
     RECT  54.288 36.421 54.312 37.573 ;
     RECT  75.12 36.949 75.384 37.573 ;
     RECT  9.6 37.045 10.824 37.619 ;
     RECT  12.336 37.379 13.656 37.619 ;
     RECT  17.328 37.573 22.776 37.619 ;
     RECT  34.8 36.515 35.688 37.619 ;
     RECT  76.896 36.851 76.92 37.619 ;
     RECT  31.344 34.693 31.656 37.715 ;
     RECT  25.68 36.371 25.752 37.861 ;
     RECT  12.336 37.619 13.512 37.907 ;
     RECT  26.736 37.573 27.336 38.003 ;
     RECT  56.4 36.371 58.536 38.099 ;
     RECT  58.512 38.099 58.536 38.147 ;
     RECT  29.136 37.379 30.216 38.149 ;
     RECT  31.344 37.715 31.416 38.149 ;
     RECT  45.6 35.027 45.912 38.197 ;
     RECT  26.736 38.003 26.76 38.243 ;
     RECT  18.432 37.619 22.776 38.291 ;
     RECT  74.64 37.573 75.384 38.291 ;
     RECT  48.432 37.429 51.768 38.387 ;
     RECT  9.6 37.619 9.624 38.435 ;
     RECT  21.312 38.291 22.776 38.483 ;
     RECT  45.6 38.197 46.728 38.483 ;
     RECT  74.64 38.291 75.144 38.483 ;
     RECT  60.048 36.371 60.072 38.627 ;
     RECT  43.2 36.853 44.568 38.629 ;
     RECT  16.32 37.573 16.344 38.675 ;
     RECT  37.344 38.149 37.368 38.677 ;
     RECT  24 37.091 24.312 38.725 ;
     RECT  34.8 37.619 35.352 38.725 ;
     RECT  36.576 38.677 37.368 38.725 ;
     RECT  42.768 38.629 44.568 38.771 ;
     RECT  25.44 37.861 25.752 38.773 ;
     RECT  12.816 37.907 13.512 38.819 ;
     RECT  29.136 38.149 31.416 38.819 ;
     RECT  25.44 38.773 26.472 38.963 ;
     RECT  75.12 38.483 75.144 38.963 ;
     RECT  32.688 38.773 32.712 39.011 ;
     RECT  49.056 38.387 51.768 39.011 ;
     RECT  70.032 33.155 70.968 39.011 ;
     RECT  31.344 38.819 31.416 39.013 ;
     RECT  40.2 37.379 40.632 39.013 ;
     RECT  10.8 37.619 10.824 39.059 ;
     RECT  24 38.725 24.408 39.059 ;
     RECT  31.344 39.013 31.896 39.059 ;
     RECT  34.8 38.725 37.368 39.059 ;
     RECT  42.912 38.771 44.568 39.107 ;
     RECT  105 33.925 106.056 39.109 ;
     RECT  105 39.109 106.584 39.155 ;
     RECT  25.44 38.963 25.752 39.251 ;
     RECT  31.872 39.059 31.896 39.251 ;
     RECT  40.2 39.013 41.016 39.251 ;
     RECT  63.36 37.331 63.384 39.251 ;
     RECT  66.096 36.947 68.328 39.253 ;
     RECT  65.712 39.253 68.328 39.301 ;
     RECT  70.944 39.011 70.968 39.301 ;
     RECT  70.944 39.301 71.112 39.347 ;
     RECT  34.8 39.059 35.784 39.349 ;
     RECT  47.856 38.437 47.88 39.349 ;
     RECT  28.128 38.725 28.152 39.395 ;
     RECT  40.2 39.251 40.92 39.395 ;
     RECT  42.912 39.107 43.416 39.395 ;
     RECT  47.328 39.349 47.88 39.395 ;
     RECT  37.152 39.059 37.368 39.491 ;
     RECT  21.312 38.483 22.2 39.539 ;
     RECT  65.52 39.301 68.328 39.539 ;
     RECT  49.44 39.011 51.768 39.587 ;
     RECT  71.088 39.347 71.112 39.587 ;
     RECT  56.4 38.099 57.432 39.589 ;
     RECT  17.328 37.619 17.352 39.779 ;
     RECT  13.2 38.819 13.512 39.781 ;
     RECT  45.6 38.483 45.912 39.781 ;
     RECT  47.328 39.395 47.352 39.827 ;
     RECT  54.288 37.573 54.792 39.875 ;
     RECT  65.52 39.539 67.8 39.875 ;
     RECT  34.704 39.349 35.784 39.877 ;
     RECT  22.08 39.539 22.2 39.923 ;
     RECT  69.504 39.061 69.528 39.923 ;
     RECT  43.2 39.395 43.416 40.019 ;
     RECT  65.52 39.875 65.544 40.021 ;
     RECT  43.2 40.019 43.224 40.067 ;
     RECT  44.4 39.107 44.568 40.067 ;
     RECT  61.68 37.331 62.328 40.067 ;
     RECT  65.04 40.021 65.544 40.067 ;
     RECT  18.432 38.291 19.848 40.163 ;
     RECT  49.44 39.587 51.312 40.163 ;
     RECT  47.136 40.069 47.16 40.211 ;
     RECT  34.224 39.877 35.784 40.259 ;
     RECT  66.672 39.875 67.8 40.259 ;
     RECT  50.112 40.163 51.312 40.307 ;
     RECT  7.8 36.899 8.472 40.355 ;
     RECT  56.4 39.589 57.576 40.355 ;
     RECT  67.2 40.259 67.8 40.355 ;
     RECT  25.44 39.251 25.464 40.357 ;
     RECT  25.44 40.357 26.232 40.403 ;
     RECT  37.152 39.491 37.176 40.403 ;
     RECT  45.6 39.781 46.008 40.451 ;
     RECT  13.2 39.781 14.136 40.499 ;
     RECT  54.288 39.875 54.312 40.595 ;
     RECT  44.4 40.067 44.424 40.643 ;
     RECT  61.8 40.067 62.328 40.643 ;
     RECT  26.208 40.403 26.232 40.691 ;
     RECT  29.136 38.819 29.712 40.741 ;
     RECT  65.04 40.067 65.064 40.835 ;
     RECT  29.088 40.741 29.712 40.883 ;
     RECT  34.224 40.259 35.112 40.883 ;
     RECT  22.128 39.923 22.2 41.269 ;
     RECT  29.136 40.883 29.712 41.891 ;
     RECT  90.864 30.371 90.936 41.939 ;
     RECT  90.864 41.939 90.888 42.467 ;
     RECT  22.08 41.269 22.2 42.469 ;
     RECT  105 39.155 105.48 42.757 ;
     RECT  106.56 39.155 106.584 42.757 ;
     RECT  105 42.757 106.584 42.803 ;
     RECT  105 42.803 106.056 45.731 ;
     RECT  105 45.731 105.48 47.845 ;
     RECT  92.304 31.235 92.328 53.507 ;
     RECT  105 47.845 106.056 54.277 ;
     RECT  105 54.277 106.296 55.859 ;
     RECT  7.8 40.355 8.232 57.443 ;
     RECT  22.032 42.469 22.2 58.355 ;
     RECT  22.032 58.355 22.104 59.411 ;
     RECT  22.08 59.411 22.104 59.699 ;
     RECT  105 55.859 106.056 59.797 ;
     RECT  104.4 59.797 106.056 59.843 ;
     RECT  18.432 40.163 18.912 61.187 ;
     RECT  104.4 59.843 105.312 62.291 ;
     RECT  2.4 24.515 2.712 62.649 ;
     RECT  7.8 57.443 8.112 62.649 ;
     RECT  13.2 40.499 13.512 62.649 ;
     RECT  18.6 61.187 18.912 62.649 ;
     RECT  24 39.059 24.312 62.649 ;
     RECT  29.4 41.891 29.712 62.649 ;
     RECT  34.8 40.883 35.112 62.649 ;
     RECT  40.2 39.395 40.512 62.649 ;
     RECT  45.6 40.451 45.912 62.649 ;
     RECT  51 40.307 51.312 62.649 ;
     RECT  56.4 40.355 56.712 62.649 ;
     RECT  61.8 40.643 62.112 62.649 ;
     RECT  67.2 40.355 67.512 62.649 ;
     RECT  72.6 36.563 72.912 62.649 ;
     RECT  78 36.851 78.312 62.649 ;
     RECT  83.4 29.363 83.712 62.649 ;
     RECT  88.8 30.227 89.112 62.649 ;
     RECT  94.2 29.267 94.512 62.649 ;
     RECT  99.6 30.611 99.912 62.649 ;
     RECT  105 62.291 105.312 62.649 ;
     RECT  2.4 62.649 2.52 62.663 ;
     RECT  7.8 62.649 7.92 62.663 ;
     RECT  13.2 62.649 13.32 62.663 ;
     RECT  18.6 62.649 18.72 62.663 ;
     RECT  94.2 62.649 94.32 62.663 ;
     RECT  99.6 62.649 99.72 62.663 ;
     RECT  105 62.649 105.12 62.663 ;
  END
END ot_hgi_coll_fj_n2s1_r256
END LIBRARY
